VERSION 5.8 ;
BUSBITCHARS "[]" ;
DIVIDERCHAR "/" ;
UNITS
    DATABASE MICRONS 1000 ;
END UNITS

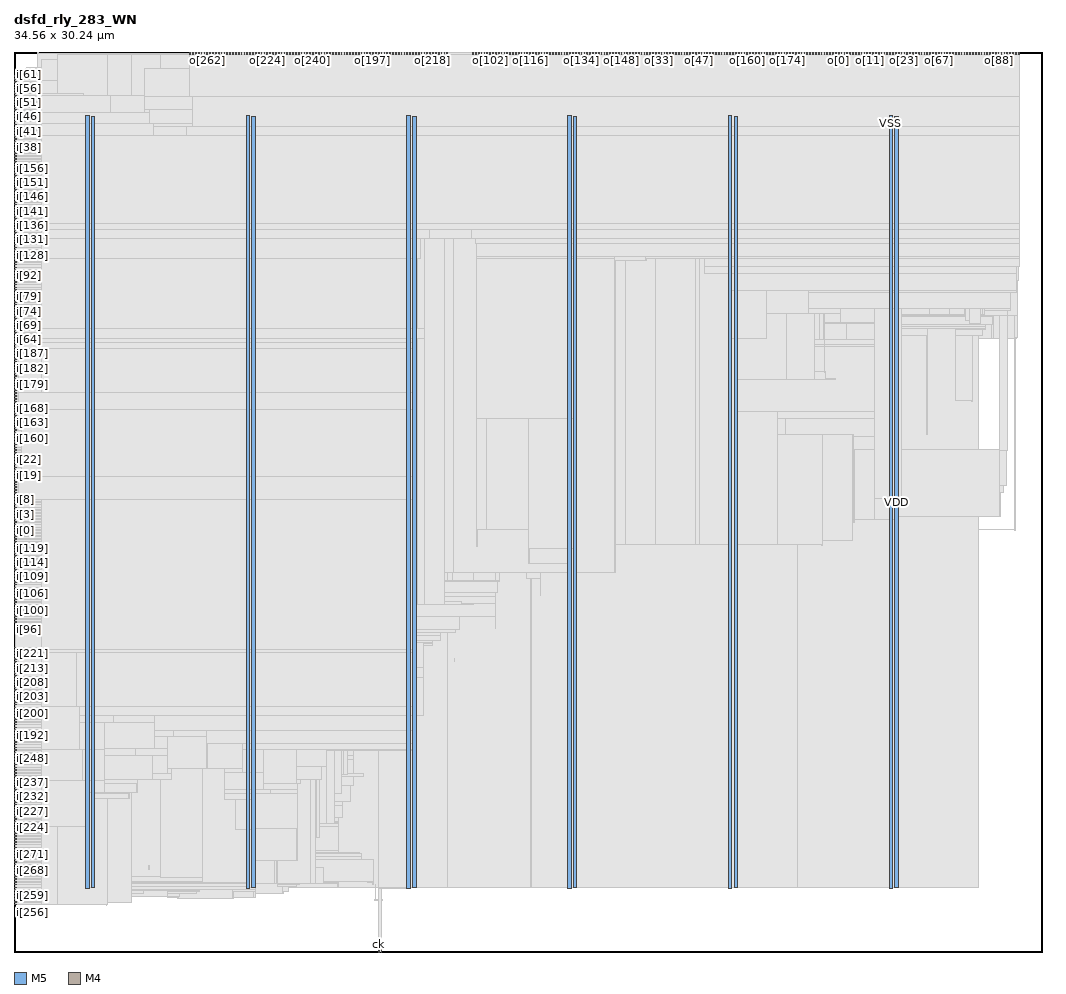
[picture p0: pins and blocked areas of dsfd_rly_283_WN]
MACRO dsfd_rly_283_WN
  FOREIGN dsfd_rly_283_WN 0 0 ;
  CLASS BLOCK ;
  SIZE 34.56 BY 30.24 ;
  PIN ck
    DIRECTION INPUT ;
    USE SIGNAL ;
    PORT
      LAYER M5 ;
        RECT  12.24 0 12.264 0.084 ;
    END
  END ck
  PIN i[0]
    DIRECTION INPUT ;
    USE SIGNAL ;
    PORT
      LAYER M4 ;
        RECT  0 14.16 0.084 14.184 ;
    END
  END i[0]
  PIN i[100]
    DIRECTION INPUT ;
    USE SIGNAL ;
    PORT
      LAYER M4 ;
        RECT  0 11.472 0.084 11.496 ;
    END
  END i[100]
  PIN i[101]
    DIRECTION INPUT ;
    USE SIGNAL ;
    PORT
      LAYER M4 ;
        RECT  0 11.568 0.084 11.592 ;
    END
  END i[101]
  PIN i[102]
    DIRECTION INPUT ;
    USE SIGNAL ;
    PORT
      LAYER M4 ;
        RECT  0 11.664 0.084 11.688 ;
    END
  END i[102]
  PIN i[103]
    DIRECTION INPUT ;
    USE SIGNAL ;
    PORT
      LAYER M4 ;
        RECT  0 11.76 0.084 11.784 ;
    END
  END i[103]
  PIN i[104]
    DIRECTION INPUT ;
    USE SIGNAL ;
    PORT
      LAYER M4 ;
        RECT  0 11.856 0.084 11.88 ;
    END
  END i[104]
  PIN i[105]
    DIRECTION INPUT ;
    USE SIGNAL ;
    PORT
      LAYER M4 ;
        RECT  0 11.952 0.084 11.976 ;
    END
  END i[105]
  PIN i[106]
    DIRECTION INPUT ;
    USE SIGNAL ;
    PORT
      LAYER M4 ;
        RECT  0 12.048 0.084 12.072 ;
    END
  END i[106]
  PIN i[107]
    DIRECTION INPUT ;
    USE SIGNAL ;
    PORT
      LAYER M4 ;
        RECT  0 12.144 0.084 12.168 ;
    END
  END i[107]
  PIN i[108]
    DIRECTION INPUT ;
    USE SIGNAL ;
    PORT
      LAYER M4 ;
        RECT  0 12.24 0.084 12.264 ;
    END
  END i[108]
  PIN i[109]
    DIRECTION INPUT ;
    USE SIGNAL ;
    PORT
      LAYER M4 ;
        RECT  0 12.336 0.084 12.36 ;
    END
  END i[109]
  PIN i[10]
    DIRECTION INPUT ;
    USE SIGNAL ;
    PORT
      LAYER M4 ;
        RECT  0 15.12 0.084 15.144 ;
    END
  END i[10]
  PIN i[110]
    DIRECTION INPUT ;
    USE SIGNAL ;
    PORT
      LAYER M4 ;
        RECT  0 12.432 0.084 12.456 ;
    END
  END i[110]
  PIN i[111]
    DIRECTION INPUT ;
    USE SIGNAL ;
    PORT
      LAYER M4 ;
        RECT  0 12.528 0.084 12.552 ;
    END
  END i[111]
  PIN i[112]
    DIRECTION INPUT ;
    USE SIGNAL ;
    PORT
      LAYER M4 ;
        RECT  0 12.624 0.084 12.648 ;
    END
  END i[112]
  PIN i[113]
    DIRECTION INPUT ;
    USE SIGNAL ;
    PORT
      LAYER M4 ;
        RECT  0 12.72 0.084 12.744 ;
    END
  END i[113]
  PIN i[114]
    DIRECTION INPUT ;
    USE SIGNAL ;
    PORT
      LAYER M4 ;
        RECT  0 12.816 0.084 12.84 ;
    END
  END i[114]
  PIN i[115]
    DIRECTION INPUT ;
    USE SIGNAL ;
    PORT
      LAYER M4 ;
        RECT  0 12.912 0.084 12.936 ;
    END
  END i[115]
  PIN i[116]
    DIRECTION INPUT ;
    USE SIGNAL ;
    PORT
      LAYER M4 ;
        RECT  0 13.008 0.084 13.032 ;
    END
  END i[116]
  PIN i[117]
    DIRECTION INPUT ;
    USE SIGNAL ;
    PORT
      LAYER M4 ;
        RECT  0 13.104 0.084 13.128 ;
    END
  END i[117]
  PIN i[118]
    DIRECTION INPUT ;
    USE SIGNAL ;
    PORT
      LAYER M4 ;
        RECT  0 13.2 0.084 13.224 ;
    END
  END i[118]
  PIN i[119]
    DIRECTION INPUT ;
    USE SIGNAL ;
    PORT
      LAYER M4 ;
        RECT  0 13.296 0.084 13.32 ;
    END
  END i[119]
  PIN i[11]
    DIRECTION INPUT ;
    USE SIGNAL ;
    PORT
      LAYER M4 ;
        RECT  0 15.216 0.084 15.24 ;
    END
  END i[11]
  PIN i[120]
    DIRECTION INPUT ;
    USE SIGNAL ;
    PORT
      LAYER M4 ;
        RECT  0 13.392 0.084 13.416 ;
    END
  END i[120]
  PIN i[121]
    DIRECTION INPUT ;
    USE SIGNAL ;
    PORT
      LAYER M4 ;
        RECT  0 13.488 0.084 13.512 ;
    END
  END i[121]
  PIN i[122]
    DIRECTION INPUT ;
    USE SIGNAL ;
    PORT
      LAYER M4 ;
        RECT  0 13.584 0.084 13.608 ;
    END
  END i[122]
  PIN i[123]
    DIRECTION INPUT ;
    USE SIGNAL ;
    PORT
      LAYER M4 ;
        RECT  0 13.68 0.084 13.704 ;
    END
  END i[123]
  PIN i[124]
    DIRECTION INPUT ;
    USE SIGNAL ;
    PORT
      LAYER M4 ;
        RECT  0 13.776 0.084 13.8 ;
    END
  END i[124]
  PIN i[125]
    DIRECTION INPUT ;
    USE SIGNAL ;
    PORT
      LAYER M4 ;
        RECT  0 13.872 0.084 13.896 ;
    END
  END i[125]
  PIN i[126]
    DIRECTION INPUT ;
    USE SIGNAL ;
    PORT
      LAYER M4 ;
        RECT  0 13.968 0.084 13.992 ;
    END
  END i[126]
  PIN i[127]
    DIRECTION INPUT ;
    USE SIGNAL ;
    PORT
      LAYER M4 ;
        RECT  0 14.064 0.084 14.088 ;
    END
  END i[127]
  PIN i[128]
    DIRECTION INPUT ;
    USE SIGNAL ;
    PORT
      LAYER M4 ;
        RECT  0 23.376 0.084 23.4 ;
    END
  END i[128]
  PIN i[129]
    DIRECTION INPUT ;
    USE SIGNAL ;
    PORT
      LAYER M4 ;
        RECT  0 23.472 0.084 23.496 ;
    END
  END i[129]
  PIN i[12]
    DIRECTION INPUT ;
    USE SIGNAL ;
    PORT
      LAYER M4 ;
        RECT  0 15.312 0.084 15.336 ;
    END
  END i[12]
  PIN i[130]
    DIRECTION INPUT ;
    USE SIGNAL ;
    PORT
      LAYER M4 ;
        RECT  0 23.568 0.084 23.592 ;
    END
  END i[130]
  PIN i[131]
    DIRECTION INPUT ;
    USE SIGNAL ;
    PORT
      LAYER M4 ;
        RECT  0 23.664 0.084 23.688 ;
    END
  END i[131]
  PIN i[132]
    DIRECTION INPUT ;
    USE SIGNAL ;
    PORT
      LAYER M4 ;
        RECT  0 23.76 0.084 23.784 ;
    END
  END i[132]
  PIN i[133]
    DIRECTION INPUT ;
    USE SIGNAL ;
    PORT
      LAYER M4 ;
        RECT  0 23.856 0.084 23.88 ;
    END
  END i[133]
  PIN i[134]
    DIRECTION INPUT ;
    USE SIGNAL ;
    PORT
      LAYER M4 ;
        RECT  0 23.952 0.084 23.976 ;
    END
  END i[134]
  PIN i[135]
    DIRECTION INPUT ;
    USE SIGNAL ;
    PORT
      LAYER M4 ;
        RECT  0 24.048 0.084 24.072 ;
    END
  END i[135]
  PIN i[136]
    DIRECTION INPUT ;
    USE SIGNAL ;
    PORT
      LAYER M4 ;
        RECT  0 24.144 0.084 24.168 ;
    END
  END i[136]
  PIN i[137]
    DIRECTION INPUT ;
    USE SIGNAL ;
    PORT
      LAYER M4 ;
        RECT  0 24.24 0.084 24.264 ;
    END
  END i[137]
  PIN i[138]
    DIRECTION INPUT ;
    USE SIGNAL ;
    PORT
      LAYER M4 ;
        RECT  0 24.336 0.084 24.36 ;
    END
  END i[138]
  PIN i[139]
    DIRECTION INPUT ;
    USE SIGNAL ;
    PORT
      LAYER M4 ;
        RECT  0 24.432 0.084 24.456 ;
    END
  END i[139]
  PIN i[13]
    DIRECTION INPUT ;
    USE SIGNAL ;
    PORT
      LAYER M4 ;
        RECT  0 15.408 0.084 15.432 ;
    END
  END i[13]
  PIN i[140]
    DIRECTION INPUT ;
    USE SIGNAL ;
    PORT
      LAYER M4 ;
        RECT  0 24.528 0.084 24.552 ;
    END
  END i[140]
  PIN i[141]
    DIRECTION INPUT ;
    USE SIGNAL ;
    PORT
      LAYER M4 ;
        RECT  0 24.624 0.084 24.648 ;
    END
  END i[141]
  PIN i[142]
    DIRECTION INPUT ;
    USE SIGNAL ;
    PORT
      LAYER M4 ;
        RECT  0 24.72 0.084 24.744 ;
    END
  END i[142]
  PIN i[143]
    DIRECTION INPUT ;
    USE SIGNAL ;
    PORT
      LAYER M4 ;
        RECT  0 24.816 0.084 24.84 ;
    END
  END i[143]
  PIN i[144]
    DIRECTION INPUT ;
    USE SIGNAL ;
    PORT
      LAYER M4 ;
        RECT  0 24.912 0.084 24.936 ;
    END
  END i[144]
  PIN i[145]
    DIRECTION INPUT ;
    USE SIGNAL ;
    PORT
      LAYER M4 ;
        RECT  0 25.008 0.084 25.032 ;
    END
  END i[145]
  PIN i[146]
    DIRECTION INPUT ;
    USE SIGNAL ;
    PORT
      LAYER M4 ;
        RECT  0 25.104 0.084 25.128 ;
    END
  END i[146]
  PIN i[147]
    DIRECTION INPUT ;
    USE SIGNAL ;
    PORT
      LAYER M4 ;
        RECT  0 25.2 0.084 25.224 ;
    END
  END i[147]
  PIN i[148]
    DIRECTION INPUT ;
    USE SIGNAL ;
    PORT
      LAYER M4 ;
        RECT  0 25.296 0.084 25.32 ;
    END
  END i[148]
  PIN i[149]
    DIRECTION INPUT ;
    USE SIGNAL ;
    PORT
      LAYER M4 ;
        RECT  0 25.392 0.084 25.416 ;
    END
  END i[149]
  PIN i[14]
    DIRECTION INPUT ;
    USE SIGNAL ;
    PORT
      LAYER M4 ;
        RECT  0 15.504 0.084 15.528 ;
    END
  END i[14]
  PIN i[150]
    DIRECTION INPUT ;
    USE SIGNAL ;
    PORT
      LAYER M4 ;
        RECT  0 25.488 0.084 25.512 ;
    END
  END i[150]
  PIN i[151]
    DIRECTION INPUT ;
    USE SIGNAL ;
    PORT
      LAYER M4 ;
        RECT  0 25.584 0.084 25.608 ;
    END
  END i[151]
  PIN i[152]
    DIRECTION INPUT ;
    USE SIGNAL ;
    PORT
      LAYER M4 ;
        RECT  0 25.68 0.084 25.704 ;
    END
  END i[152]
  PIN i[153]
    DIRECTION INPUT ;
    USE SIGNAL ;
    PORT
      LAYER M4 ;
        RECT  0 25.776 0.084 25.8 ;
    END
  END i[153]
  PIN i[154]
    DIRECTION INPUT ;
    USE SIGNAL ;
    PORT
      LAYER M4 ;
        RECT  0 25.872 0.084 25.896 ;
    END
  END i[154]
  PIN i[155]
    DIRECTION INPUT ;
    USE SIGNAL ;
    PORT
      LAYER M4 ;
        RECT  0 25.968 0.084 25.992 ;
    END
  END i[155]
  PIN i[156]
    DIRECTION INPUT ;
    USE SIGNAL ;
    PORT
      LAYER M4 ;
        RECT  0 26.064 0.084 26.088 ;
    END
  END i[156]
  PIN i[157]
    DIRECTION INPUT ;
    USE SIGNAL ;
    PORT
      LAYER M4 ;
        RECT  0 26.16 0.084 26.184 ;
    END
  END i[157]
  PIN i[158]
    DIRECTION INPUT ;
    USE SIGNAL ;
    PORT
      LAYER M4 ;
        RECT  0 26.256 0.084 26.28 ;
    END
  END i[158]
  PIN i[159]
    DIRECTION INPUT ;
    USE SIGNAL ;
    PORT
      LAYER M4 ;
        RECT  0 26.352 0.084 26.376 ;
    END
  END i[159]
  PIN i[15]
    DIRECTION INPUT ;
    USE SIGNAL ;
    PORT
      LAYER M4 ;
        RECT  0 15.6 0.084 15.624 ;
    END
  END i[15]
  PIN i[160]
    DIRECTION INPUT ;
    USE SIGNAL ;
    PORT
      LAYER M4 ;
        RECT  0 17.232 0.084 17.256 ;
    END
  END i[160]
  PIN i[161]
    DIRECTION INPUT ;
    USE SIGNAL ;
    PORT
      LAYER M4 ;
        RECT  0 17.328 0.084 17.352 ;
    END
  END i[161]
  PIN i[162]
    DIRECTION INPUT ;
    USE SIGNAL ;
    PORT
      LAYER M4 ;
        RECT  0 17.424 0.084 17.448 ;
    END
  END i[162]
  PIN i[163]
    DIRECTION INPUT ;
    USE SIGNAL ;
    PORT
      LAYER M4 ;
        RECT  0 17.52 0.084 17.544 ;
    END
  END i[163]
  PIN i[164]
    DIRECTION INPUT ;
    USE SIGNAL ;
    PORT
      LAYER M4 ;
        RECT  0 17.616 0.084 17.64 ;
    END
  END i[164]
  PIN i[165]
    DIRECTION INPUT ;
    USE SIGNAL ;
    PORT
      LAYER M4 ;
        RECT  0 17.712 0.084 17.736 ;
    END
  END i[165]
  PIN i[166]
    DIRECTION INPUT ;
    USE SIGNAL ;
    PORT
      LAYER M4 ;
        RECT  0 17.808 0.084 17.832 ;
    END
  END i[166]
  PIN i[167]
    DIRECTION INPUT ;
    USE SIGNAL ;
    PORT
      LAYER M4 ;
        RECT  0 17.904 0.084 17.928 ;
    END
  END i[167]
  PIN i[168]
    DIRECTION INPUT ;
    USE SIGNAL ;
    PORT
      LAYER M4 ;
        RECT  0 18 0.084 18.024 ;
    END
  END i[168]
  PIN i[169]
    DIRECTION INPUT ;
    USE SIGNAL ;
    PORT
      LAYER M4 ;
        RECT  0 18.096 0.084 18.12 ;
    END
  END i[169]
  PIN i[16]
    DIRECTION INPUT ;
    USE SIGNAL ;
    PORT
      LAYER M4 ;
        RECT  0 15.696 0.084 15.72 ;
    END
  END i[16]
  PIN i[170]
    DIRECTION INPUT ;
    USE SIGNAL ;
    PORT
      LAYER M4 ;
        RECT  0 18.192 0.084 18.216 ;
    END
  END i[170]
  PIN i[171]
    DIRECTION INPUT ;
    USE SIGNAL ;
    PORT
      LAYER M4 ;
        RECT  0 18.288 0.084 18.312 ;
    END
  END i[171]
  PIN i[172]
    DIRECTION INPUT ;
    USE SIGNAL ;
    PORT
      LAYER M4 ;
        RECT  0 18.384 0.084 18.408 ;
    END
  END i[172]
  PIN i[173]
    DIRECTION INPUT ;
    USE SIGNAL ;
    PORT
      LAYER M4 ;
        RECT  0 18.48 0.084 18.504 ;
    END
  END i[173]
  PIN i[174]
    DIRECTION INPUT ;
    USE SIGNAL ;
    PORT
      LAYER M4 ;
        RECT  0 18.576 0.084 18.6 ;
    END
  END i[174]
  PIN i[175]
    DIRECTION INPUT ;
    USE SIGNAL ;
    PORT
      LAYER M4 ;
        RECT  0 18.672 0.084 18.696 ;
    END
  END i[175]
  PIN i[176]
    DIRECTION INPUT ;
    USE SIGNAL ;
    PORT
      LAYER M4 ;
        RECT  0 18.768 0.084 18.792 ;
    END
  END i[176]
  PIN i[177]
    DIRECTION INPUT ;
    USE SIGNAL ;
    PORT
      LAYER M4 ;
        RECT  0 18.864 0.084 18.888 ;
    END
  END i[177]
  PIN i[178]
    DIRECTION INPUT ;
    USE SIGNAL ;
    PORT
      LAYER M4 ;
        RECT  0 18.96 0.084 18.984 ;
    END
  END i[178]
  PIN i[179]
    DIRECTION INPUT ;
    USE SIGNAL ;
    PORT
      LAYER M4 ;
        RECT  0 19.056 0.084 19.08 ;
    END
  END i[179]
  PIN i[17]
    DIRECTION INPUT ;
    USE SIGNAL ;
    PORT
      LAYER M4 ;
        RECT  0 15.792 0.084 15.816 ;
    END
  END i[17]
  PIN i[180]
    DIRECTION INPUT ;
    USE SIGNAL ;
    PORT
      LAYER M4 ;
        RECT  0 19.152 0.084 19.176 ;
    END
  END i[180]
  PIN i[181]
    DIRECTION INPUT ;
    USE SIGNAL ;
    PORT
      LAYER M4 ;
        RECT  0 19.248 0.084 19.272 ;
    END
  END i[181]
  PIN i[182]
    DIRECTION INPUT ;
    USE SIGNAL ;
    PORT
      LAYER M4 ;
        RECT  0 19.344 0.084 19.368 ;
    END
  END i[182]
  PIN i[183]
    DIRECTION INPUT ;
    USE SIGNAL ;
    PORT
      LAYER M4 ;
        RECT  0 19.44 0.084 19.464 ;
    END
  END i[183]
  PIN i[184]
    DIRECTION INPUT ;
    USE SIGNAL ;
    PORT
      LAYER M4 ;
        RECT  0 19.536 0.084 19.56 ;
    END
  END i[184]
  PIN i[185]
    DIRECTION INPUT ;
    USE SIGNAL ;
    PORT
      LAYER M4 ;
        RECT  0 19.632 0.084 19.656 ;
    END
  END i[185]
  PIN i[186]
    DIRECTION INPUT ;
    USE SIGNAL ;
    PORT
      LAYER M4 ;
        RECT  0 19.728 0.084 19.752 ;
    END
  END i[186]
  PIN i[187]
    DIRECTION INPUT ;
    USE SIGNAL ;
    PORT
      LAYER M4 ;
        RECT  0 19.824 0.084 19.848 ;
    END
  END i[187]
  PIN i[188]
    DIRECTION INPUT ;
    USE SIGNAL ;
    PORT
      LAYER M4 ;
        RECT  0 19.92 0.084 19.944 ;
    END
  END i[188]
  PIN i[189]
    DIRECTION INPUT ;
    USE SIGNAL ;
    PORT
      LAYER M4 ;
        RECT  0 20.016 0.084 20.04 ;
    END
  END i[189]
  PIN i[18]
    DIRECTION INPUT ;
    USE SIGNAL ;
    PORT
      LAYER M4 ;
        RECT  0 15.888 0.084 15.912 ;
    END
  END i[18]
  PIN i[190]
    DIRECTION INPUT ;
    USE SIGNAL ;
    PORT
      LAYER M4 ;
        RECT  0 20.112 0.084 20.136 ;
    END
  END i[190]
  PIN i[191]
    DIRECTION INPUT ;
    USE SIGNAL ;
    PORT
      LAYER M4 ;
        RECT  0 20.208 0.084 20.232 ;
    END
  END i[191]
  PIN i[192]
    DIRECTION INPUT ;
    USE SIGNAL ;
    PORT
      LAYER M4 ;
        RECT  0 7.248 0.084 7.272 ;
    END
  END i[192]
  PIN i[193]
    DIRECTION INPUT ;
    USE SIGNAL ;
    PORT
      LAYER M4 ;
        RECT  0 7.344 0.084 7.368 ;
    END
  END i[193]
  PIN i[194]
    DIRECTION INPUT ;
    USE SIGNAL ;
    PORT
      LAYER M4 ;
        RECT  0 7.44 0.084 7.464 ;
    END
  END i[194]
  PIN i[195]
    DIRECTION INPUT ;
    USE SIGNAL ;
    PORT
      LAYER M4 ;
        RECT  0 7.536 0.084 7.56 ;
    END
  END i[195]
  PIN i[196]
    DIRECTION INPUT ;
    USE SIGNAL ;
    PORT
      LAYER M4 ;
        RECT  0 7.632 0.084 7.656 ;
    END
  END i[196]
  PIN i[197]
    DIRECTION INPUT ;
    USE SIGNAL ;
    PORT
      LAYER M4 ;
        RECT  0 7.728 0.084 7.752 ;
    END
  END i[197]
  PIN i[198]
    DIRECTION INPUT ;
    USE SIGNAL ;
    PORT
      LAYER M4 ;
        RECT  0 7.824 0.084 7.848 ;
    END
  END i[198]
  PIN i[199]
    DIRECTION INPUT ;
    USE SIGNAL ;
    PORT
      LAYER M4 ;
        RECT  0 7.92 0.084 7.944 ;
    END
  END i[199]
  PIN i[19]
    DIRECTION INPUT ;
    USE SIGNAL ;
    PORT
      LAYER M4 ;
        RECT  0 15.984 0.084 16.008 ;
    END
  END i[19]
  PIN i[1]
    DIRECTION INPUT ;
    USE SIGNAL ;
    PORT
      LAYER M4 ;
        RECT  0 14.256 0.084 14.28 ;
    END
  END i[1]
  PIN i[200]
    DIRECTION INPUT ;
    USE SIGNAL ;
    PORT
      LAYER M4 ;
        RECT  0 8.016 0.084 8.04 ;
    END
  END i[200]
  PIN i[201]
    DIRECTION INPUT ;
    USE SIGNAL ;
    PORT
      LAYER M4 ;
        RECT  0 8.112 0.084 8.136 ;
    END
  END i[201]
  PIN i[202]
    DIRECTION INPUT ;
    USE SIGNAL ;
    PORT
      LAYER M4 ;
        RECT  0 8.208 0.084 8.232 ;
    END
  END i[202]
  PIN i[203]
    DIRECTION INPUT ;
    USE SIGNAL ;
    PORT
      LAYER M4 ;
        RECT  0 8.304 0.084 8.328 ;
    END
  END i[203]
  PIN i[204]
    DIRECTION INPUT ;
    USE SIGNAL ;
    PORT
      LAYER M4 ;
        RECT  0 8.4 0.084 8.424 ;
    END
  END i[204]
  PIN i[205]
    DIRECTION INPUT ;
    USE SIGNAL ;
    PORT
      LAYER M4 ;
        RECT  0 8.496 0.084 8.52 ;
    END
  END i[205]
  PIN i[206]
    DIRECTION INPUT ;
    USE SIGNAL ;
    PORT
      LAYER M4 ;
        RECT  0 8.592 0.084 8.616 ;
    END
  END i[206]
  PIN i[207]
    DIRECTION INPUT ;
    USE SIGNAL ;
    PORT
      LAYER M4 ;
        RECT  0 8.688 0.084 8.712 ;
    END
  END i[207]
  PIN i[208]
    DIRECTION INPUT ;
    USE SIGNAL ;
    PORT
      LAYER M4 ;
        RECT  0 8.784 0.084 8.808 ;
    END
  END i[208]
  PIN i[209]
    DIRECTION INPUT ;
    USE SIGNAL ;
    PORT
      LAYER M4 ;
        RECT  0 8.88 0.084 8.904 ;
    END
  END i[209]
  PIN i[20]
    DIRECTION INPUT ;
    USE SIGNAL ;
    PORT
      LAYER M4 ;
        RECT  0 16.08 0.084 16.104 ;
    END
  END i[20]
  PIN i[210]
    DIRECTION INPUT ;
    USE SIGNAL ;
    PORT
      LAYER M4 ;
        RECT  0 8.976 0.084 9 ;
    END
  END i[210]
  PIN i[211]
    DIRECTION INPUT ;
    USE SIGNAL ;
    PORT
      LAYER M4 ;
        RECT  0 9.072 0.084 9.096 ;
    END
  END i[211]
  PIN i[212]
    DIRECTION INPUT ;
    USE SIGNAL ;
    PORT
      LAYER M4 ;
        RECT  0 9.168 0.084 9.192 ;
    END
  END i[212]
  PIN i[213]
    DIRECTION INPUT ;
    USE SIGNAL ;
    PORT
      LAYER M4 ;
        RECT  0 9.264 0.084 9.288 ;
    END
  END i[213]
  PIN i[214]
    DIRECTION INPUT ;
    USE SIGNAL ;
    PORT
      LAYER M4 ;
        RECT  0 9.36 0.084 9.384 ;
    END
  END i[214]
  PIN i[215]
    DIRECTION INPUT ;
    USE SIGNAL ;
    PORT
      LAYER M4 ;
        RECT  0 9.456 0.084 9.48 ;
    END
  END i[215]
  PIN i[216]
    DIRECTION INPUT ;
    USE SIGNAL ;
    PORT
      LAYER M4 ;
        RECT  0 9.552 0.084 9.576 ;
    END
  END i[216]
  PIN i[217]
    DIRECTION INPUT ;
    USE SIGNAL ;
    PORT
      LAYER M4 ;
        RECT  0 9.648 0.084 9.672 ;
    END
  END i[217]
  PIN i[218]
    DIRECTION INPUT ;
    USE SIGNAL ;
    PORT
      LAYER M4 ;
        RECT  0 9.744 0.084 9.768 ;
    END
  END i[218]
  PIN i[219]
    DIRECTION INPUT ;
    USE SIGNAL ;
    PORT
      LAYER M4 ;
        RECT  0 9.84 0.084 9.864 ;
    END
  END i[219]
  PIN i[21]
    DIRECTION INPUT ;
    USE SIGNAL ;
    PORT
      LAYER M4 ;
        RECT  0 16.176 0.084 16.2 ;
    END
  END i[21]
  PIN i[220]
    DIRECTION INPUT ;
    USE SIGNAL ;
    PORT
      LAYER M4 ;
        RECT  0 9.936 0.084 9.96 ;
    END
  END i[220]
  PIN i[221]
    DIRECTION INPUT ;
    USE SIGNAL ;
    PORT
      LAYER M4 ;
        RECT  0 10.032 0.084 10.056 ;
    END
  END i[221]
  PIN i[222]
    DIRECTION INPUT ;
    USE SIGNAL ;
    PORT
      LAYER M4 ;
        RECT  0 10.128 0.084 10.152 ;
    END
  END i[222]
  PIN i[223]
    DIRECTION INPUT ;
    USE SIGNAL ;
    PORT
      LAYER M4 ;
        RECT  0 10.224 0.084 10.248 ;
    END
  END i[223]
  PIN i[224]
    DIRECTION INPUT ;
    USE SIGNAL ;
    PORT
      LAYER M4 ;
        RECT  0 4.176 0.084 4.2 ;
    END
  END i[224]
  PIN i[225]
    DIRECTION INPUT ;
    USE SIGNAL ;
    PORT
      LAYER M4 ;
        RECT  0 4.272 0.084 4.296 ;
    END
  END i[225]
  PIN i[226]
    DIRECTION INPUT ;
    USE SIGNAL ;
    PORT
      LAYER M4 ;
        RECT  0 4.368 0.084 4.392 ;
    END
  END i[226]
  PIN i[227]
    DIRECTION INPUT ;
    USE SIGNAL ;
    PORT
      LAYER M4 ;
        RECT  0 4.464 0.084 4.488 ;
    END
  END i[227]
  PIN i[228]
    DIRECTION INPUT ;
    USE SIGNAL ;
    PORT
      LAYER M4 ;
        RECT  0 4.56 0.084 4.584 ;
    END
  END i[228]
  PIN i[229]
    DIRECTION INPUT ;
    USE SIGNAL ;
    PORT
      LAYER M4 ;
        RECT  0 4.656 0.084 4.68 ;
    END
  END i[229]
  PIN i[22]
    DIRECTION INPUT ;
    USE SIGNAL ;
    PORT
      LAYER M4 ;
        RECT  0 16.272 0.084 16.296 ;
    END
  END i[22]
  PIN i[230]
    DIRECTION INPUT ;
    USE SIGNAL ;
    PORT
      LAYER M4 ;
        RECT  0 4.752 0.084 4.776 ;
    END
  END i[230]
  PIN i[231]
    DIRECTION INPUT ;
    USE SIGNAL ;
    PORT
      LAYER M4 ;
        RECT  0 4.848 0.084 4.872 ;
    END
  END i[231]
  PIN i[232]
    DIRECTION INPUT ;
    USE SIGNAL ;
    PORT
      LAYER M4 ;
        RECT  0 4.944 0.084 4.968 ;
    END
  END i[232]
  PIN i[233]
    DIRECTION INPUT ;
    USE SIGNAL ;
    PORT
      LAYER M4 ;
        RECT  0 5.04 0.084 5.064 ;
    END
  END i[233]
  PIN i[234]
    DIRECTION INPUT ;
    USE SIGNAL ;
    PORT
      LAYER M4 ;
        RECT  0 5.136 0.084 5.16 ;
    END
  END i[234]
  PIN i[235]
    DIRECTION INPUT ;
    USE SIGNAL ;
    PORT
      LAYER M4 ;
        RECT  0 5.232 0.084 5.256 ;
    END
  END i[235]
  PIN i[236]
    DIRECTION INPUT ;
    USE SIGNAL ;
    PORT
      LAYER M4 ;
        RECT  0 5.328 0.084 5.352 ;
    END
  END i[236]
  PIN i[237]
    DIRECTION INPUT ;
    USE SIGNAL ;
    PORT
      LAYER M4 ;
        RECT  0 5.424 0.084 5.448 ;
    END
  END i[237]
  PIN i[238]
    DIRECTION INPUT ;
    USE SIGNAL ;
    PORT
      LAYER M4 ;
        RECT  0 5.52 0.084 5.544 ;
    END
  END i[238]
  PIN i[239]
    DIRECTION INPUT ;
    USE SIGNAL ;
    PORT
      LAYER M4 ;
        RECT  0 5.616 0.084 5.64 ;
    END
  END i[239]
  PIN i[23]
    DIRECTION INPUT ;
    USE SIGNAL ;
    PORT
      LAYER M4 ;
        RECT  0 16.368 0.084 16.392 ;
    END
  END i[23]
  PIN i[240]
    DIRECTION INPUT ;
    USE SIGNAL ;
    PORT
      LAYER M4 ;
        RECT  0 5.712 0.084 5.736 ;
    END
  END i[240]
  PIN i[241]
    DIRECTION INPUT ;
    USE SIGNAL ;
    PORT
      LAYER M4 ;
        RECT  0 5.808 0.084 5.832 ;
    END
  END i[241]
  PIN i[242]
    DIRECTION INPUT ;
    USE SIGNAL ;
    PORT
      LAYER M4 ;
        RECT  0 5.904 0.084 5.928 ;
    END
  END i[242]
  PIN i[243]
    DIRECTION INPUT ;
    USE SIGNAL ;
    PORT
      LAYER M4 ;
        RECT  0 6 0.084 6.024 ;
    END
  END i[243]
  PIN i[244]
    DIRECTION INPUT ;
    USE SIGNAL ;
    PORT
      LAYER M4 ;
        RECT  0 6.096 0.084 6.12 ;
    END
  END i[244]
  PIN i[245]
    DIRECTION INPUT ;
    USE SIGNAL ;
    PORT
      LAYER M4 ;
        RECT  0 6.192 0.084 6.216 ;
    END
  END i[245]
  PIN i[246]
    DIRECTION INPUT ;
    USE SIGNAL ;
    PORT
      LAYER M4 ;
        RECT  0 6.288 0.084 6.312 ;
    END
  END i[246]
  PIN i[247]
    DIRECTION INPUT ;
    USE SIGNAL ;
    PORT
      LAYER M4 ;
        RECT  0 6.384 0.084 6.408 ;
    END
  END i[247]
  PIN i[248]
    DIRECTION INPUT ;
    USE SIGNAL ;
    PORT
      LAYER M4 ;
        RECT  0 6.48 0.084 6.504 ;
    END
  END i[248]
  PIN i[249]
    DIRECTION INPUT ;
    USE SIGNAL ;
    PORT
      LAYER M4 ;
        RECT  0 6.576 0.084 6.6 ;
    END
  END i[249]
  PIN i[24]
    DIRECTION INPUT ;
    USE SIGNAL ;
    PORT
      LAYER M4 ;
        RECT  0 16.464 0.084 16.488 ;
    END
  END i[24]
  PIN i[250]
    DIRECTION INPUT ;
    USE SIGNAL ;
    PORT
      LAYER M4 ;
        RECT  0 6.672 0.084 6.696 ;
    END
  END i[250]
  PIN i[251]
    DIRECTION INPUT ;
    USE SIGNAL ;
    PORT
      LAYER M4 ;
        RECT  0 6.768 0.084 6.792 ;
    END
  END i[251]
  PIN i[252]
    DIRECTION INPUT ;
    USE SIGNAL ;
    PORT
      LAYER M4 ;
        RECT  0 6.864 0.084 6.888 ;
    END
  END i[252]
  PIN i[253]
    DIRECTION INPUT ;
    USE SIGNAL ;
    PORT
      LAYER M4 ;
        RECT  0 6.96 0.084 6.984 ;
    END
  END i[253]
  PIN i[254]
    DIRECTION INPUT ;
    USE SIGNAL ;
    PORT
      LAYER M4 ;
        RECT  0 7.056 0.084 7.08 ;
    END
  END i[254]
  PIN i[255]
    DIRECTION INPUT ;
    USE SIGNAL ;
    PORT
      LAYER M4 ;
        RECT  0 7.152 0.084 7.176 ;
    END
  END i[255]
  PIN i[256]
    DIRECTION INPUT ;
    USE SIGNAL ;
    PORT
      LAYER M4 ;
        RECT  0 1.584 0.084 1.608 ;
    END
  END i[256]
  PIN i[257]
    DIRECTION INPUT ;
    USE SIGNAL ;
    PORT
      LAYER M4 ;
        RECT  0 1.68 0.084 1.704 ;
    END
  END i[257]
  PIN i[258]
    DIRECTION INPUT ;
    USE SIGNAL ;
    PORT
      LAYER M4 ;
        RECT  0 1.776 0.084 1.8 ;
    END
  END i[258]
  PIN i[259]
    DIRECTION INPUT ;
    USE SIGNAL ;
    PORT
      LAYER M4 ;
        RECT  0 1.872 0.084 1.896 ;
    END
  END i[259]
  PIN i[25]
    DIRECTION INPUT ;
    USE SIGNAL ;
    PORT
      LAYER M4 ;
        RECT  0 16.56 0.084 16.584 ;
    END
  END i[25]
  PIN i[260]
    DIRECTION INPUT ;
    USE SIGNAL ;
    PORT
      LAYER M4 ;
        RECT  0 1.968 0.084 1.992 ;
    END
  END i[260]
  PIN i[261]
    DIRECTION INPUT ;
    USE SIGNAL ;
    PORT
      LAYER M4 ;
        RECT  0 2.064 0.084 2.088 ;
    END
  END i[261]
  PIN i[262]
    DIRECTION INPUT ;
    USE SIGNAL ;
    PORT
      LAYER M4 ;
        RECT  0 2.16 0.084 2.184 ;
    END
  END i[262]
  PIN i[263]
    DIRECTION INPUT ;
    USE SIGNAL ;
    PORT
      LAYER M4 ;
        RECT  0 2.256 0.084 2.28 ;
    END
  END i[263]
  PIN i[264]
    DIRECTION INPUT ;
    USE SIGNAL ;
    PORT
      LAYER M4 ;
        RECT  0 2.352 0.084 2.376 ;
    END
  END i[264]
  PIN i[265]
    DIRECTION INPUT ;
    USE SIGNAL ;
    PORT
      LAYER M4 ;
        RECT  0 2.448 0.084 2.472 ;
    END
  END i[265]
  PIN i[266]
    DIRECTION INPUT ;
    USE SIGNAL ;
    PORT
      LAYER M4 ;
        RECT  0 2.544 0.084 2.568 ;
    END
  END i[266]
  PIN i[267]
    DIRECTION INPUT ;
    USE SIGNAL ;
    PORT
      LAYER M4 ;
        RECT  0 2.64 0.084 2.664 ;
    END
  END i[267]
  PIN i[268]
    DIRECTION INPUT ;
    USE SIGNAL ;
    PORT
      LAYER M4 ;
        RECT  0 2.736 0.084 2.76 ;
    END
  END i[268]
  PIN i[269]
    DIRECTION INPUT ;
    USE SIGNAL ;
    PORT
      LAYER M4 ;
        RECT  0 2.832 0.084 2.856 ;
    END
  END i[269]
  PIN i[26]
    DIRECTION INPUT ;
    USE SIGNAL ;
    PORT
      LAYER M4 ;
        RECT  0 16.656 0.084 16.68 ;
    END
  END i[26]
  PIN i[270]
    DIRECTION INPUT ;
    USE SIGNAL ;
    PORT
      LAYER M4 ;
        RECT  0 2.928 0.084 2.952 ;
    END
  END i[270]
  PIN i[271]
    DIRECTION INPUT ;
    USE SIGNAL ;
    PORT
      LAYER M4 ;
        RECT  0 3.024 0.084 3.048 ;
    END
  END i[271]
  PIN i[272]
    DIRECTION INPUT ;
    USE SIGNAL ;
    PORT
      LAYER M4 ;
        RECT  0 3.12 0.084 3.144 ;
    END
  END i[272]
  PIN i[273]
    DIRECTION INPUT ;
    USE SIGNAL ;
    PORT
      LAYER M4 ;
        RECT  0 3.216 0.084 3.24 ;
    END
  END i[273]
  PIN i[274]
    DIRECTION INPUT ;
    USE SIGNAL ;
    PORT
      LAYER M4 ;
        RECT  0 3.312 0.084 3.336 ;
    END
  END i[274]
  PIN i[275]
    DIRECTION INPUT ;
    USE SIGNAL ;
    PORT
      LAYER M4 ;
        RECT  0 3.408 0.084 3.432 ;
    END
  END i[275]
  PIN i[276]
    DIRECTION INPUT ;
    USE SIGNAL ;
    PORT
      LAYER M4 ;
        RECT  0 3.504 0.084 3.528 ;
    END
  END i[276]
  PIN i[277]
    DIRECTION INPUT ;
    USE SIGNAL ;
    PORT
      LAYER M4 ;
        RECT  0 3.6 0.084 3.624 ;
    END
  END i[277]
  PIN i[278]
    DIRECTION INPUT ;
    USE SIGNAL ;
    PORT
      LAYER M4 ;
        RECT  0 3.696 0.084 3.72 ;
    END
  END i[278]
  PIN i[279]
    DIRECTION INPUT ;
    USE SIGNAL ;
    PORT
      LAYER M4 ;
        RECT  0 3.792 0.084 3.816 ;
    END
  END i[279]
  PIN i[27]
    DIRECTION INPUT ;
    USE SIGNAL ;
    PORT
      LAYER M4 ;
        RECT  0 16.752 0.084 16.776 ;
    END
  END i[27]
  PIN i[280]
    DIRECTION INPUT ;
    USE SIGNAL ;
    PORT
      LAYER M4 ;
        RECT  0 3.888 0.084 3.912 ;
    END
  END i[280]
  PIN i[281]
    DIRECTION INPUT ;
    USE SIGNAL ;
    PORT
      LAYER M4 ;
        RECT  0 3.984 0.084 4.008 ;
    END
  END i[281]
  PIN i[282]
    DIRECTION INPUT ;
    USE SIGNAL ;
    PORT
      LAYER M4 ;
        RECT  0 4.08 0.084 4.104 ;
    END
  END i[282]
  PIN i[28]
    DIRECTION INPUT ;
    USE SIGNAL ;
    PORT
      LAYER M4 ;
        RECT  0 16.848 0.084 16.872 ;
    END
  END i[28]
  PIN i[29]
    DIRECTION INPUT ;
    USE SIGNAL ;
    PORT
      LAYER M4 ;
        RECT  0 16.944 0.084 16.968 ;
    END
  END i[29]
  PIN i[2]
    DIRECTION INPUT ;
    USE SIGNAL ;
    PORT
      LAYER M4 ;
        RECT  0 14.352 0.084 14.376 ;
    END
  END i[2]
  PIN i[30]
    DIRECTION INPUT ;
    USE SIGNAL ;
    PORT
      LAYER M4 ;
        RECT  0 17.04 0.084 17.064 ;
    END
  END i[30]
  PIN i[31]
    DIRECTION INPUT ;
    USE SIGNAL ;
    PORT
      LAYER M4 ;
        RECT  0 17.136 0.084 17.16 ;
    END
  END i[31]
  PIN i[32]
    DIRECTION INPUT ;
    USE SIGNAL ;
    PORT
      LAYER M4 ;
        RECT  0 26.448 0.084 26.472 ;
    END
  END i[32]
  PIN i[33]
    DIRECTION INPUT ;
    USE SIGNAL ;
    PORT
      LAYER M4 ;
        RECT  0 26.544 0.084 26.568 ;
    END
  END i[33]
  PIN i[34]
    DIRECTION INPUT ;
    USE SIGNAL ;
    PORT
      LAYER M4 ;
        RECT  0 26.64 0.084 26.664 ;
    END
  END i[34]
  PIN i[35]
    DIRECTION INPUT ;
    USE SIGNAL ;
    PORT
      LAYER M4 ;
        RECT  0 26.736 0.084 26.76 ;
    END
  END i[35]
  PIN i[36]
    DIRECTION INPUT ;
    USE SIGNAL ;
    PORT
      LAYER M4 ;
        RECT  0 26.832 0.084 26.856 ;
    END
  END i[36]
  PIN i[37]
    DIRECTION INPUT ;
    USE SIGNAL ;
    PORT
      LAYER M4 ;
        RECT  0 26.928 0.084 26.952 ;
    END
  END i[37]
  PIN i[38]
    DIRECTION INPUT ;
    USE SIGNAL ;
    PORT
      LAYER M4 ;
        RECT  0 27.024 0.084 27.048 ;
    END
  END i[38]
  PIN i[39]
    DIRECTION INPUT ;
    USE SIGNAL ;
    PORT
      LAYER M4 ;
        RECT  0 27.12 0.084 27.144 ;
    END
  END i[39]
  PIN i[3]
    DIRECTION INPUT ;
    USE SIGNAL ;
    PORT
      LAYER M4 ;
        RECT  0 14.448 0.084 14.472 ;
    END
  END i[3]
  PIN i[40]
    DIRECTION INPUT ;
    USE SIGNAL ;
    PORT
      LAYER M4 ;
        RECT  0 27.216 0.084 27.24 ;
    END
  END i[40]
  PIN i[41]
    DIRECTION INPUT ;
    USE SIGNAL ;
    PORT
      LAYER M4 ;
        RECT  0 27.312 0.084 27.336 ;
    END
  END i[41]
  PIN i[42]
    DIRECTION INPUT ;
    USE SIGNAL ;
    PORT
      LAYER M4 ;
        RECT  0 27.408 0.084 27.432 ;
    END
  END i[42]
  PIN i[43]
    DIRECTION INPUT ;
    USE SIGNAL ;
    PORT
      LAYER M4 ;
        RECT  0 27.504 0.084 27.528 ;
    END
  END i[43]
  PIN i[44]
    DIRECTION INPUT ;
    USE SIGNAL ;
    PORT
      LAYER M4 ;
        RECT  0 27.6 0.084 27.624 ;
    END
  END i[44]
  PIN i[45]
    DIRECTION INPUT ;
    USE SIGNAL ;
    PORT
      LAYER M4 ;
        RECT  0 27.696 0.084 27.72 ;
    END
  END i[45]
  PIN i[46]
    DIRECTION INPUT ;
    USE SIGNAL ;
    PORT
      LAYER M4 ;
        RECT  0 27.792 0.084 27.816 ;
    END
  END i[46]
  PIN i[47]
    DIRECTION INPUT ;
    USE SIGNAL ;
    PORT
      LAYER M4 ;
        RECT  0 27.888 0.084 27.912 ;
    END
  END i[47]
  PIN i[48]
    DIRECTION INPUT ;
    USE SIGNAL ;
    PORT
      LAYER M4 ;
        RECT  0 27.984 0.084 28.008 ;
    END
  END i[48]
  PIN i[49]
    DIRECTION INPUT ;
    USE SIGNAL ;
    PORT
      LAYER M4 ;
        RECT  0 28.08 0.084 28.104 ;
    END
  END i[49]
  PIN i[4]
    DIRECTION INPUT ;
    USE SIGNAL ;
    PORT
      LAYER M4 ;
        RECT  0 14.544 0.084 14.568 ;
    END
  END i[4]
  PIN i[50]
    DIRECTION INPUT ;
    USE SIGNAL ;
    PORT
      LAYER M4 ;
        RECT  0 28.176 0.084 28.2 ;
    END
  END i[50]
  PIN i[51]
    DIRECTION INPUT ;
    USE SIGNAL ;
    PORT
      LAYER M4 ;
        RECT  0 28.272 0.084 28.296 ;
    END
  END i[51]
  PIN i[52]
    DIRECTION INPUT ;
    USE SIGNAL ;
    PORT
      LAYER M4 ;
        RECT  0 28.368 0.084 28.392 ;
    END
  END i[52]
  PIN i[53]
    DIRECTION INPUT ;
    USE SIGNAL ;
    PORT
      LAYER M4 ;
        RECT  0 28.464 0.084 28.488 ;
    END
  END i[53]
  PIN i[54]
    DIRECTION INPUT ;
    USE SIGNAL ;
    PORT
      LAYER M4 ;
        RECT  0 28.56 0.084 28.584 ;
    END
  END i[54]
  PIN i[55]
    DIRECTION INPUT ;
    USE SIGNAL ;
    PORT
      LAYER M4 ;
        RECT  0 28.656 0.084 28.68 ;
    END
  END i[55]
  PIN i[56]
    DIRECTION INPUT ;
    USE SIGNAL ;
    PORT
      LAYER M4 ;
        RECT  0 28.752 0.084 28.776 ;
    END
  END i[56]
  PIN i[57]
    DIRECTION INPUT ;
    USE SIGNAL ;
    PORT
      LAYER M4 ;
        RECT  0 28.848 0.084 28.872 ;
    END
  END i[57]
  PIN i[58]
    DIRECTION INPUT ;
    USE SIGNAL ;
    PORT
      LAYER M4 ;
        RECT  0 28.944 0.084 28.968 ;
    END
  END i[58]
  PIN i[59]
    DIRECTION INPUT ;
    USE SIGNAL ;
    PORT
      LAYER M4 ;
        RECT  0 29.04 0.084 29.064 ;
    END
  END i[59]
  PIN i[5]
    DIRECTION INPUT ;
    USE SIGNAL ;
    PORT
      LAYER M4 ;
        RECT  0 14.64 0.084 14.664 ;
    END
  END i[5]
  PIN i[60]
    DIRECTION INPUT ;
    USE SIGNAL ;
    PORT
      LAYER M4 ;
        RECT  0 29.136 0.084 29.16 ;
    END
  END i[60]
  PIN i[61]
    DIRECTION INPUT ;
    USE SIGNAL ;
    PORT
      LAYER M4 ;
        RECT  0 29.232 0.084 29.256 ;
    END
  END i[61]
  PIN i[62]
    DIRECTION INPUT ;
    USE SIGNAL ;
    PORT
      LAYER M4 ;
        RECT  0 29.328 0.084 29.352 ;
    END
  END i[62]
  PIN i[63]
    DIRECTION INPUT ;
    USE SIGNAL ;
    PORT
      LAYER M4 ;
        RECT  0 29.424 0.084 29.448 ;
    END
  END i[63]
  PIN i[64]
    DIRECTION INPUT ;
    USE SIGNAL ;
    PORT
      LAYER M4 ;
        RECT  0 20.304 0.084 20.328 ;
    END
  END i[64]
  PIN i[65]
    DIRECTION INPUT ;
    USE SIGNAL ;
    PORT
      LAYER M4 ;
        RECT  0 20.4 0.084 20.424 ;
    END
  END i[65]
  PIN i[66]
    DIRECTION INPUT ;
    USE SIGNAL ;
    PORT
      LAYER M4 ;
        RECT  0 20.496 0.084 20.52 ;
    END
  END i[66]
  PIN i[67]
    DIRECTION INPUT ;
    USE SIGNAL ;
    PORT
      LAYER M4 ;
        RECT  0 20.592 0.084 20.616 ;
    END
  END i[67]
  PIN i[68]
    DIRECTION INPUT ;
    USE SIGNAL ;
    PORT
      LAYER M4 ;
        RECT  0 20.688 0.084 20.712 ;
    END
  END i[68]
  PIN i[69]
    DIRECTION INPUT ;
    USE SIGNAL ;
    PORT
      LAYER M4 ;
        RECT  0 20.784 0.084 20.808 ;
    END
  END i[69]
  PIN i[6]
    DIRECTION INPUT ;
    USE SIGNAL ;
    PORT
      LAYER M4 ;
        RECT  0 14.736 0.084 14.76 ;
    END
  END i[6]
  PIN i[70]
    DIRECTION INPUT ;
    USE SIGNAL ;
    PORT
      LAYER M4 ;
        RECT  0 20.88 0.084 20.904 ;
    END
  END i[70]
  PIN i[71]
    DIRECTION INPUT ;
    USE SIGNAL ;
    PORT
      LAYER M4 ;
        RECT  0 20.976 0.084 21 ;
    END
  END i[71]
  PIN i[72]
    DIRECTION INPUT ;
    USE SIGNAL ;
    PORT
      LAYER M4 ;
        RECT  0 21.072 0.084 21.096 ;
    END
  END i[72]
  PIN i[73]
    DIRECTION INPUT ;
    USE SIGNAL ;
    PORT
      LAYER M4 ;
        RECT  0 21.168 0.084 21.192 ;
    END
  END i[73]
  PIN i[74]
    DIRECTION INPUT ;
    USE SIGNAL ;
    PORT
      LAYER M4 ;
        RECT  0 21.264 0.084 21.288 ;
    END
  END i[74]
  PIN i[75]
    DIRECTION INPUT ;
    USE SIGNAL ;
    PORT
      LAYER M4 ;
        RECT  0 21.36 0.084 21.384 ;
    END
  END i[75]
  PIN i[76]
    DIRECTION INPUT ;
    USE SIGNAL ;
    PORT
      LAYER M4 ;
        RECT  0 21.456 0.084 21.48 ;
    END
  END i[76]
  PIN i[77]
    DIRECTION INPUT ;
    USE SIGNAL ;
    PORT
      LAYER M4 ;
        RECT  0 21.552 0.084 21.576 ;
    END
  END i[77]
  PIN i[78]
    DIRECTION INPUT ;
    USE SIGNAL ;
    PORT
      LAYER M4 ;
        RECT  0 21.648 0.084 21.672 ;
    END
  END i[78]
  PIN i[79]
    DIRECTION INPUT ;
    USE SIGNAL ;
    PORT
      LAYER M4 ;
        RECT  0 21.744 0.084 21.768 ;
    END
  END i[79]
  PIN i[7]
    DIRECTION INPUT ;
    USE SIGNAL ;
    PORT
      LAYER M4 ;
        RECT  0 14.832 0.084 14.856 ;
    END
  END i[7]
  PIN i[80]
    DIRECTION INPUT ;
    USE SIGNAL ;
    PORT
      LAYER M4 ;
        RECT  0 21.84 0.084 21.864 ;
    END
  END i[80]
  PIN i[81]
    DIRECTION INPUT ;
    USE SIGNAL ;
    PORT
      LAYER M4 ;
        RECT  0 21.936 0.084 21.96 ;
    END
  END i[81]
  PIN i[82]
    DIRECTION INPUT ;
    USE SIGNAL ;
    PORT
      LAYER M4 ;
        RECT  0 22.032 0.084 22.056 ;
    END
  END i[82]
  PIN i[83]
    DIRECTION INPUT ;
    USE SIGNAL ;
    PORT
      LAYER M4 ;
        RECT  0 22.128 0.084 22.152 ;
    END
  END i[83]
  PIN i[84]
    DIRECTION INPUT ;
    USE SIGNAL ;
    PORT
      LAYER M4 ;
        RECT  0 22.224 0.084 22.248 ;
    END
  END i[84]
  PIN i[85]
    DIRECTION INPUT ;
    USE SIGNAL ;
    PORT
      LAYER M4 ;
        RECT  0 22.32 0.084 22.344 ;
    END
  END i[85]
  PIN i[86]
    DIRECTION INPUT ;
    USE SIGNAL ;
    PORT
      LAYER M4 ;
        RECT  0 22.416 0.084 22.44 ;
    END
  END i[86]
  PIN i[87]
    DIRECTION INPUT ;
    USE SIGNAL ;
    PORT
      LAYER M4 ;
        RECT  0 22.512 0.084 22.536 ;
    END
  END i[87]
  PIN i[88]
    DIRECTION INPUT ;
    USE SIGNAL ;
    PORT
      LAYER M4 ;
        RECT  0 22.608 0.084 22.632 ;
    END
  END i[88]
  PIN i[89]
    DIRECTION INPUT ;
    USE SIGNAL ;
    PORT
      LAYER M4 ;
        RECT  0 22.704 0.084 22.728 ;
    END
  END i[89]
  PIN i[8]
    DIRECTION INPUT ;
    USE SIGNAL ;
    PORT
      LAYER M4 ;
        RECT  0 14.928 0.084 14.952 ;
    END
  END i[8]
  PIN i[90]
    DIRECTION INPUT ;
    USE SIGNAL ;
    PORT
      LAYER M4 ;
        RECT  0 22.8 0.084 22.824 ;
    END
  END i[90]
  PIN i[91]
    DIRECTION INPUT ;
    USE SIGNAL ;
    PORT
      LAYER M4 ;
        RECT  0 22.896 0.084 22.92 ;
    END
  END i[91]
  PIN i[92]
    DIRECTION INPUT ;
    USE SIGNAL ;
    PORT
      LAYER M4 ;
        RECT  0 22.992 0.084 23.016 ;
    END
  END i[92]
  PIN i[93]
    DIRECTION INPUT ;
    USE SIGNAL ;
    PORT
      LAYER M4 ;
        RECT  0 23.088 0.084 23.112 ;
    END
  END i[93]
  PIN i[94]
    DIRECTION INPUT ;
    USE SIGNAL ;
    PORT
      LAYER M4 ;
        RECT  0 23.184 0.084 23.208 ;
    END
  END i[94]
  PIN i[95]
    DIRECTION INPUT ;
    USE SIGNAL ;
    PORT
      LAYER M4 ;
        RECT  0 23.28 0.084 23.304 ;
    END
  END i[95]
  PIN i[96]
    DIRECTION INPUT ;
    USE SIGNAL ;
    PORT
      LAYER M4 ;
        RECT  0 11.088 0.084 11.112 ;
    END
  END i[96]
  PIN i[97]
    DIRECTION INPUT ;
    USE SIGNAL ;
    PORT
      LAYER M4 ;
        RECT  0 11.184 0.084 11.208 ;
    END
  END i[97]
  PIN i[98]
    DIRECTION INPUT ;
    USE SIGNAL ;
    PORT
      LAYER M4 ;
        RECT  0 11.28 0.084 11.304 ;
    END
  END i[98]
  PIN i[99]
    DIRECTION INPUT ;
    USE SIGNAL ;
    PORT
      LAYER M4 ;
        RECT  0 11.376 0.084 11.4 ;
    END
  END i[99]
  PIN i[9]
    DIRECTION INPUT ;
    USE SIGNAL ;
    PORT
      LAYER M4 ;
        RECT  0 15.024 0.084 15.048 ;
    END
  END i[9]
  PIN o[0]
    DIRECTION OUTPUT ;
    USE SIGNAL ;
    PORT
      LAYER M5 ;
        RECT  27.696 30.156 27.72 30.24 ;
    END
  END o[0]
  PIN o[100]
    DIRECTION OUTPUT ;
    USE SIGNAL ;
    PORT
      LAYER M5 ;
        RECT  15.792 30.156 15.816 30.24 ;
    END
  END o[100]
  PIN o[101]
    DIRECTION OUTPUT ;
    USE SIGNAL ;
    PORT
      LAYER M5 ;
        RECT  15.888 30.156 15.912 30.24 ;
    END
  END o[101]
  PIN o[102]
    DIRECTION OUTPUT ;
    USE SIGNAL ;
    PORT
      LAYER M5 ;
        RECT  15.984 30.156 16.008 30.24 ;
    END
  END o[102]
  PIN o[103]
    DIRECTION OUTPUT ;
    USE SIGNAL ;
    PORT
      LAYER M5 ;
        RECT  16.08 30.156 16.104 30.24 ;
    END
  END o[103]
  PIN o[104]
    DIRECTION OUTPUT ;
    USE SIGNAL ;
    PORT
      LAYER M5 ;
        RECT  16.176 30.156 16.2 30.24 ;
    END
  END o[104]
  PIN o[105]
    DIRECTION OUTPUT ;
    USE SIGNAL ;
    PORT
      LAYER M5 ;
        RECT  16.272 30.156 16.296 30.24 ;
    END
  END o[105]
  PIN o[106]
    DIRECTION OUTPUT ;
    USE SIGNAL ;
    PORT
      LAYER M5 ;
        RECT  16.368 30.156 16.392 30.24 ;
    END
  END o[106]
  PIN o[107]
    DIRECTION OUTPUT ;
    USE SIGNAL ;
    PORT
      LAYER M5 ;
        RECT  16.464 30.156 16.488 30.24 ;
    END
  END o[107]
  PIN o[108]
    DIRECTION OUTPUT ;
    USE SIGNAL ;
    PORT
      LAYER M5 ;
        RECT  16.56 30.156 16.584 30.24 ;
    END
  END o[108]
  PIN o[109]
    DIRECTION OUTPUT ;
    USE SIGNAL ;
    PORT
      LAYER M5 ;
        RECT  16.656 30.156 16.68 30.24 ;
    END
  END o[109]
  PIN o[10]
    DIRECTION OUTPUT ;
    USE SIGNAL ;
    PORT
      LAYER M5 ;
        RECT  28.656 30.156 28.68 30.24 ;
    END
  END o[10]
  PIN o[110]
    DIRECTION OUTPUT ;
    USE SIGNAL ;
    PORT
      LAYER M5 ;
        RECT  16.752 30.156 16.776 30.24 ;
    END
  END o[110]
  PIN o[111]
    DIRECTION OUTPUT ;
    USE SIGNAL ;
    PORT
      LAYER M5 ;
        RECT  16.848 30.156 16.872 30.24 ;
    END
  END o[111]
  PIN o[112]
    DIRECTION OUTPUT ;
    USE SIGNAL ;
    PORT
      LAYER M5 ;
        RECT  16.944 30.156 16.968 30.24 ;
    END
  END o[112]
  PIN o[113]
    DIRECTION OUTPUT ;
    USE SIGNAL ;
    PORT
      LAYER M5 ;
        RECT  17.04 30.156 17.064 30.24 ;
    END
  END o[113]
  PIN o[114]
    DIRECTION OUTPUT ;
    USE SIGNAL ;
    PORT
      LAYER M5 ;
        RECT  17.136 30.156 17.16 30.24 ;
    END
  END o[114]
  PIN o[115]
    DIRECTION OUTPUT ;
    USE SIGNAL ;
    PORT
      LAYER M5 ;
        RECT  17.232 30.156 17.256 30.24 ;
    END
  END o[115]
  PIN o[116]
    DIRECTION OUTPUT ;
    USE SIGNAL ;
    PORT
      LAYER M5 ;
        RECT  17.328 30.156 17.352 30.24 ;
    END
  END o[116]
  PIN o[117]
    DIRECTION OUTPUT ;
    USE SIGNAL ;
    PORT
      LAYER M5 ;
        RECT  17.424 30.156 17.448 30.24 ;
    END
  END o[117]
  PIN o[118]
    DIRECTION OUTPUT ;
    USE SIGNAL ;
    PORT
      LAYER M5 ;
        RECT  17.52 30.156 17.544 30.24 ;
    END
  END o[118]
  PIN o[119]
    DIRECTION OUTPUT ;
    USE SIGNAL ;
    PORT
      LAYER M5 ;
        RECT  17.616 30.156 17.64 30.24 ;
    END
  END o[119]
  PIN o[11]
    DIRECTION OUTPUT ;
    USE SIGNAL ;
    PORT
      LAYER M5 ;
        RECT  28.752 30.156 28.776 30.24 ;
    END
  END o[11]
  PIN o[120]
    DIRECTION OUTPUT ;
    USE SIGNAL ;
    PORT
      LAYER M5 ;
        RECT  17.712 30.156 17.736 30.24 ;
    END
  END o[120]
  PIN o[121]
    DIRECTION OUTPUT ;
    USE SIGNAL ;
    PORT
      LAYER M5 ;
        RECT  17.808 30.156 17.832 30.24 ;
    END
  END o[121]
  PIN o[122]
    DIRECTION OUTPUT ;
    USE SIGNAL ;
    PORT
      LAYER M5 ;
        RECT  17.904 30.156 17.928 30.24 ;
    END
  END o[122]
  PIN o[123]
    DIRECTION OUTPUT ;
    USE SIGNAL ;
    PORT
      LAYER M5 ;
        RECT  18 30.156 18.024 30.24 ;
    END
  END o[123]
  PIN o[124]
    DIRECTION OUTPUT ;
    USE SIGNAL ;
    PORT
      LAYER M5 ;
        RECT  18.096 30.156 18.12 30.24 ;
    END
  END o[124]
  PIN o[125]
    DIRECTION OUTPUT ;
    USE SIGNAL ;
    PORT
      LAYER M5 ;
        RECT  18.192 30.156 18.216 30.24 ;
    END
  END o[125]
  PIN o[126]
    DIRECTION OUTPUT ;
    USE SIGNAL ;
    PORT
      LAYER M5 ;
        RECT  18.288 30.156 18.312 30.24 ;
    END
  END o[126]
  PIN o[127]
    DIRECTION OUTPUT ;
    USE SIGNAL ;
    PORT
      LAYER M5 ;
        RECT  18.384 30.156 18.408 30.24 ;
    END
  END o[127]
  PIN o[128]
    DIRECTION OUTPUT ;
    USE SIGNAL ;
    PORT
      LAYER M5 ;
        RECT  18.48 30.156 18.504 30.24 ;
    END
  END o[128]
  PIN o[129]
    DIRECTION OUTPUT ;
    USE SIGNAL ;
    PORT
      LAYER M5 ;
        RECT  18.576 30.156 18.6 30.24 ;
    END
  END o[129]
  PIN o[12]
    DIRECTION OUTPUT ;
    USE SIGNAL ;
    PORT
      LAYER M5 ;
        RECT  28.848 30.156 28.872 30.24 ;
    END
  END o[12]
  PIN o[130]
    DIRECTION OUTPUT ;
    USE SIGNAL ;
    PORT
      LAYER M5 ;
        RECT  18.672 30.156 18.696 30.24 ;
    END
  END o[130]
  PIN o[131]
    DIRECTION OUTPUT ;
    USE SIGNAL ;
    PORT
      LAYER M5 ;
        RECT  18.768 30.156 18.792 30.24 ;
    END
  END o[131]
  PIN o[132]
    DIRECTION OUTPUT ;
    USE SIGNAL ;
    PORT
      LAYER M5 ;
        RECT  18.864 30.156 18.888 30.24 ;
    END
  END o[132]
  PIN o[133]
    DIRECTION OUTPUT ;
    USE SIGNAL ;
    PORT
      LAYER M5 ;
        RECT  18.96 30.156 18.984 30.24 ;
    END
  END o[133]
  PIN o[134]
    DIRECTION OUTPUT ;
    USE SIGNAL ;
    PORT
      LAYER M5 ;
        RECT  19.056 30.156 19.08 30.24 ;
    END
  END o[134]
  PIN o[135]
    DIRECTION OUTPUT ;
    USE SIGNAL ;
    PORT
      LAYER M5 ;
        RECT  19.152 30.156 19.176 30.24 ;
    END
  END o[135]
  PIN o[136]
    DIRECTION OUTPUT ;
    USE SIGNAL ;
    PORT
      LAYER M5 ;
        RECT  19.248 30.156 19.272 30.24 ;
    END
  END o[136]
  PIN o[137]
    DIRECTION OUTPUT ;
    USE SIGNAL ;
    PORT
      LAYER M5 ;
        RECT  19.344 30.156 19.368 30.24 ;
    END
  END o[137]
  PIN o[138]
    DIRECTION OUTPUT ;
    USE SIGNAL ;
    PORT
      LAYER M5 ;
        RECT  19.44 30.156 19.464 30.24 ;
    END
  END o[138]
  PIN o[139]
    DIRECTION OUTPUT ;
    USE SIGNAL ;
    PORT
      LAYER M5 ;
        RECT  19.536 30.156 19.56 30.24 ;
    END
  END o[139]
  PIN o[13]
    DIRECTION OUTPUT ;
    USE SIGNAL ;
    PORT
      LAYER M5 ;
        RECT  28.944 30.156 28.968 30.24 ;
    END
  END o[13]
  PIN o[140]
    DIRECTION OUTPUT ;
    USE SIGNAL ;
    PORT
      LAYER M5 ;
        RECT  19.632 30.156 19.656 30.24 ;
    END
  END o[140]
  PIN o[141]
    DIRECTION OUTPUT ;
    USE SIGNAL ;
    PORT
      LAYER M5 ;
        RECT  19.728 30.156 19.752 30.24 ;
    END
  END o[141]
  PIN o[142]
    DIRECTION OUTPUT ;
    USE SIGNAL ;
    PORT
      LAYER M5 ;
        RECT  19.824 30.156 19.848 30.24 ;
    END
  END o[142]
  PIN o[143]
    DIRECTION OUTPUT ;
    USE SIGNAL ;
    PORT
      LAYER M5 ;
        RECT  19.92 30.156 19.944 30.24 ;
    END
  END o[143]
  PIN o[144]
    DIRECTION OUTPUT ;
    USE SIGNAL ;
    PORT
      LAYER M5 ;
        RECT  20.016 30.156 20.04 30.24 ;
    END
  END o[144]
  PIN o[145]
    DIRECTION OUTPUT ;
    USE SIGNAL ;
    PORT
      LAYER M5 ;
        RECT  20.112 30.156 20.136 30.24 ;
    END
  END o[145]
  PIN o[146]
    DIRECTION OUTPUT ;
    USE SIGNAL ;
    PORT
      LAYER M5 ;
        RECT  20.208 30.156 20.232 30.24 ;
    END
  END o[146]
  PIN o[147]
    DIRECTION OUTPUT ;
    USE SIGNAL ;
    PORT
      LAYER M5 ;
        RECT  20.304 30.156 20.328 30.24 ;
    END
  END o[147]
  PIN o[148]
    DIRECTION OUTPUT ;
    USE SIGNAL ;
    PORT
      LAYER M5 ;
        RECT  20.4 30.156 20.424 30.24 ;
    END
  END o[148]
  PIN o[149]
    DIRECTION OUTPUT ;
    USE SIGNAL ;
    PORT
      LAYER M5 ;
        RECT  20.496 30.156 20.52 30.24 ;
    END
  END o[149]
  PIN o[14]
    DIRECTION OUTPUT ;
    USE SIGNAL ;
    PORT
      LAYER M5 ;
        RECT  29.04 30.156 29.064 30.24 ;
    END
  END o[14]
  PIN o[150]
    DIRECTION OUTPUT ;
    USE SIGNAL ;
    PORT
      LAYER M5 ;
        RECT  20.592 30.156 20.616 30.24 ;
    END
  END o[150]
  PIN o[151]
    DIRECTION OUTPUT ;
    USE SIGNAL ;
    PORT
      LAYER M5 ;
        RECT  20.688 30.156 20.712 30.24 ;
    END
  END o[151]
  PIN o[152]
    DIRECTION OUTPUT ;
    USE SIGNAL ;
    PORT
      LAYER M5 ;
        RECT  20.784 30.156 20.808 30.24 ;
    END
  END o[152]
  PIN o[153]
    DIRECTION OUTPUT ;
    USE SIGNAL ;
    PORT
      LAYER M5 ;
        RECT  20.88 30.156 20.904 30.24 ;
    END
  END o[153]
  PIN o[154]
    DIRECTION OUTPUT ;
    USE SIGNAL ;
    PORT
      LAYER M5 ;
        RECT  20.976 30.156 21 30.24 ;
    END
  END o[154]
  PIN o[155]
    DIRECTION OUTPUT ;
    USE SIGNAL ;
    PORT
      LAYER M5 ;
        RECT  21.072 30.156 21.096 30.24 ;
    END
  END o[155]
  PIN o[156]
    DIRECTION OUTPUT ;
    USE SIGNAL ;
    PORT
      LAYER M5 ;
        RECT  21.168 30.156 21.192 30.24 ;
    END
  END o[156]
  PIN o[157]
    DIRECTION OUTPUT ;
    USE SIGNAL ;
    PORT
      LAYER M5 ;
        RECT  21.264 30.156 21.288 30.24 ;
    END
  END o[157]
  PIN o[158]
    DIRECTION OUTPUT ;
    USE SIGNAL ;
    PORT
      LAYER M5 ;
        RECT  21.36 30.156 21.384 30.24 ;
    END
  END o[158]
  PIN o[159]
    DIRECTION OUTPUT ;
    USE SIGNAL ;
    PORT
      LAYER M5 ;
        RECT  21.456 30.156 21.48 30.24 ;
    END
  END o[159]
  PIN o[15]
    DIRECTION OUTPUT ;
    USE SIGNAL ;
    PORT
      LAYER M5 ;
        RECT  29.136 30.156 29.16 30.24 ;
    END
  END o[15]
  PIN o[160]
    DIRECTION OUTPUT ;
    USE SIGNAL ;
    PORT
      LAYER M5 ;
        RECT  24.624 30.156 24.648 30.24 ;
    END
  END o[160]
  PIN o[161]
    DIRECTION OUTPUT ;
    USE SIGNAL ;
    PORT
      LAYER M5 ;
        RECT  24.72 30.156 24.744 30.24 ;
    END
  END o[161]
  PIN o[162]
    DIRECTION OUTPUT ;
    USE SIGNAL ;
    PORT
      LAYER M5 ;
        RECT  24.816 30.156 24.84 30.24 ;
    END
  END o[162]
  PIN o[163]
    DIRECTION OUTPUT ;
    USE SIGNAL ;
    PORT
      LAYER M5 ;
        RECT  24.912 30.156 24.936 30.24 ;
    END
  END o[163]
  PIN o[164]
    DIRECTION OUTPUT ;
    USE SIGNAL ;
    PORT
      LAYER M5 ;
        RECT  25.008 30.156 25.032 30.24 ;
    END
  END o[164]
  PIN o[165]
    DIRECTION OUTPUT ;
    USE SIGNAL ;
    PORT
      LAYER M5 ;
        RECT  25.104 30.156 25.128 30.24 ;
    END
  END o[165]
  PIN o[166]
    DIRECTION OUTPUT ;
    USE SIGNAL ;
    PORT
      LAYER M5 ;
        RECT  25.2 30.156 25.224 30.24 ;
    END
  END o[166]
  PIN o[167]
    DIRECTION OUTPUT ;
    USE SIGNAL ;
    PORT
      LAYER M5 ;
        RECT  25.296 30.156 25.32 30.24 ;
    END
  END o[167]
  PIN o[168]
    DIRECTION OUTPUT ;
    USE SIGNAL ;
    PORT
      LAYER M5 ;
        RECT  25.392 30.156 25.416 30.24 ;
    END
  END o[168]
  PIN o[169]
    DIRECTION OUTPUT ;
    USE SIGNAL ;
    PORT
      LAYER M5 ;
        RECT  25.488 30.156 25.512 30.24 ;
    END
  END o[169]
  PIN o[16]
    DIRECTION OUTPUT ;
    USE SIGNAL ;
    PORT
      LAYER M5 ;
        RECT  29.232 30.156 29.256 30.24 ;
    END
  END o[16]
  PIN o[170]
    DIRECTION OUTPUT ;
    USE SIGNAL ;
    PORT
      LAYER M5 ;
        RECT  25.584 30.156 25.608 30.24 ;
    END
  END o[170]
  PIN o[171]
    DIRECTION OUTPUT ;
    USE SIGNAL ;
    PORT
      LAYER M5 ;
        RECT  25.68 30.156 25.704 30.24 ;
    END
  END o[171]
  PIN o[172]
    DIRECTION OUTPUT ;
    USE SIGNAL ;
    PORT
      LAYER M5 ;
        RECT  25.776 30.156 25.8 30.24 ;
    END
  END o[172]
  PIN o[173]
    DIRECTION OUTPUT ;
    USE SIGNAL ;
    PORT
      LAYER M5 ;
        RECT  25.872 30.156 25.896 30.24 ;
    END
  END o[173]
  PIN o[174]
    DIRECTION OUTPUT ;
    USE SIGNAL ;
    PORT
      LAYER M5 ;
        RECT  25.968 30.156 25.992 30.24 ;
    END
  END o[174]
  PIN o[175]
    DIRECTION OUTPUT ;
    USE SIGNAL ;
    PORT
      LAYER M5 ;
        RECT  26.064 30.156 26.088 30.24 ;
    END
  END o[175]
  PIN o[176]
    DIRECTION OUTPUT ;
    USE SIGNAL ;
    PORT
      LAYER M5 ;
        RECT  26.16 30.156 26.184 30.24 ;
    END
  END o[176]
  PIN o[177]
    DIRECTION OUTPUT ;
    USE SIGNAL ;
    PORT
      LAYER M5 ;
        RECT  26.256 30.156 26.28 30.24 ;
    END
  END o[177]
  PIN o[178]
    DIRECTION OUTPUT ;
    USE SIGNAL ;
    PORT
      LAYER M5 ;
        RECT  26.352 30.156 26.376 30.24 ;
    END
  END o[178]
  PIN o[179]
    DIRECTION OUTPUT ;
    USE SIGNAL ;
    PORT
      LAYER M5 ;
        RECT  26.448 30.156 26.472 30.24 ;
    END
  END o[179]
  PIN o[17]
    DIRECTION OUTPUT ;
    USE SIGNAL ;
    PORT
      LAYER M5 ;
        RECT  29.328 30.156 29.352 30.24 ;
    END
  END o[17]
  PIN o[180]
    DIRECTION OUTPUT ;
    USE SIGNAL ;
    PORT
      LAYER M5 ;
        RECT  26.544 30.156 26.568 30.24 ;
    END
  END o[180]
  PIN o[181]
    DIRECTION OUTPUT ;
    USE SIGNAL ;
    PORT
      LAYER M5 ;
        RECT  26.64 30.156 26.664 30.24 ;
    END
  END o[181]
  PIN o[182]
    DIRECTION OUTPUT ;
    USE SIGNAL ;
    PORT
      LAYER M5 ;
        RECT  26.736 30.156 26.76 30.24 ;
    END
  END o[182]
  PIN o[183]
    DIRECTION OUTPUT ;
    USE SIGNAL ;
    PORT
      LAYER M5 ;
        RECT  26.832 30.156 26.856 30.24 ;
    END
  END o[183]
  PIN o[184]
    DIRECTION OUTPUT ;
    USE SIGNAL ;
    PORT
      LAYER M5 ;
        RECT  26.928 30.156 26.952 30.24 ;
    END
  END o[184]
  PIN o[185]
    DIRECTION OUTPUT ;
    USE SIGNAL ;
    PORT
      LAYER M5 ;
        RECT  27.024 30.156 27.048 30.24 ;
    END
  END o[185]
  PIN o[186]
    DIRECTION OUTPUT ;
    USE SIGNAL ;
    PORT
      LAYER M5 ;
        RECT  27.12 30.156 27.144 30.24 ;
    END
  END o[186]
  PIN o[187]
    DIRECTION OUTPUT ;
    USE SIGNAL ;
    PORT
      LAYER M5 ;
        RECT  27.216 30.156 27.24 30.24 ;
    END
  END o[187]
  PIN o[188]
    DIRECTION OUTPUT ;
    USE SIGNAL ;
    PORT
      LAYER M5 ;
        RECT  27.312 30.156 27.336 30.24 ;
    END
  END o[188]
  PIN o[189]
    DIRECTION OUTPUT ;
    USE SIGNAL ;
    PORT
      LAYER M5 ;
        RECT  27.408 30.156 27.432 30.24 ;
    END
  END o[189]
  PIN o[18]
    DIRECTION OUTPUT ;
    USE SIGNAL ;
    PORT
      LAYER M5 ;
        RECT  29.424 30.156 29.448 30.24 ;
    END
  END o[18]
  PIN o[190]
    DIRECTION OUTPUT ;
    USE SIGNAL ;
    PORT
      LAYER M5 ;
        RECT  27.504 30.156 27.528 30.24 ;
    END
  END o[190]
  PIN o[191]
    DIRECTION OUTPUT ;
    USE SIGNAL ;
    PORT
      LAYER M5 ;
        RECT  27.6 30.156 27.624 30.24 ;
    END
  END o[191]
  PIN o[192]
    DIRECTION OUTPUT ;
    USE SIGNAL ;
    PORT
      LAYER M5 ;
        RECT  11.568 30.156 11.592 30.24 ;
    END
  END o[192]
  PIN o[193]
    DIRECTION OUTPUT ;
    USE SIGNAL ;
    PORT
      LAYER M5 ;
        RECT  11.664 30.156 11.688 30.24 ;
    END
  END o[193]
  PIN o[194]
    DIRECTION OUTPUT ;
    USE SIGNAL ;
    PORT
      LAYER M5 ;
        RECT  11.76 30.156 11.784 30.24 ;
    END
  END o[194]
  PIN o[195]
    DIRECTION OUTPUT ;
    USE SIGNAL ;
    PORT
      LAYER M5 ;
        RECT  11.856 30.156 11.88 30.24 ;
    END
  END o[195]
  PIN o[196]
    DIRECTION OUTPUT ;
    USE SIGNAL ;
    PORT
      LAYER M5 ;
        RECT  11.952 30.156 11.976 30.24 ;
    END
  END o[196]
  PIN o[197]
    DIRECTION OUTPUT ;
    USE SIGNAL ;
    PORT
      LAYER M5 ;
        RECT  12.048 30.156 12.072 30.24 ;
    END
  END o[197]
  PIN o[198]
    DIRECTION OUTPUT ;
    USE SIGNAL ;
    PORT
      LAYER M5 ;
        RECT  12.144 30.156 12.168 30.24 ;
    END
  END o[198]
  PIN o[199]
    DIRECTION OUTPUT ;
    USE SIGNAL ;
    PORT
      LAYER M5 ;
        RECT  12.24 30.156 12.264 30.24 ;
    END
  END o[199]
  PIN o[19]
    DIRECTION OUTPUT ;
    USE SIGNAL ;
    PORT
      LAYER M5 ;
        RECT  29.52 30.156 29.544 30.24 ;
    END
  END o[19]
  PIN o[1]
    DIRECTION OUTPUT ;
    USE SIGNAL ;
    PORT
      LAYER M5 ;
        RECT  27.792 30.156 27.816 30.24 ;
    END
  END o[1]
  PIN o[200]
    DIRECTION OUTPUT ;
    USE SIGNAL ;
    PORT
      LAYER M5 ;
        RECT  12.336 30.156 12.36 30.24 ;
    END
  END o[200]
  PIN o[201]
    DIRECTION OUTPUT ;
    USE SIGNAL ;
    PORT
      LAYER M5 ;
        RECT  12.432 30.156 12.456 30.24 ;
    END
  END o[201]
  PIN o[202]
    DIRECTION OUTPUT ;
    USE SIGNAL ;
    PORT
      LAYER M5 ;
        RECT  12.528 30.156 12.552 30.24 ;
    END
  END o[202]
  PIN o[203]
    DIRECTION OUTPUT ;
    USE SIGNAL ;
    PORT
      LAYER M5 ;
        RECT  12.624 30.156 12.648 30.24 ;
    END
  END o[203]
  PIN o[204]
    DIRECTION OUTPUT ;
    USE SIGNAL ;
    PORT
      LAYER M5 ;
        RECT  12.72 30.156 12.744 30.24 ;
    END
  END o[204]
  PIN o[205]
    DIRECTION OUTPUT ;
    USE SIGNAL ;
    PORT
      LAYER M5 ;
        RECT  12.816 30.156 12.84 30.24 ;
    END
  END o[205]
  PIN o[206]
    DIRECTION OUTPUT ;
    USE SIGNAL ;
    PORT
      LAYER M5 ;
        RECT  12.912 30.156 12.936 30.24 ;
    END
  END o[206]
  PIN o[207]
    DIRECTION OUTPUT ;
    USE SIGNAL ;
    PORT
      LAYER M5 ;
        RECT  13.008 30.156 13.032 30.24 ;
    END
  END o[207]
  PIN o[208]
    DIRECTION OUTPUT ;
    USE SIGNAL ;
    PORT
      LAYER M5 ;
        RECT  13.104 30.156 13.128 30.24 ;
    END
  END o[208]
  PIN o[209]
    DIRECTION OUTPUT ;
    USE SIGNAL ;
    PORT
      LAYER M5 ;
        RECT  13.2 30.156 13.224 30.24 ;
    END
  END o[209]
  PIN o[20]
    DIRECTION OUTPUT ;
    USE SIGNAL ;
    PORT
      LAYER M5 ;
        RECT  29.616 30.156 29.64 30.24 ;
    END
  END o[20]
  PIN o[210]
    DIRECTION OUTPUT ;
    USE SIGNAL ;
    PORT
      LAYER M5 ;
        RECT  13.296 30.156 13.32 30.24 ;
    END
  END o[210]
  PIN o[211]
    DIRECTION OUTPUT ;
    USE SIGNAL ;
    PORT
      LAYER M5 ;
        RECT  13.392 30.156 13.416 30.24 ;
    END
  END o[211]
  PIN o[212]
    DIRECTION OUTPUT ;
    USE SIGNAL ;
    PORT
      LAYER M5 ;
        RECT  13.488 30.156 13.512 30.24 ;
    END
  END o[212]
  PIN o[213]
    DIRECTION OUTPUT ;
    USE SIGNAL ;
    PORT
      LAYER M5 ;
        RECT  13.584 30.156 13.608 30.24 ;
    END
  END o[213]
  PIN o[214]
    DIRECTION OUTPUT ;
    USE SIGNAL ;
    PORT
      LAYER M5 ;
        RECT  13.68 30.156 13.704 30.24 ;
    END
  END o[214]
  PIN o[215]
    DIRECTION OUTPUT ;
    USE SIGNAL ;
    PORT
      LAYER M5 ;
        RECT  13.776 30.156 13.8 30.24 ;
    END
  END o[215]
  PIN o[216]
    DIRECTION OUTPUT ;
    USE SIGNAL ;
    PORT
      LAYER M5 ;
        RECT  13.872 30.156 13.896 30.24 ;
    END
  END o[216]
  PIN o[217]
    DIRECTION OUTPUT ;
    USE SIGNAL ;
    PORT
      LAYER M5 ;
        RECT  13.968 30.156 13.992 30.24 ;
    END
  END o[217]
  PIN o[218]
    DIRECTION OUTPUT ;
    USE SIGNAL ;
    PORT
      LAYER M5 ;
        RECT  14.064 30.156 14.088 30.24 ;
    END
  END o[218]
  PIN o[219]
    DIRECTION OUTPUT ;
    USE SIGNAL ;
    PORT
      LAYER M5 ;
        RECT  14.16 30.156 14.184 30.24 ;
    END
  END o[219]
  PIN o[21]
    DIRECTION OUTPUT ;
    USE SIGNAL ;
    PORT
      LAYER M5 ;
        RECT  29.712 30.156 29.736 30.24 ;
    END
  END o[21]
  PIN o[220]
    DIRECTION OUTPUT ;
    USE SIGNAL ;
    PORT
      LAYER M5 ;
        RECT  14.256 30.156 14.28 30.24 ;
    END
  END o[220]
  PIN o[221]
    DIRECTION OUTPUT ;
    USE SIGNAL ;
    PORT
      LAYER M5 ;
        RECT  14.352 30.156 14.376 30.24 ;
    END
  END o[221]
  PIN o[222]
    DIRECTION OUTPUT ;
    USE SIGNAL ;
    PORT
      LAYER M5 ;
        RECT  14.448 30.156 14.472 30.24 ;
    END
  END o[222]
  PIN o[223]
    DIRECTION OUTPUT ;
    USE SIGNAL ;
    PORT
      LAYER M5 ;
        RECT  14.544 30.156 14.568 30.24 ;
    END
  END o[223]
  PIN o[224]
    DIRECTION OUTPUT ;
    USE SIGNAL ;
    PORT
      LAYER M5 ;
        RECT  8.496 30.156 8.52 30.24 ;
    END
  END o[224]
  PIN o[225]
    DIRECTION OUTPUT ;
    USE SIGNAL ;
    PORT
      LAYER M5 ;
        RECT  8.592 30.156 8.616 30.24 ;
    END
  END o[225]
  PIN o[226]
    DIRECTION OUTPUT ;
    USE SIGNAL ;
    PORT
      LAYER M5 ;
        RECT  8.688 30.156 8.712 30.24 ;
    END
  END o[226]
  PIN o[227]
    DIRECTION OUTPUT ;
    USE SIGNAL ;
    PORT
      LAYER M5 ;
        RECT  8.784 30.156 8.808 30.24 ;
    END
  END o[227]
  PIN o[228]
    DIRECTION OUTPUT ;
    USE SIGNAL ;
    PORT
      LAYER M5 ;
        RECT  8.88 30.156 8.904 30.24 ;
    END
  END o[228]
  PIN o[229]
    DIRECTION OUTPUT ;
    USE SIGNAL ;
    PORT
      LAYER M5 ;
        RECT  8.976 30.156 9 30.24 ;
    END
  END o[229]
  PIN o[22]
    DIRECTION OUTPUT ;
    USE SIGNAL ;
    PORT
      LAYER M5 ;
        RECT  29.808 30.156 29.832 30.24 ;
    END
  END o[22]
  PIN o[230]
    DIRECTION OUTPUT ;
    USE SIGNAL ;
    PORT
      LAYER M5 ;
        RECT  9.072 30.156 9.096 30.24 ;
    END
  END o[230]
  PIN o[231]
    DIRECTION OUTPUT ;
    USE SIGNAL ;
    PORT
      LAYER M5 ;
        RECT  9.168 30.156 9.192 30.24 ;
    END
  END o[231]
  PIN o[232]
    DIRECTION OUTPUT ;
    USE SIGNAL ;
    PORT
      LAYER M5 ;
        RECT  9.264 30.156 9.288 30.24 ;
    END
  END o[232]
  PIN o[233]
    DIRECTION OUTPUT ;
    USE SIGNAL ;
    PORT
      LAYER M5 ;
        RECT  9.36 30.156 9.384 30.24 ;
    END
  END o[233]
  PIN o[234]
    DIRECTION OUTPUT ;
    USE SIGNAL ;
    PORT
      LAYER M5 ;
        RECT  9.456 30.156 9.48 30.24 ;
    END
  END o[234]
  PIN o[235]
    DIRECTION OUTPUT ;
    USE SIGNAL ;
    PORT
      LAYER M5 ;
        RECT  9.552 30.156 9.576 30.24 ;
    END
  END o[235]
  PIN o[236]
    DIRECTION OUTPUT ;
    USE SIGNAL ;
    PORT
      LAYER M5 ;
        RECT  9.648 30.156 9.672 30.24 ;
    END
  END o[236]
  PIN o[237]
    DIRECTION OUTPUT ;
    USE SIGNAL ;
    PORT
      LAYER M5 ;
        RECT  9.744 30.156 9.768 30.24 ;
    END
  END o[237]
  PIN o[238]
    DIRECTION OUTPUT ;
    USE SIGNAL ;
    PORT
      LAYER M5 ;
        RECT  9.84 30.156 9.864 30.24 ;
    END
  END o[238]
  PIN o[239]
    DIRECTION OUTPUT ;
    USE SIGNAL ;
    PORT
      LAYER M5 ;
        RECT  9.936 30.156 9.96 30.24 ;
    END
  END o[239]
  PIN o[23]
    DIRECTION OUTPUT ;
    USE SIGNAL ;
    PORT
      LAYER M5 ;
        RECT  29.904 30.156 29.928 30.24 ;
    END
  END o[23]
  PIN o[240]
    DIRECTION OUTPUT ;
    USE SIGNAL ;
    PORT
      LAYER M5 ;
        RECT  10.032 30.156 10.056 30.24 ;
    END
  END o[240]
  PIN o[241]
    DIRECTION OUTPUT ;
    USE SIGNAL ;
    PORT
      LAYER M5 ;
        RECT  10.128 30.156 10.152 30.24 ;
    END
  END o[241]
  PIN o[242]
    DIRECTION OUTPUT ;
    USE SIGNAL ;
    PORT
      LAYER M5 ;
        RECT  10.224 30.156 10.248 30.24 ;
    END
  END o[242]
  PIN o[243]
    DIRECTION OUTPUT ;
    USE SIGNAL ;
    PORT
      LAYER M5 ;
        RECT  10.32 30.156 10.344 30.24 ;
    END
  END o[243]
  PIN o[244]
    DIRECTION OUTPUT ;
    USE SIGNAL ;
    PORT
      LAYER M5 ;
        RECT  10.416 30.156 10.44 30.24 ;
    END
  END o[244]
  PIN o[245]
    DIRECTION OUTPUT ;
    USE SIGNAL ;
    PORT
      LAYER M5 ;
        RECT  10.512 30.156 10.536 30.24 ;
    END
  END o[245]
  PIN o[246]
    DIRECTION OUTPUT ;
    USE SIGNAL ;
    PORT
      LAYER M5 ;
        RECT  10.608 30.156 10.632 30.24 ;
    END
  END o[246]
  PIN o[247]
    DIRECTION OUTPUT ;
    USE SIGNAL ;
    PORT
      LAYER M5 ;
        RECT  10.704 30.156 10.728 30.24 ;
    END
  END o[247]
  PIN o[248]
    DIRECTION OUTPUT ;
    USE SIGNAL ;
    PORT
      LAYER M5 ;
        RECT  10.8 30.156 10.824 30.24 ;
    END
  END o[248]
  PIN o[249]
    DIRECTION OUTPUT ;
    USE SIGNAL ;
    PORT
      LAYER M5 ;
        RECT  10.896 30.156 10.92 30.24 ;
    END
  END o[249]
  PIN o[24]
    DIRECTION OUTPUT ;
    USE SIGNAL ;
    PORT
      LAYER M5 ;
        RECT  30 30.156 30.024 30.24 ;
    END
  END o[24]
  PIN o[250]
    DIRECTION OUTPUT ;
    USE SIGNAL ;
    PORT
      LAYER M5 ;
        RECT  10.992 30.156 11.016 30.24 ;
    END
  END o[250]
  PIN o[251]
    DIRECTION OUTPUT ;
    USE SIGNAL ;
    PORT
      LAYER M5 ;
        RECT  11.088 30.156 11.112 30.24 ;
    END
  END o[251]
  PIN o[252]
    DIRECTION OUTPUT ;
    USE SIGNAL ;
    PORT
      LAYER M5 ;
        RECT  11.184 30.156 11.208 30.24 ;
    END
  END o[252]
  PIN o[253]
    DIRECTION OUTPUT ;
    USE SIGNAL ;
    PORT
      LAYER M5 ;
        RECT  11.28 30.156 11.304 30.24 ;
    END
  END o[253]
  PIN o[254]
    DIRECTION OUTPUT ;
    USE SIGNAL ;
    PORT
      LAYER M5 ;
        RECT  11.376 30.156 11.4 30.24 ;
    END
  END o[254]
  PIN o[255]
    DIRECTION OUTPUT ;
    USE SIGNAL ;
    PORT
      LAYER M5 ;
        RECT  11.472 30.156 11.496 30.24 ;
    END
  END o[255]
  PIN o[256]
    DIRECTION OUTPUT ;
    USE SIGNAL ;
    PORT
      LAYER M5 ;
        RECT  5.904 30.156 5.928 30.24 ;
    END
  END o[256]
  PIN o[257]
    DIRECTION OUTPUT ;
    USE SIGNAL ;
    PORT
      LAYER M5 ;
        RECT  6 30.156 6.024 30.24 ;
    END
  END o[257]
  PIN o[258]
    DIRECTION OUTPUT ;
    USE SIGNAL ;
    PORT
      LAYER M5 ;
        RECT  6.096 30.156 6.12 30.24 ;
    END
  END o[258]
  PIN o[259]
    DIRECTION OUTPUT ;
    USE SIGNAL ;
    PORT
      LAYER M5 ;
        RECT  6.192 30.156 6.216 30.24 ;
    END
  END o[259]
  PIN o[25]
    DIRECTION OUTPUT ;
    USE SIGNAL ;
    PORT
      LAYER M5 ;
        RECT  30.096 30.156 30.12 30.24 ;
    END
  END o[25]
  PIN o[260]
    DIRECTION OUTPUT ;
    USE SIGNAL ;
    PORT
      LAYER M5 ;
        RECT  6.288 30.156 6.312 30.24 ;
    END
  END o[260]
  PIN o[261]
    DIRECTION OUTPUT ;
    USE SIGNAL ;
    PORT
      LAYER M5 ;
        RECT  6.384 30.156 6.408 30.24 ;
    END
  END o[261]
  PIN o[262]
    DIRECTION OUTPUT ;
    USE SIGNAL ;
    PORT
      LAYER M5 ;
        RECT  6.48 30.156 6.504 30.24 ;
    END
  END o[262]
  PIN o[263]
    DIRECTION OUTPUT ;
    USE SIGNAL ;
    PORT
      LAYER M5 ;
        RECT  6.576 30.156 6.6 30.24 ;
    END
  END o[263]
  PIN o[264]
    DIRECTION OUTPUT ;
    USE SIGNAL ;
    PORT
      LAYER M5 ;
        RECT  6.672 30.156 6.696 30.24 ;
    END
  END o[264]
  PIN o[265]
    DIRECTION OUTPUT ;
    USE SIGNAL ;
    PORT
      LAYER M5 ;
        RECT  6.768 30.156 6.792 30.24 ;
    END
  END o[265]
  PIN o[266]
    DIRECTION OUTPUT ;
    USE SIGNAL ;
    PORT
      LAYER M5 ;
        RECT  6.864 30.156 6.888 30.24 ;
    END
  END o[266]
  PIN o[267]
    DIRECTION OUTPUT ;
    USE SIGNAL ;
    PORT
      LAYER M5 ;
        RECT  6.96 30.156 6.984 30.24 ;
    END
  END o[267]
  PIN o[268]
    DIRECTION OUTPUT ;
    USE SIGNAL ;
    PORT
      LAYER M5 ;
        RECT  7.056 30.156 7.08 30.24 ;
    END
  END o[268]
  PIN o[269]
    DIRECTION OUTPUT ;
    USE SIGNAL ;
    PORT
      LAYER M5 ;
        RECT  7.152 30.156 7.176 30.24 ;
    END
  END o[269]
  PIN o[26]
    DIRECTION OUTPUT ;
    USE SIGNAL ;
    PORT
      LAYER M5 ;
        RECT  30.192 30.156 30.216 30.24 ;
    END
  END o[26]
  PIN o[270]
    DIRECTION OUTPUT ;
    USE SIGNAL ;
    PORT
      LAYER M5 ;
        RECT  7.248 30.156 7.272 30.24 ;
    END
  END o[270]
  PIN o[271]
    DIRECTION OUTPUT ;
    USE SIGNAL ;
    PORT
      LAYER M5 ;
        RECT  7.344 30.156 7.368 30.24 ;
    END
  END o[271]
  PIN o[272]
    DIRECTION OUTPUT ;
    USE SIGNAL ;
    PORT
      LAYER M5 ;
        RECT  7.44 30.156 7.464 30.24 ;
    END
  END o[272]
  PIN o[273]
    DIRECTION OUTPUT ;
    USE SIGNAL ;
    PORT
      LAYER M5 ;
        RECT  7.536 30.156 7.56 30.24 ;
    END
  END o[273]
  PIN o[274]
    DIRECTION OUTPUT ;
    USE SIGNAL ;
    PORT
      LAYER M5 ;
        RECT  7.632 30.156 7.656 30.24 ;
    END
  END o[274]
  PIN o[275]
    DIRECTION OUTPUT ;
    USE SIGNAL ;
    PORT
      LAYER M5 ;
        RECT  7.728 30.156 7.752 30.24 ;
    END
  END o[275]
  PIN o[276]
    DIRECTION OUTPUT ;
    USE SIGNAL ;
    PORT
      LAYER M5 ;
        RECT  7.824 30.156 7.848 30.24 ;
    END
  END o[276]
  PIN o[277]
    DIRECTION OUTPUT ;
    USE SIGNAL ;
    PORT
      LAYER M5 ;
        RECT  7.92 30.156 7.944 30.24 ;
    END
  END o[277]
  PIN o[278]
    DIRECTION OUTPUT ;
    USE SIGNAL ;
    PORT
      LAYER M5 ;
        RECT  8.016 30.156 8.04 30.24 ;
    END
  END o[278]
  PIN o[279]
    DIRECTION OUTPUT ;
    USE SIGNAL ;
    PORT
      LAYER M5 ;
        RECT  8.112 30.156 8.136 30.24 ;
    END
  END o[279]
  PIN o[27]
    DIRECTION OUTPUT ;
    USE SIGNAL ;
    PORT
      LAYER M5 ;
        RECT  30.288 30.156 30.312 30.24 ;
    END
  END o[27]
  PIN o[280]
    DIRECTION OUTPUT ;
    USE SIGNAL ;
    PORT
      LAYER M5 ;
        RECT  8.208 30.156 8.232 30.24 ;
    END
  END o[280]
  PIN o[281]
    DIRECTION OUTPUT ;
    USE SIGNAL ;
    PORT
      LAYER M5 ;
        RECT  8.304 30.156 8.328 30.24 ;
    END
  END o[281]
  PIN o[282]
    DIRECTION OUTPUT ;
    USE SIGNAL ;
    PORT
      LAYER M5 ;
        RECT  8.4 30.156 8.424 30.24 ;
    END
  END o[282]
  PIN o[28]
    DIRECTION OUTPUT ;
    USE SIGNAL ;
    PORT
      LAYER M5 ;
        RECT  30.384 30.156 30.408 30.24 ;
    END
  END o[28]
  PIN o[29]
    DIRECTION OUTPUT ;
    USE SIGNAL ;
    PORT
      LAYER M5 ;
        RECT  30.48 30.156 30.504 30.24 ;
    END
  END o[29]
  PIN o[2]
    DIRECTION OUTPUT ;
    USE SIGNAL ;
    PORT
      LAYER M5 ;
        RECT  27.888 30.156 27.912 30.24 ;
    END
  END o[2]
  PIN o[30]
    DIRECTION OUTPUT ;
    USE SIGNAL ;
    PORT
      LAYER M5 ;
        RECT  30.576 30.156 30.6 30.24 ;
    END
  END o[30]
  PIN o[31]
    DIRECTION OUTPUT ;
    USE SIGNAL ;
    PORT
      LAYER M5 ;
        RECT  30.672 30.156 30.696 30.24 ;
    END
  END o[31]
  PIN o[32]
    DIRECTION OUTPUT ;
    USE SIGNAL ;
    PORT
      LAYER M5 ;
        RECT  21.552 30.156 21.576 30.24 ;
    END
  END o[32]
  PIN o[33]
    DIRECTION OUTPUT ;
    USE SIGNAL ;
    PORT
      LAYER M5 ;
        RECT  21.648 30.156 21.672 30.24 ;
    END
  END o[33]
  PIN o[34]
    DIRECTION OUTPUT ;
    USE SIGNAL ;
    PORT
      LAYER M5 ;
        RECT  21.744 30.156 21.768 30.24 ;
    END
  END o[34]
  PIN o[35]
    DIRECTION OUTPUT ;
    USE SIGNAL ;
    PORT
      LAYER M5 ;
        RECT  21.84 30.156 21.864 30.24 ;
    END
  END o[35]
  PIN o[36]
    DIRECTION OUTPUT ;
    USE SIGNAL ;
    PORT
      LAYER M5 ;
        RECT  21.936 30.156 21.96 30.24 ;
    END
  END o[36]
  PIN o[37]
    DIRECTION OUTPUT ;
    USE SIGNAL ;
    PORT
      LAYER M5 ;
        RECT  22.032 30.156 22.056 30.24 ;
    END
  END o[37]
  PIN o[38]
    DIRECTION OUTPUT ;
    USE SIGNAL ;
    PORT
      LAYER M5 ;
        RECT  22.128 30.156 22.152 30.24 ;
    END
  END o[38]
  PIN o[39]
    DIRECTION OUTPUT ;
    USE SIGNAL ;
    PORT
      LAYER M5 ;
        RECT  22.224 30.156 22.248 30.24 ;
    END
  END o[39]
  PIN o[3]
    DIRECTION OUTPUT ;
    USE SIGNAL ;
    PORT
      LAYER M5 ;
        RECT  27.984 30.156 28.008 30.24 ;
    END
  END o[3]
  PIN o[40]
    DIRECTION OUTPUT ;
    USE SIGNAL ;
    PORT
      LAYER M5 ;
        RECT  22.32 30.156 22.344 30.24 ;
    END
  END o[40]
  PIN o[41]
    DIRECTION OUTPUT ;
    USE SIGNAL ;
    PORT
      LAYER M5 ;
        RECT  22.416 30.156 22.44 30.24 ;
    END
  END o[41]
  PIN o[42]
    DIRECTION OUTPUT ;
    USE SIGNAL ;
    PORT
      LAYER M5 ;
        RECT  22.512 30.156 22.536 30.24 ;
    END
  END o[42]
  PIN o[43]
    DIRECTION OUTPUT ;
    USE SIGNAL ;
    PORT
      LAYER M5 ;
        RECT  22.608 30.156 22.632 30.24 ;
    END
  END o[43]
  PIN o[44]
    DIRECTION OUTPUT ;
    USE SIGNAL ;
    PORT
      LAYER M5 ;
        RECT  22.704 30.156 22.728 30.24 ;
    END
  END o[44]
  PIN o[45]
    DIRECTION OUTPUT ;
    USE SIGNAL ;
    PORT
      LAYER M5 ;
        RECT  22.8 30.156 22.824 30.24 ;
    END
  END o[45]
  PIN o[46]
    DIRECTION OUTPUT ;
    USE SIGNAL ;
    PORT
      LAYER M5 ;
        RECT  22.896 30.156 22.92 30.24 ;
    END
  END o[46]
  PIN o[47]
    DIRECTION OUTPUT ;
    USE SIGNAL ;
    PORT
      LAYER M5 ;
        RECT  22.992 30.156 23.016 30.24 ;
    END
  END o[47]
  PIN o[48]
    DIRECTION OUTPUT ;
    USE SIGNAL ;
    PORT
      LAYER M5 ;
        RECT  23.088 30.156 23.112 30.24 ;
    END
  END o[48]
  PIN o[49]
    DIRECTION OUTPUT ;
    USE SIGNAL ;
    PORT
      LAYER M5 ;
        RECT  23.184 30.156 23.208 30.24 ;
    END
  END o[49]
  PIN o[4]
    DIRECTION OUTPUT ;
    USE SIGNAL ;
    PORT
      LAYER M5 ;
        RECT  28.08 30.156 28.104 30.24 ;
    END
  END o[4]
  PIN o[50]
    DIRECTION OUTPUT ;
    USE SIGNAL ;
    PORT
      LAYER M5 ;
        RECT  23.28 30.156 23.304 30.24 ;
    END
  END o[50]
  PIN o[51]
    DIRECTION OUTPUT ;
    USE SIGNAL ;
    PORT
      LAYER M5 ;
        RECT  23.376 30.156 23.4 30.24 ;
    END
  END o[51]
  PIN o[52]
    DIRECTION OUTPUT ;
    USE SIGNAL ;
    PORT
      LAYER M5 ;
        RECT  23.472 30.156 23.496 30.24 ;
    END
  END o[52]
  PIN o[53]
    DIRECTION OUTPUT ;
    USE SIGNAL ;
    PORT
      LAYER M5 ;
        RECT  23.568 30.156 23.592 30.24 ;
    END
  END o[53]
  PIN o[54]
    DIRECTION OUTPUT ;
    USE SIGNAL ;
    PORT
      LAYER M5 ;
        RECT  23.664 30.156 23.688 30.24 ;
    END
  END o[54]
  PIN o[55]
    DIRECTION OUTPUT ;
    USE SIGNAL ;
    PORT
      LAYER M5 ;
        RECT  23.76 30.156 23.784 30.24 ;
    END
  END o[55]
  PIN o[56]
    DIRECTION OUTPUT ;
    USE SIGNAL ;
    PORT
      LAYER M5 ;
        RECT  23.856 30.156 23.88 30.24 ;
    END
  END o[56]
  PIN o[57]
    DIRECTION OUTPUT ;
    USE SIGNAL ;
    PORT
      LAYER M5 ;
        RECT  23.952 30.156 23.976 30.24 ;
    END
  END o[57]
  PIN o[58]
    DIRECTION OUTPUT ;
    USE SIGNAL ;
    PORT
      LAYER M5 ;
        RECT  24.048 30.156 24.072 30.24 ;
    END
  END o[58]
  PIN o[59]
    DIRECTION OUTPUT ;
    USE SIGNAL ;
    PORT
      LAYER M5 ;
        RECT  24.144 30.156 24.168 30.24 ;
    END
  END o[59]
  PIN o[5]
    DIRECTION OUTPUT ;
    USE SIGNAL ;
    PORT
      LAYER M5 ;
        RECT  28.176 30.156 28.2 30.24 ;
    END
  END o[5]
  PIN o[60]
    DIRECTION OUTPUT ;
    USE SIGNAL ;
    PORT
      LAYER M5 ;
        RECT  24.24 30.156 24.264 30.24 ;
    END
  END o[60]
  PIN o[61]
    DIRECTION OUTPUT ;
    USE SIGNAL ;
    PORT
      LAYER M5 ;
        RECT  24.336 30.156 24.36 30.24 ;
    END
  END o[61]
  PIN o[62]
    DIRECTION OUTPUT ;
    USE SIGNAL ;
    PORT
      LAYER M5 ;
        RECT  24.432 30.156 24.456 30.24 ;
    END
  END o[62]
  PIN o[63]
    DIRECTION OUTPUT ;
    USE SIGNAL ;
    PORT
      LAYER M5 ;
        RECT  24.528 30.156 24.552 30.24 ;
    END
  END o[63]
  PIN o[64]
    DIRECTION OUTPUT ;
    USE SIGNAL ;
    PORT
      LAYER M5 ;
        RECT  30.768 30.156 30.792 30.24 ;
    END
  END o[64]
  PIN o[65]
    DIRECTION OUTPUT ;
    USE SIGNAL ;
    PORT
      LAYER M5 ;
        RECT  30.864 30.156 30.888 30.24 ;
    END
  END o[65]
  PIN o[66]
    DIRECTION OUTPUT ;
    USE SIGNAL ;
    PORT
      LAYER M5 ;
        RECT  30.96 30.156 30.984 30.24 ;
    END
  END o[66]
  PIN o[67]
    DIRECTION OUTPUT ;
    USE SIGNAL ;
    PORT
      LAYER M5 ;
        RECT  31.056 30.156 31.08 30.24 ;
    END
  END o[67]
  PIN o[68]
    DIRECTION OUTPUT ;
    USE SIGNAL ;
    PORT
      LAYER M5 ;
        RECT  31.152 30.156 31.176 30.24 ;
    END
  END o[68]
  PIN o[69]
    DIRECTION OUTPUT ;
    USE SIGNAL ;
    PORT
      LAYER M5 ;
        RECT  31.248 30.156 31.272 30.24 ;
    END
  END o[69]
  PIN o[6]
    DIRECTION OUTPUT ;
    USE SIGNAL ;
    PORT
      LAYER M5 ;
        RECT  28.272 30.156 28.296 30.24 ;
    END
  END o[6]
  PIN o[70]
    DIRECTION OUTPUT ;
    USE SIGNAL ;
    PORT
      LAYER M5 ;
        RECT  31.344 30.156 31.368 30.24 ;
    END
  END o[70]
  PIN o[71]
    DIRECTION OUTPUT ;
    USE SIGNAL ;
    PORT
      LAYER M5 ;
        RECT  31.44 30.156 31.464 30.24 ;
    END
  END o[71]
  PIN o[72]
    DIRECTION OUTPUT ;
    USE SIGNAL ;
    PORT
      LAYER M5 ;
        RECT  31.536 30.156 31.56 30.24 ;
    END
  END o[72]
  PIN o[73]
    DIRECTION OUTPUT ;
    USE SIGNAL ;
    PORT
      LAYER M5 ;
        RECT  31.632 30.156 31.656 30.24 ;
    END
  END o[73]
  PIN o[74]
    DIRECTION OUTPUT ;
    USE SIGNAL ;
    PORT
      LAYER M5 ;
        RECT  31.728 30.156 31.752 30.24 ;
    END
  END o[74]
  PIN o[75]
    DIRECTION OUTPUT ;
    USE SIGNAL ;
    PORT
      LAYER M5 ;
        RECT  31.824 30.156 31.848 30.24 ;
    END
  END o[75]
  PIN o[76]
    DIRECTION OUTPUT ;
    USE SIGNAL ;
    PORT
      LAYER M5 ;
        RECT  31.92 30.156 31.944 30.24 ;
    END
  END o[76]
  PIN o[77]
    DIRECTION OUTPUT ;
    USE SIGNAL ;
    PORT
      LAYER M5 ;
        RECT  32.016 30.156 32.04 30.24 ;
    END
  END o[77]
  PIN o[78]
    DIRECTION OUTPUT ;
    USE SIGNAL ;
    PORT
      LAYER M5 ;
        RECT  32.112 30.156 32.136 30.24 ;
    END
  END o[78]
  PIN o[79]
    DIRECTION OUTPUT ;
    USE SIGNAL ;
    PORT
      LAYER M5 ;
        RECT  32.208 30.156 32.232 30.24 ;
    END
  END o[79]
  PIN o[7]
    DIRECTION OUTPUT ;
    USE SIGNAL ;
    PORT
      LAYER M5 ;
        RECT  28.368 30.156 28.392 30.24 ;
    END
  END o[7]
  PIN o[80]
    DIRECTION OUTPUT ;
    USE SIGNAL ;
    PORT
      LAYER M5 ;
        RECT  32.304 30.156 32.328 30.24 ;
    END
  END o[80]
  PIN o[81]
    DIRECTION OUTPUT ;
    USE SIGNAL ;
    PORT
      LAYER M5 ;
        RECT  32.4 30.156 32.424 30.24 ;
    END
  END o[81]
  PIN o[82]
    DIRECTION OUTPUT ;
    USE SIGNAL ;
    PORT
      LAYER M5 ;
        RECT  32.496 30.156 32.52 30.24 ;
    END
  END o[82]
  PIN o[83]
    DIRECTION OUTPUT ;
    USE SIGNAL ;
    PORT
      LAYER M5 ;
        RECT  32.592 30.156 32.616 30.24 ;
    END
  END o[83]
  PIN o[84]
    DIRECTION OUTPUT ;
    USE SIGNAL ;
    PORT
      LAYER M5 ;
        RECT  32.688 30.156 32.712 30.24 ;
    END
  END o[84]
  PIN o[85]
    DIRECTION OUTPUT ;
    USE SIGNAL ;
    PORT
      LAYER M5 ;
        RECT  32.784 30.156 32.808 30.24 ;
    END
  END o[85]
  PIN o[86]
    DIRECTION OUTPUT ;
    USE SIGNAL ;
    PORT
      LAYER M5 ;
        RECT  32.88 30.156 32.904 30.24 ;
    END
  END o[86]
  PIN o[87]
    DIRECTION OUTPUT ;
    USE SIGNAL ;
    PORT
      LAYER M5 ;
        RECT  32.976 30.156 33 30.24 ;
    END
  END o[87]
  PIN o[88]
    DIRECTION OUTPUT ;
    USE SIGNAL ;
    PORT
      LAYER M5 ;
        RECT  33.072 30.156 33.096 30.24 ;
    END
  END o[88]
  PIN o[89]
    DIRECTION OUTPUT ;
    USE SIGNAL ;
    PORT
      LAYER M5 ;
        RECT  33.168 30.156 33.192 30.24 ;
    END
  END o[89]
  PIN o[8]
    DIRECTION OUTPUT ;
    USE SIGNAL ;
    PORT
      LAYER M5 ;
        RECT  28.464 30.156 28.488 30.24 ;
    END
  END o[8]
  PIN o[90]
    DIRECTION OUTPUT ;
    USE SIGNAL ;
    PORT
      LAYER M5 ;
        RECT  33.264 30.156 33.288 30.24 ;
    END
  END o[90]
  PIN o[91]
    DIRECTION OUTPUT ;
    USE SIGNAL ;
    PORT
      LAYER M5 ;
        RECT  33.36 30.156 33.384 30.24 ;
    END
  END o[91]
  PIN o[92]
    DIRECTION OUTPUT ;
    USE SIGNAL ;
    PORT
      LAYER M5 ;
        RECT  33.456 30.156 33.48 30.24 ;
    END
  END o[92]
  PIN o[93]
    DIRECTION OUTPUT ;
    USE SIGNAL ;
    PORT
      LAYER M5 ;
        RECT  33.552 30.156 33.576 30.24 ;
    END
  END o[93]
  PIN o[94]
    DIRECTION OUTPUT ;
    USE SIGNAL ;
    PORT
      LAYER M5 ;
        RECT  33.648 30.156 33.672 30.24 ;
    END
  END o[94]
  PIN o[95]
    DIRECTION OUTPUT ;
    USE SIGNAL ;
    PORT
      LAYER M5 ;
        RECT  33.744 30.156 33.768 30.24 ;
    END
  END o[95]
  PIN o[96]
    DIRECTION OUTPUT ;
    USE SIGNAL ;
    PORT
      LAYER M5 ;
        RECT  15.408 30.156 15.432 30.24 ;
    END
  END o[96]
  PIN o[97]
    DIRECTION OUTPUT ;
    USE SIGNAL ;
    PORT
      LAYER M5 ;
        RECT  15.504 30.156 15.528 30.24 ;
    END
  END o[97]
  PIN o[98]
    DIRECTION OUTPUT ;
    USE SIGNAL ;
    PORT
      LAYER M5 ;
        RECT  15.6 30.156 15.624 30.24 ;
    END
  END o[98]
  PIN o[99]
    DIRECTION OUTPUT ;
    USE SIGNAL ;
    PORT
      LAYER M5 ;
        RECT  15.696 30.156 15.72 30.24 ;
    END
  END o[99]
  PIN o[9]
    DIRECTION OUTPUT ;
    USE SIGNAL ;
    PORT
      LAYER M5 ;
        RECT  28.56 30.156 28.584 30.24 ;
    END
  END o[9]
  PIN rs
    DIRECTION INPUT ;
    USE SIGNAL ;
    PORT
      LAYER M5 ;
        RECT  12.336 0 12.36 0.084 ;
    END
  END rs
  PIN VDD
    DIRECTION INOUT ;
    USE POWER ;
    PORT
      LAYER M5 ;
        RECT  29.592 2.151 29.712 28.089 ;
        RECT  24.192 2.151 24.312 28.089 ;
        RECT  18.792 2.151 18.912 28.089 ;
        RECT  13.392 2.151 13.512 28.089 ;
        RECT  7.992 2.151 8.112 28.089 ;
        RECT  2.592 2.151 2.712 28.089 ;
    END
  END VDD
  PIN VSS
    DIRECTION INOUT ;
    USE GROUND ;
    PORT
      LAYER M5 ;
        RECT  29.4 2.137 29.52 28.103 ;
        RECT  24 2.137 24.12 28.103 ;
        RECT  18.6 2.137 18.72 28.103 ;
        RECT  13.2 2.137 13.32 28.103 ;
        RECT  7.8 2.137 7.92 28.103 ;
        RECT  2.4 2.137 2.52 28.103 ;
    END
  END VSS
  # OT_OBS_CLOSED layer=M5 d_um=1.536 added=38
  OBS
    LAYER RVTN ;
     RECT  2.16 2.16 32.4 2.295 ;
     RECT  2.16 2.565 32.4 2.835 ;
     RECT  2.16 3.105 32.4 3.375 ;
     RECT  2.16 3.645 32.4 3.915 ;
     RECT  2.16 4.185 32.4 4.455 ;
     RECT  2.16 4.725 32.4 4.995 ;
     RECT  2.16 5.265 32.4 5.535 ;
     RECT  2.16 5.805 32.4 6.075 ;
     RECT  2.16 6.345 32.4 6.615 ;
     RECT  2.16 6.885 32.4 7.155 ;
     RECT  2.16 7.425 32.4 7.695 ;
     RECT  2.16 7.965 32.4 8.235 ;
     RECT  2.16 8.505 32.4 8.775 ;
     RECT  2.16 9.045 32.4 9.315 ;
     RECT  2.16 9.585 32.4 9.855 ;
     RECT  2.16 10.125 32.4 10.395 ;
     RECT  2.16 10.665 32.4 10.935 ;
     RECT  2.16 11.205 32.4 11.475 ;
     RECT  2.16 11.745 32.4 12.015 ;
     RECT  2.16 12.285 32.4 12.555 ;
     RECT  2.16 12.825 32.4 13.095 ;
     RECT  2.16 13.365 32.4 13.635 ;
     RECT  2.16 13.905 32.4 14.175 ;
     RECT  2.16 14.445 32.4 14.715 ;
     RECT  2.16 14.985 32.4 15.255 ;
     RECT  2.16 15.525 32.4 15.795 ;
     RECT  2.16 16.065 32.4 16.335 ;
     RECT  2.16 16.605 32.4 16.875 ;
     RECT  2.16 17.145 32.4 17.415 ;
     RECT  2.16 17.685 32.4 17.955 ;
     RECT  2.16 18.225 32.4 18.495 ;
     RECT  2.16 18.765 32.4 19.035 ;
     RECT  2.16 19.305 32.4 19.575 ;
     RECT  2.16 19.845 32.4 20.115 ;
     RECT  2.16 20.385 32.4 20.655 ;
     RECT  2.16 20.925 32.4 21.195 ;
     RECT  2.16 21.465 32.4 21.735 ;
     RECT  2.16 22.005 32.4 22.275 ;
     RECT  2.16 22.545 32.4 22.815 ;
     RECT  2.16 23.085 32.4 23.355 ;
     RECT  2.16 23.625 32.4 23.895 ;
     RECT  2.16 24.165 32.4 24.435 ;
     RECT  2.16 24.705 32.4 24.975 ;
     RECT  2.16 25.245 32.4 25.515 ;
     RECT  2.16 25.785 32.4 26.055 ;
     RECT  2.16 26.325 32.4 26.595 ;
     RECT  2.16 26.865 32.4 27.135 ;
     RECT  2.16 27.405 32.4 27.675 ;
     RECT  2.16 27.945 32.4 28.08 ;
    LAYER RVTP ;
     RECT  2.16 2.295 32.4 2.565 ;
     RECT  2.16 2.835 32.4 3.105 ;
     RECT  2.16 3.375 32.4 3.645 ;
     RECT  2.16 3.915 32.4 4.185 ;
     RECT  2.16 4.455 32.4 4.725 ;
     RECT  2.16 4.995 32.4 5.265 ;
     RECT  2.16 5.535 32.4 5.805 ;
     RECT  2.16 6.075 32.4 6.345 ;
     RECT  2.16 6.615 32.4 6.885 ;
     RECT  2.16 7.155 32.4 7.425 ;
     RECT  2.16 7.695 32.4 7.965 ;
     RECT  2.16 8.235 32.4 8.505 ;
     RECT  2.16 8.775 32.4 9.045 ;
     RECT  2.16 9.315 32.4 9.585 ;
     RECT  2.16 9.855 32.4 10.125 ;
     RECT  2.16 10.395 32.4 10.665 ;
     RECT  2.16 10.935 32.4 11.205 ;
     RECT  2.16 11.475 32.4 11.745 ;
     RECT  2.16 12.015 32.4 12.285 ;
     RECT  2.16 12.555 32.4 12.825 ;
     RECT  2.16 13.095 32.4 13.365 ;
     RECT  2.16 13.635 32.4 13.905 ;
     RECT  2.16 14.175 32.4 14.445 ;
     RECT  2.16 14.715 32.4 14.985 ;
     RECT  2.16 15.255 32.4 15.525 ;
     RECT  2.16 15.795 32.4 16.065 ;
     RECT  2.16 16.335 32.4 16.605 ;
     RECT  2.16 16.875 32.4 17.145 ;
     RECT  2.16 17.415 32.4 17.685 ;
     RECT  2.16 17.955 32.4 18.225 ;
     RECT  2.16 18.495 32.4 18.765 ;
     RECT  2.16 19.035 32.4 19.305 ;
     RECT  2.16 19.575 32.4 19.845 ;
     RECT  2.16 20.115 32.4 20.385 ;
     RECT  2.16 20.655 32.4 20.925 ;
     RECT  2.16 21.195 32.4 21.465 ;
     RECT  2.16 21.735 32.4 22.005 ;
     RECT  2.16 22.275 32.4 22.545 ;
     RECT  2.16 22.815 32.4 23.085 ;
     RECT  2.16 23.355 32.4 23.625 ;
     RECT  2.16 23.895 32.4 24.165 ;
     RECT  2.16 24.435 32.4 24.705 ;
     RECT  2.16 24.975 32.4 25.245 ;
     RECT  2.16 25.515 32.4 25.785 ;
     RECT  2.16 26.055 32.4 26.325 ;
     RECT  2.16 26.595 32.4 26.865 ;
     RECT  2.16 27.135 32.4 27.405 ;
     RECT  2.16 27.675 32.4 27.945 ;
    LAYER M1 ;
     RECT  2.16 2.151 32.4 28.089 ;
    LAYER M2 ;
     RECT  0.103 22.248 0.139 23.688 ;
     RECT  0.103 24.912 0.139 24.93 ;
     RECT  0.103 20.664 0.175 20.682 ;
     RECT  0.139 21.78 0.175 23.688 ;
     RECT  0.139 24.75 0.175 24.93 ;
     RECT  0.103 26.37 0.175 26.388 ;
     RECT  0.175 21.78 0.203 23.886 ;
     RECT  0.175 24.75 0.211 25.308 ;
     RECT  0.203 22.716 0.247 23.886 ;
     RECT  0.211 24.642 0.247 25.308 ;
     RECT  0.175 18.54 0.283 18.558 ;
     RECT  0.175 20.16 0.283 20.682 ;
     RECT  0.203 21.78 0.283 21.798 ;
     RECT  0.247 22.716 0.283 25.308 ;
     RECT  0.103 13.608 0.319 13.626 ;
     RECT  0.319 13.491 0.355 13.626 ;
     RECT  0.103 14.49 0.355 14.508 ;
     RECT  0.283 18.54 0.355 18.828 ;
     RECT  0.355 10.908 0.391 10.926 ;
     RECT  0.355 13.491 0.391 14.508 ;
     RECT  0.391 29.646 0.427 29.664 ;
     RECT  0.391 13.491 0.463 14.544 ;
     RECT  0.463 12.87 0.491 14.544 ;
     RECT  0.491 14.49 0.527 14.544 ;
     RECT  0.355 18.504 0.527 18.909 ;
     RECT  0.427 8.676 0.535 8.694 ;
     RECT  0.391 10.836 0.535 10.926 ;
     RECT  0.491 12.87 0.535 13.626 ;
     RECT  0.283 20.16 0.535 21.798 ;
     RECT  0.175 26.37 0.535 26.928 ;
     RECT  0.427 6.858 0.563 6.876 ;
     RECT  0.535 8.514 0.563 8.694 ;
     RECT  0.527 18.504 0.563 18.594 ;
     RECT  0.535 19.854 0.563 21.798 ;
     RECT  0.427 29.646 0.787 29.709 ;
     RECT  0.535 26.37 0.859 27.162 ;
     RECT  0.859 26.37 0.895 27.396 ;
     RECT  0.895 26.226 0.967 27.396 ;
     RECT  0.535 10.836 1.003 10.998 ;
     RECT  0.967 26.226 1.003 27.432 ;
     RECT  1.003 10.746 1.039 10.998 ;
     RECT  1.003 26.226 1.039 27.468 ;
     RECT  0.823 28.341 1.039 28.359 ;
     RECT  0.283 22.716 1.111 25.47 ;
     RECT  0.103 9.63 1.147 9.648 ;
     RECT  1.147 9.522 1.175 9.648 ;
     RECT  1.039 26.226 1.291 28.359 ;
     RECT  0.787 29.646 1.291 30.204 ;
     RECT  0.563 19.854 1.435 20.988 ;
     RECT  0.563 21.78 1.435 21.798 ;
     RECT  1.435 19.854 1.687 21.798 ;
     RECT  1.111 22.626 1.687 25.47 ;
     RECT  1.291 26.226 1.687 30.204 ;
     RECT  0.563 18.54 1.975 18.594 ;
     RECT  0.563 8.514 2.16 8.532 ;
     RECT  1.175 9.522 2.16 9.54 ;
     RECT  1.039 10.602 2.16 10.998 ;
     RECT  0.211 11.952 2.16 11.97 ;
     RECT  0.535 12.834 2.16 13.626 ;
     RECT  0.527 14.49 2.16 14.508 ;
     RECT  1.507 16.686 2.16 16.704 ;
     RECT  1.975 17.964 2.16 18.594 ;
     RECT  1.687 19.386 2.16 21.798 ;
     RECT  1.687 22.626 2.16 30.204 ;
     RECT  2.16 2.151 2.695 30.204 ;
     RECT  2.695 2.07 3.847 30.204 ;
     RECT  3.847 1.881 5.143 30.204 ;
     RECT  5.143 1.836 5.503 30.204 ;
     RECT  5.503 1.8 7.367 30.204 ;
     RECT  7.367 1.836 8.051 30.204 ;
     RECT  8.051 1.836 8.123 29.709 ;
     RECT  8.123 1.962 9.059 29.709 ;
     RECT  9.059 2.034 9.239 29.709 ;
     RECT  9.239 2.151 14.567 29.709 ;
     RECT  14.567 2.151 17.339 29.664 ;
     RECT  17.339 2.151 17.375 28.899 ;
     RECT  17.375 2.151 26.339 28.818 ;
     RECT  17.339 29.646 29.111 29.664 ;
     RECT  29.551 30.078 32.063 30.096 ;
     RECT  26.339 2.151 32.4 28.089 ;
     RECT  32.4 20.628 32.423 24.084 ;
     RECT  32.4 25.758 32.603 26.154 ;
     RECT  32.423 20.628 32.855 23.724 ;
     RECT  32.855 20.628 32.927 21.564 ;
     RECT  32.855 22.554 32.999 23.724 ;
     RECT  32.999 23.166 33.107 23.724 ;
     RECT  33.107 23.706 33.323 23.724 ;
     RECT  32.927 20.628 33.611 21.42 ;
     RECT  32.4 14.184 33.647 14.202 ;
     RECT  32.603 25.866 33.647 26.154 ;
     RECT  33.611 20.628 33.683 20.682 ;
     RECT  32.4 27.216 33.683 27.468 ;
     RECT  33.683 20.664 33.719 20.682 ;
     RECT  33.647 26.136 33.719 26.154 ;
     RECT  33.683 27.45 33.755 27.468 ;
    LAYER M3 ;
     RECT  5.508 1.795 5.526 1.831 ;
     RECT  2.304 1.771 2.322 1.867 ;
     RECT  3.096 1.579 3.114 1.867 ;
     RECT  3.924 1.675 3.942 1.876 ;
     RECT  5.148 1.831 5.526 1.876 ;
     RECT  3.852 1.876 3.942 1.957 ;
     RECT  5.148 1.876 5.562 1.957 ;
     RECT  5.148 1.957 6.138 2.029 ;
     RECT  7.344 1.795 7.362 2.029 ;
     RECT  8.1 1.831 8.118 2.029 ;
     RECT  9.036 1.957 9.054 2.029 ;
     RECT  3.852 1.957 4.338 2.065 ;
     RECT  5.148 2.029 6.246 2.065 ;
     RECT  3.852 2.065 6.246 2.101 ;
     RECT  7.344 2.029 8.118 2.101 ;
     RECT  2.304 1.867 3.114 2.155 ;
     RECT  2.268 2.155 3.114 2.191 ;
     RECT  3.852 2.101 8.118 2.191 ;
     RECT  9.036 2.029 9.234 2.191 ;
     RECT  12.132 1.723 12.15 2.255 ;
     RECT  8.856 2.191 9.486 2.263 ;
     RECT  2.268 2.191 8.118 2.299 ;
     RECT  8.856 2.263 9.594 2.299 ;
     RECT  10.872 2.191 10.89 2.299 ;
     RECT  2.268 2.299 9.594 2.327 ;
     RECT  2.304 2.327 9.594 2.335 ;
     RECT  10.368 2.299 10.89 2.335 ;
     RECT  12.06 2.263 12.078 2.335 ;
     RECT  2.304 2.335 10.89 2.371 ;
     RECT  11.88 2.335 12.078 2.371 ;
     RECT  13.215 2.143 13.305 2.413 ;
     RECT  18.615 2.143 18.705 2.413 ;
     RECT  24.015 2.143 24.105 2.413 ;
     RECT  29.415 2.143 29.505 2.413 ;
     RECT  0.324 2.443 0.342 2.573 ;
     RECT  0.216 2.587 0.234 2.765 ;
     RECT  2.304 2.371 12.078 3.101 ;
     RECT  2.304 3.101 11.682 3.211 ;
     RECT  2.268 3.211 11.682 3.299 ;
     RECT  2.268 3.299 11.61 3.335 ;
     RECT  2.268 3.335 10.89 3.407 ;
     RECT  2.304 3.407 10.89 4.225 ;
     RECT  2.232 4.225 10.89 4.397 ;
     RECT  2.268 4.397 10.89 4.531 ;
     RECT  2.268 4.531 11.034 4.919 ;
     RECT  2.304 4.919 11.034 5.071 ;
     RECT  0.54 3.835 0.558 5.179 ;
     RECT  0.54 5.179 0.882 5.419 ;
     RECT  0.324 5.419 0.882 5.549 ;
     RECT  2.304 5.071 11.322 5.611 ;
     RECT  2.304 5.611 11.394 5.881 ;
     RECT  2.304 5.881 11.754 5.999 ;
     RECT  2.304 5.999 11.394 6.475 ;
     RECT  2.268 6.475 11.394 6.619 ;
     RECT  0.54 5.549 0.882 6.853 ;
     RECT  0.432 6.853 0.882 7.051 ;
     RECT  0.324 7.051 0.882 7.181 ;
     RECT  1.944 6.619 11.394 7.195 ;
     RECT  1.944 7.195 11.646 7.339 ;
     RECT  1.944 7.339 11.862 7.771 ;
     RECT  0.432 7.181 0.882 7.867 ;
     RECT  13.215 2.413 13.497 7.933 ;
     RECT  0.432 7.867 1.17 7.997 ;
     RECT  0.432 7.997 0.882 9.163 ;
     RECT  1.944 7.771 12.474 9.211 ;
     RECT  13.215 7.933 13.77 9.211 ;
     RECT  0.324 9.163 0.882 9.517 ;
     RECT  0.324 9.517 1.17 9.625 ;
     RECT  0.108 9.625 1.17 9.653 ;
     RECT  14.796 9.751 14.814 9.851 ;
     RECT  0.108 9.653 0.882 9.869 ;
     RECT  1.944 9.211 13.77 10.291 ;
     RECT  1.944 10.291 14.058 10.471 ;
     RECT  0.324 9.869 0.882 10.597 ;
     RECT  1.944 10.471 14.346 10.651 ;
     RECT  1.872 10.651 14.346 10.741 ;
     RECT  1.872 10.741 14.85 10.831 ;
     RECT  1.872 10.831 14.958 11.281 ;
     RECT  16.164 10.867 16.182 11.281 ;
     RECT  0.324 10.597 1.062 11.707 ;
     RECT  1.872 11.281 16.182 11.707 ;
     RECT  0.324 11.707 16.182 11.947 ;
     RECT  0.216 11.947 16.182 12.091 ;
     RECT  0.216 12.091 16.254 12.451 ;
     RECT  0.216 12.451 16.326 12.479 ;
     RECT  17.676 11.983 17.694 12.559 ;
     RECT  0.216 12.479 13.734 12.619 ;
     RECT  16.164 12.479 16.326 12.757 ;
     RECT  17.208 12.559 17.694 12.757 ;
     RECT  0.144 12.619 13.734 12.797 ;
     RECT  16.164 12.757 17.694 12.797 ;
     RECT  18.615 2.413 18.897 12.811 ;
     RECT  0.324 12.797 13.734 12.893 ;
     RECT  18.615 12.811 19.494 12.901 ;
     RECT  17.208 12.797 17.694 13.085 ;
     RECT  17.676 13.085 17.694 13.261 ;
     RECT  18.504 12.901 19.494 13.261 ;
     RECT  16.164 12.797 16.47 13.289 ;
     RECT  16.452 13.289 16.47 13.361 ;
     RECT  17.676 13.261 19.494 13.361 ;
     RECT  0.324 12.893 12.474 13.603 ;
     RECT  18.072 13.361 19.494 13.837 ;
     RECT  25.92 13.837 25.938 13.873 ;
     RECT  14.724 12.479 15.426 13.901 ;
     RECT  18.072 13.837 19.674 13.901 ;
     RECT  0.108 13.603 12.474 13.945 ;
     RECT  13.215 12.893 13.734 13.945 ;
     RECT  19.656 13.901 19.674 14.009 ;
     RECT  0.108 13.945 13.734 14.071 ;
     RECT  14.724 13.901 14.958 14.071 ;
     RECT  16.812 13.711 16.83 14.099 ;
     RECT  18.072 13.901 18.897 14.099 ;
     RECT  18.576 14.099 18.897 14.237 ;
     RECT  0.108 14.071 14.958 14.369 ;
     RECT  17.748 14.143 17.838 14.369 ;
     RECT  28.152 13.819 28.17 14.443 ;
     RECT  28.152 14.443 28.242 14.521 ;
     RECT  28.152 14.521 28.422 14.573 ;
     RECT  17.82 14.369 17.838 14.813 ;
     RECT  27.144 13.675 27.162 15.061 ;
     RECT  24.015 2.413 24.297 15.151 ;
     RECT  25.92 13.873 26.154 15.163 ;
     RECT  27.036 15.061 27.162 15.163 ;
     RECT  0.108 14.369 14.922 15.179 ;
     RECT  28.152 14.573 28.17 15.211 ;
     RECT  25.92 15.163 27.162 15.293 ;
     RECT  0.108 15.179 13.734 15.341 ;
     RECT  27.936 15.211 28.17 15.448 ;
     RECT  27.936 15.448 28.278 15.485 ;
     RECT  0.324 15.341 13.734 15.821 ;
     RECT  23.904 15.151 24.297 15.835 ;
     RECT  14.652 15.179 14.922 15.871 ;
     RECT  16.02 15.499 16.038 15.871 ;
     RECT  25.92 15.293 26.226 16.027 ;
     RECT  27.036 15.293 27.162 16.027 ;
     RECT  14.652 15.871 16.038 16.141 ;
     RECT  17.244 15.295 17.262 16.141 ;
     RECT  23.364 15.835 24.297 16.267 ;
     RECT  25.92 16.027 27.162 16.303 ;
     RECT  27.936 15.485 28.17 16.303 ;
     RECT  14.652 16.141 17.262 16.403 ;
     RECT  14.724 16.403 17.262 16.529 ;
     RECT  18.615 14.237 18.897 16.603 ;
     RECT  17.964 16.603 18.897 16.645 ;
     RECT  19.656 16.411 19.674 16.645 ;
     RECT  23.364 16.267 24.858 16.651 ;
     RECT  22.572 15.331 22.59 16.879 ;
     RECT  21.384 15.187 21.402 16.915 ;
     RECT  22.572 16.879 22.626 16.915 ;
     RECT  21.384 16.915 22.626 17.149 ;
     RECT  0.396 15.821 13.734 17.179 ;
     RECT  20.772 17.149 22.626 17.221 ;
     RECT  25.92 16.303 28.17 17.311 ;
     RECT  29.415 2.413 29.697 17.311 ;
     RECT  20.556 17.221 22.626 17.339 ;
     RECT  0.144 17.179 13.734 17.357 ;
     RECT  20.628 17.339 22.626 17.383 ;
     RECT  23.364 16.651 24.93 17.383 ;
     RECT  20.628 17.383 24.93 17.447 ;
     RECT  20.628 17.447 20.646 17.483 ;
     RECT  21.384 17.447 24.93 17.483 ;
     RECT  23.364 17.483 24.93 17.725 ;
     RECT  23.364 17.725 25.11 17.923 ;
     RECT  25.92 17.311 29.697 17.923 ;
     RECT  23.364 17.923 29.697 18.149 ;
     RECT  0.396 17.357 13.734 18.379 ;
     RECT  0.324 18.379 13.734 18.535 ;
     RECT  14.724 16.529 16.65 18.535 ;
     RECT  21.384 17.483 22.626 18.535 ;
     RECT  32.184 18.499 32.202 18.535 ;
     RECT  14.508 18.535 16.65 18.571 ;
     RECT  21.384 18.535 22.77 18.805 ;
     RECT  17.964 16.645 19.674 18.833 ;
     RECT  0.18 18.535 13.734 18.841 ;
     RECT  14.508 18.571 16.794 18.841 ;
     RECT  0.18 18.841 16.794 18.893 ;
     RECT  21.312 18.805 22.77 19.099 ;
     RECT  19.656 18.833 19.674 19.339 ;
     RECT  20.448 18.499 20.466 19.339 ;
     RECT  21.312 19.099 22.842 19.571 ;
     RECT  0.288 18.893 16.794 19.771 ;
     RECT  17.964 18.833 18.897 20.083 ;
     RECT  19.656 19.339 20.466 20.083 ;
     RECT  21.312 19.571 22.77 20.347 ;
     RECT  23.58 18.149 29.697 20.347 ;
     RECT  17.964 20.083 20.466 20.425 ;
     RECT  21.312 20.347 29.697 20.425 ;
     RECT  33.624 14.179 33.642 20.623 ;
     RECT  0.144 19.771 16.794 20.659 ;
     RECT  33.624 20.623 33.678 20.659 ;
     RECT  17.964 20.425 29.697 20.731 ;
     RECT  30.672 17.383 30.69 20.731 ;
     RECT  31.644 18.535 32.202 20.731 ;
     RECT  31.644 20.731 32.526 20.929 ;
     RECT  17.964 20.731 30.69 20.965 ;
     RECT  31.644 20.929 32.634 20.965 ;
     RECT  17.964 20.965 32.634 21.001 ;
     RECT  17.676 21.001 32.634 21.091 ;
     RECT  0.108 20.659 16.794 21.361 ;
     RECT  17.676 21.091 32.886 21.361 ;
     RECT  0.108 21.361 32.886 21.397 ;
     RECT  33.624 20.659 33.714 21.397 ;
     RECT  0.108 21.397 33.714 22.555 ;
     RECT  0.108 22.555 33.75 25.517 ;
     RECT  0.144 25.517 33.75 26.365 ;
     RECT  0.108 26.365 33.75 27.149 ;
     RECT  0.144 27.149 33.75 27.473 ;
     RECT  0.144 27.473 33.318 27.869 ;
     RECT  24.015 27.869 33.318 27.905 ;
     RECT  0.144 27.869 15.966 27.917 ;
     RECT  19.944 27.869 19.962 27.917 ;
     RECT  0.216 27.917 15.966 27.941 ;
     RECT  16.812 27.869 18.99 27.941 ;
     RECT  24.015 27.905 28.314 27.941 ;
     RECT  27.936 27.941 27.954 27.965 ;
     RECT  29.052 27.905 33.318 27.965 ;
     RECT  5.832 27.941 6.498 28.061 ;
     RECT  16.812 27.941 18.705 28.061 ;
     RECT  24.015 27.941 25.398 28.061 ;
     RECT  29.052 27.965 30.186 28.061 ;
     RECT  7.416 27.941 15.966 28.097 ;
     RECT  16.92 28.061 18.705 28.097 ;
     RECT  24.015 28.061 24.426 28.097 ;
     RECT  0.216 27.941 4.878 28.109 ;
     RECT  8.532 28.097 15.966 28.139 ;
     RECT  8.532 28.139 12.546 28.157 ;
     RECT  7.416 28.097 7.434 28.247 ;
     RECT  24.336 28.097 24.426 28.253 ;
     RECT  24.408 28.253 24.426 28.301 ;
     RECT  16.92 28.097 18.45 28.349 ;
     RECT  29.088 28.061 30.186 28.445 ;
     RECT  26.136 27.941 27.198 28.493 ;
     RECT  21.636 27.869 21.654 28.517 ;
     RECT  9.9 28.157 12.546 28.541 ;
     RECT  25.38 28.061 25.398 28.541 ;
     RECT  8.532 28.157 8.91 28.553 ;
     RECT  10.26 28.541 12.546 28.685 ;
     RECT  0.396 28.109 4.878 28.751 ;
     RECT  5.976 28.061 6.498 28.781 ;
     RECT  11.628 28.685 12.546 28.781 ;
     RECT  26.136 28.493 26.982 28.787 ;
     RECT  13.68 28.139 15.966 28.795 ;
     RECT  16.92 28.349 18.018 28.795 ;
     RECT  11.628 28.781 12.474 28.823 ;
     RECT  2.772 28.751 4.878 29.029 ;
     RECT  13.68 28.795 18.018 29.069 ;
     RECT  21.78 28.891 21.798 29.069 ;
     RECT  0.396 28.751 1.998 29.093 ;
     RECT  10.26 28.685 10.638 29.093 ;
     RECT  26.172 28.787 26.982 29.117 ;
     RECT  12.168 28.823 12.474 29.129 ;
     RECT  2.772 29.029 5.022 29.165 ;
     RECT  10.476 29.093 10.638 29.165 ;
     RECT  13.68 29.069 17.154 29.174 ;
     RECT  26.172 29.117 26.298 29.213 ;
     RECT  29.088 28.445 29.862 29.213 ;
     RECT  0.396 29.093 1.89 29.219 ;
     RECT  13.68 29.174 16.542 29.255 ;
     RECT  3.528 29.165 5.022 29.261 ;
     RECT  0.396 29.219 1.782 29.291 ;
     RECT  13.68 29.255 16.002 29.291 ;
     RECT  3.636 29.261 5.022 29.327 ;
     RECT  13.752 29.291 16.002 29.327 ;
     RECT  2.772 29.165 2.79 29.357 ;
     RECT  0.396 29.291 1.746 29.363 ;
     RECT  13.752 29.327 15.57 29.363 ;
     RECT  3.636 29.327 3.654 29.405 ;
     RECT  0.396 29.363 1.53 29.444 ;
     RECT  14.544 29.363 15.57 29.444 ;
     RECT  10.476 29.165 10.494 29.645 ;
     RECT  15.552 29.444 15.57 29.645 ;
     RECT  31.068 27.965 33.318 29.645 ;
     RECT  6.48 28.781 6.498 29.659 ;
     RECT  0.396 29.444 1.494 29.669 ;
     RECT  29.088 29.213 29.682 29.669 ;
     RECT  18 29.069 18.018 29.693 ;
     RECT  29.304 29.669 29.682 29.693 ;
     RECT  31.068 29.645 31.266 29.693 ;
     RECT  8.532 28.553 8.802 29.707 ;
     RECT  0.432 29.669 1.494 29.714 ;
     RECT  14.544 29.444 14.562 29.714 ;
     RECT  31.248 29.693 31.266 29.741 ;
     RECT  4.392 29.327 5.022 29.851 ;
     RECT  6.48 29.659 6.822 29.899 ;
     RECT  8.424 29.707 8.802 29.899 ;
     RECT  19.548 29.851 19.566 29.899 ;
     RECT  4.392 29.851 5.166 29.981 ;
     RECT  19.548 29.899 19.782 29.995 ;
     RECT  18.828 29.995 19.782 30.029 ;
     RECT  4.392 29.981 5.022 30.065 ;
     RECT  6.48 29.899 6.894 30.065 ;
     RECT  6.48 30.065 6.498 30.077 ;
     RECT  19.62 30.029 19.782 30.091 ;
     RECT  32.04 29.645 33.318 30.101 ;
     RECT  5.004 30.065 5.022 30.125 ;
     RECT  8.028 29.899 8.802 30.125 ;
     RECT  12.168 29.129 12.186 30.125 ;
     RECT  13.752 29.363 13.77 30.125 ;
     RECT  18.828 30.029 18.846 30.125 ;
     RECT  19.62 30.091 19.926 30.125 ;
     RECT  23.004 29.947 23.022 30.125 ;
     RECT  29.304 29.693 29.574 30.125 ;
     RECT  32.724 30.101 33.318 30.125 ;
     RECT  0.792 29.714 1.494 30.173 ;
     RECT  8.028 30.125 8.73 30.173 ;
     RECT  0.792 30.173 0.81 30.209 ;
     RECT  8.028 30.173 8.046 30.209 ;
     RECT  19.908 30.125 19.926 30.221 ;
    LAYER M4 ;
     RECT  0.084 1.584 0.925 1.608 ;
     RECT  0.06 1.608 0.925 1.68 ;
     RECT  0.084 1.68 0.925 1.704 ;
     RECT  0.06 1.704 0.925 1.776 ;
     RECT  0.084 1.776 0.925 1.8 ;
     RECT  0.06 1.8 0.925 1.872 ;
     RECT  0.084 1.872 0.925 1.896 ;
     RECT  0.06 1.896 0.925 1.968 ;
     RECT  0.084 1.968 0.925 1.992 ;
     RECT  0.06 1.992 0.925 2.064 ;
     RECT  0.084 2.064 0.925 2.088 ;
     RECT  0.06 2.088 0.925 2.16 ;
     RECT  0.084 2.16 0.925 2.184 ;
     RECT  0.06 2.184 0.925 2.256 ;
     RECT  0.084 2.256 0.925 2.28 ;
     RECT  0.06 2.28 0.925 2.352 ;
     RECT  0.084 2.352 0.925 2.376 ;
     RECT  0.06 2.376 0.925 2.448 ;
     RECT  0.084 2.448 0.925 2.472 ;
     RECT  0.06 2.472 0.925 2.544 ;
     RECT  0.084 2.544 0.925 2.568 ;
     RECT  0.06 2.568 0.925 2.64 ;
     RECT  0.084 2.64 0.925 2.664 ;
     RECT  0.06 2.664 0.925 2.736 ;
     RECT  0.084 2.736 0.925 2.76 ;
     RECT  0.06 2.76 0.925 2.832 ;
     RECT  0.084 2.832 0.925 2.856 ;
     RECT  0.06 2.856 0.925 2.928 ;
     RECT  0.084 2.928 0.925 2.952 ;
     RECT  0.06 2.952 0.925 3.024 ;
     RECT  0.084 3.024 0.925 3.048 ;
     RECT  0.06 3.048 0.925 3.12 ;
     RECT  0.084 3.12 0.925 3.144 ;
     RECT  0.06 3.144 0.925 3.216 ;
     RECT  0.084 3.216 0.925 3.24 ;
     RECT  0.06 3.24 0.925 3.312 ;
     RECT  0.084 3.312 0.925 3.336 ;
     RECT  0.06 3.336 0.925 3.408 ;
     RECT  0.084 3.408 0.925 3.432 ;
     RECT  0.06 3.432 0.925 3.504 ;
     RECT  0.084 3.504 0.925 3.528 ;
     RECT  0.06 3.528 0.925 3.6 ;
     RECT  0.084 3.6 0.925 3.624 ;
     RECT  0.06 3.624 0.925 3.696 ;
     RECT  0.084 3.696 0.925 3.72 ;
     RECT  0.06 3.72 0.925 3.792 ;
     RECT  0.084 3.792 0.925 3.816 ;
     RECT  0.06 3.816 0.925 3.888 ;
     RECT  0.084 3.888 0.925 3.912 ;
     RECT  0.06 3.912 0.925 3.984 ;
     RECT  0.084 3.984 0.925 4.008 ;
     RECT  0.06 4.008 0.925 4.08 ;
     RECT  0.084 4.08 0.925 4.104 ;
     RECT  0.06 4.104 0.925 4.176 ;
     RECT  0.084 4.176 0.925 4.2 ;
     RECT  0.06 4.2 0.925 4.272 ;
     RECT  0.084 4.272 0.925 4.296 ;
     RECT  0.06 4.296 0.925 4.368 ;
     RECT  0.084 4.368 0.925 4.392 ;
     RECT  0.06 4.392 0.925 4.464 ;
     RECT  0.084 4.464 0.925 4.488 ;
     RECT  0.06 4.488 0.925 4.56 ;
     RECT  0.084 4.56 0.925 4.584 ;
     RECT  0.06 4.584 0.925 4.656 ;
     RECT  0.084 4.656 0.925 4.68 ;
     RECT  0.06 4.68 0.925 4.752 ;
     RECT  0.084 4.752 0.925 4.776 ;
     RECT  0.06 4.776 0.925 4.848 ;
     RECT  0.084 4.848 0.925 4.872 ;
     RECT  0.06 4.872 0.925 4.944 ;
     RECT  0.084 4.944 0.925 4.968 ;
     RECT  0.06 4.968 0.925 5.04 ;
     RECT  0.084 5.04 0.925 5.064 ;
     RECT  0.06 5.064 0.925 5.136 ;
     RECT  0.084 5.136 0.925 5.16 ;
     RECT  0.06 5.16 0.925 5.232 ;
     RECT  0.084 5.232 0.925 5.256 ;
     RECT  0.06 5.256 0.925 5.328 ;
     RECT  0.084 5.328 0.925 5.352 ;
     RECT  0.06 5.352 0.925 5.424 ;
     RECT  0.084 5.424 0.925 5.448 ;
     RECT  0.06 5.448 0.925 5.52 ;
     RECT  0.084 5.52 0.925 5.544 ;
     RECT  0.06 5.544 0.925 5.616 ;
     RECT  0.084 5.616 0.925 5.64 ;
     RECT  0.06 5.64 0.925 5.712 ;
     RECT  0.084 5.712 0.925 5.736 ;
     RECT  0.06 5.736 0.925 5.808 ;
     RECT  0.084 5.808 0.925 5.832 ;
     RECT  0.06 5.832 0.925 5.904 ;
     RECT  0.084 5.904 0.925 5.928 ;
     RECT  0.06 5.928 0.925 6 ;
     RECT  0.084 6 0.925 6.024 ;
     RECT  0.06 6.024 0.925 6.096 ;
     RECT  0.084 6.096 0.925 6.12 ;
     RECT  0.06 6.12 0.925 6.192 ;
     RECT  0.084 6.192 0.925 6.216 ;
     RECT  0.06 6.216 0.925 6.288 ;
     RECT  0.084 6.288 0.925 6.312 ;
     RECT  0.06 6.312 0.925 6.384 ;
     RECT  0.084 6.384 0.925 6.408 ;
     RECT  0.06 6.408 0.925 6.48 ;
     RECT  0.084 6.48 0.925 6.504 ;
     RECT  0.06 6.504 0.925 6.576 ;
     RECT  0.084 6.576 0.925 6.6 ;
     RECT  0.06 6.6 0.925 6.672 ;
     RECT  0.084 6.672 0.925 6.696 ;
     RECT  0.06 6.696 0.925 6.768 ;
     RECT  0.084 6.768 0.925 6.792 ;
     RECT  0.06 6.792 0.925 6.864 ;
     RECT  0.084 6.864 0.925 6.888 ;
     RECT  0.06 6.888 0.925 6.96 ;
     RECT  0.084 6.96 0.925 6.984 ;
     RECT  0.06 6.984 0.925 7.056 ;
     RECT  0.084 7.056 0.925 7.08 ;
     RECT  0.06 7.08 0.925 7.152 ;
     RECT  0.084 7.152 0.925 7.176 ;
     RECT  0.06 7.176 0.925 7.248 ;
     RECT  0.084 7.248 0.925 7.272 ;
     RECT  0.06 7.272 0.925 7.344 ;
     RECT  0.084 7.344 0.925 7.368 ;
     RECT  0.06 7.368 0.925 7.44 ;
     RECT  0.084 7.44 0.925 7.464 ;
     RECT  0.06 7.464 0.925 7.536 ;
     RECT  0.084 7.536 0.925 7.56 ;
     RECT  0.06 7.56 0.925 7.632 ;
     RECT  0.084 7.632 0.925 7.656 ;
     RECT  0.06 7.656 0.925 7.728 ;
     RECT  0.084 7.728 0.925 7.752 ;
     RECT  0.06 7.752 0.925 7.824 ;
     RECT  0.084 7.824 0.925 7.848 ;
     RECT  0.06 7.848 0.925 7.92 ;
     RECT  0.084 7.92 0.925 7.944 ;
     RECT  0.06 7.944 0.925 8.016 ;
     RECT  0.084 8.016 0.925 8.04 ;
     RECT  0.06 8.04 0.925 8.112 ;
     RECT  0.084 8.112 0.925 8.136 ;
     RECT  0.06 8.136 0.925 8.208 ;
     RECT  0.084 8.208 0.925 8.232 ;
     RECT  0.06 8.232 0.925 8.304 ;
     RECT  0.084 8.304 0.925 8.328 ;
     RECT  0.06 8.328 0.925 8.4 ;
     RECT  0.084 8.4 0.925 8.424 ;
     RECT  0.06 8.424 0.925 8.496 ;
     RECT  0.084 8.496 0.925 8.52 ;
     RECT  0.06 8.52 0.925 8.592 ;
     RECT  0.084 8.592 0.925 8.616 ;
     RECT  0.06 8.616 0.925 8.688 ;
     RECT  0.084 8.688 0.925 8.712 ;
     RECT  0.06 8.712 0.925 8.784 ;
     RECT  0.084 8.784 0.925 8.808 ;
     RECT  0.06 8.808 0.925 8.88 ;
     RECT  0.084 8.88 0.925 8.904 ;
     RECT  0.06 8.904 0.925 8.976 ;
     RECT  0.084 8.976 0.925 9 ;
     RECT  0.06 9 0.925 9.072 ;
     RECT  0.084 9.072 0.925 9.096 ;
     RECT  0.06 9.096 0.925 9.168 ;
     RECT  0.084 9.168 0.925 9.192 ;
     RECT  0.06 9.192 0.925 9.264 ;
     RECT  0.084 9.264 0.925 9.288 ;
     RECT  0.06 9.288 0.925 9.36 ;
     RECT  0.084 9.36 0.925 9.384 ;
     RECT  0.06 9.384 0.925 9.456 ;
     RECT  0.084 9.456 0.925 9.48 ;
     RECT  0.06 9.48 0.925 9.552 ;
     RECT  0.084 9.552 0.925 9.576 ;
     RECT  0.06 9.576 0.925 9.648 ;
     RECT  0.084 9.648 0.925 9.672 ;
     RECT  0.06 9.672 0.925 9.744 ;
     RECT  0.084 9.744 0.925 9.768 ;
     RECT  0.06 9.768 0.925 9.84 ;
     RECT  0.084 9.84 0.925 9.864 ;
     RECT  0.06 9.864 0.925 9.936 ;
     RECT  0.084 9.936 0.925 9.96 ;
     RECT  0.06 9.96 0.925 10.032 ;
     RECT  0.084 10.032 0.925 10.056 ;
     RECT  0.06 10.056 0.925 10.128 ;
     RECT  0.084 10.128 0.925 10.152 ;
     RECT  0.06 10.152 0.925 10.224 ;
     RECT  0.084 10.224 0.925 10.248 ;
     RECT  0.06 10.248 0.925 11.088 ;
     RECT  0.084 11.088 0.925 11.112 ;
     RECT  0.06 11.112 0.925 11.184 ;
     RECT  0.084 11.184 0.925 11.208 ;
     RECT  0.06 11.208 0.925 11.28 ;
     RECT  0.084 11.28 0.925 11.304 ;
     RECT  0.06 11.304 0.925 11.376 ;
     RECT  0.084 11.376 0.925 11.4 ;
     RECT  0.06 11.4 0.925 11.472 ;
     RECT  0.084 11.472 0.925 11.496 ;
     RECT  0.06 11.496 0.925 11.568 ;
     RECT  0.084 11.568 0.925 11.592 ;
     RECT  0.06 11.592 0.925 11.664 ;
     RECT  0.084 11.664 0.925 11.688 ;
     RECT  0.06 11.688 0.925 11.76 ;
     RECT  0.084 11.76 0.925 11.784 ;
     RECT  0.06 11.784 0.925 11.856 ;
     RECT  0.084 11.856 0.925 11.88 ;
     RECT  0.06 11.88 0.925 11.952 ;
     RECT  0.084 11.952 0.925 11.976 ;
     RECT  0.06 11.976 0.925 12.048 ;
     RECT  0.084 12.048 0.925 12.072 ;
     RECT  0.06 12.072 0.925 12.144 ;
     RECT  0.084 12.144 0.925 12.168 ;
     RECT  0.06 12.168 0.925 12.24 ;
     RECT  0.084 12.24 0.925 12.264 ;
     RECT  0.06 12.264 0.925 12.336 ;
     RECT  0.084 12.336 0.925 12.36 ;
     RECT  0.06 12.36 0.925 12.432 ;
     RECT  0.084 12.432 0.925 12.456 ;
     RECT  0.06 12.456 0.925 12.528 ;
     RECT  0.084 12.528 0.925 12.552 ;
     RECT  0.06 12.552 0.925 12.624 ;
     RECT  0.084 12.624 0.925 12.648 ;
     RECT  0.06 12.648 0.925 12.72 ;
     RECT  0.084 12.72 0.925 12.744 ;
     RECT  0.06 12.744 0.925 12.816 ;
     RECT  0.084 12.816 0.925 12.84 ;
     RECT  0.06 12.84 0.925 12.912 ;
     RECT  0.084 12.912 0.925 12.936 ;
     RECT  0.06 12.936 0.925 13.008 ;
     RECT  0.084 13.008 0.925 13.032 ;
     RECT  0.06 13.032 0.925 13.104 ;
     RECT  0.084 13.104 0.925 13.128 ;
     RECT  0.06 13.128 0.925 13.2 ;
     RECT  0.084 13.2 0.925 13.224 ;
     RECT  0.06 13.224 0.925 13.296 ;
     RECT  0.084 13.296 0.925 13.32 ;
     RECT  0.06 13.32 0.925 13.392 ;
     RECT  0.084 13.392 0.925 13.416 ;
     RECT  0.06 13.416 0.925 13.488 ;
     RECT  0.084 13.488 0.925 13.512 ;
     RECT  0.06 13.512 0.925 13.584 ;
     RECT  0.084 13.584 0.925 13.608 ;
     RECT  0.06 13.608 0.925 13.68 ;
     RECT  0.084 13.68 0.925 13.704 ;
     RECT  0.06 13.704 0.925 13.776 ;
     RECT  0.084 13.776 0.925 13.8 ;
     RECT  0.06 13.8 0.925 13.872 ;
     RECT  0.084 13.872 0.925 13.896 ;
     RECT  0.06 13.896 0.925 13.968 ;
     RECT  0.084 13.968 0.925 13.992 ;
     RECT  0.06 13.992 0.925 14.064 ;
     RECT  0.084 14.064 0.925 14.088 ;
     RECT  0.06 14.088 0.925 14.16 ;
     RECT  0.084 14.16 0.925 14.184 ;
     RECT  0.06 14.184 0.925 14.256 ;
     RECT  0.084 14.256 0.925 14.28 ;
     RECT  0.06 14.28 0.925 14.352 ;
     RECT  0.084 14.352 0.925 14.376 ;
     RECT  0.06 14.376 0.925 14.448 ;
     RECT  0.084 14.448 0.925 14.472 ;
     RECT  0.06 14.472 0.925 14.544 ;
     RECT  0.084 14.544 0.925 14.568 ;
     RECT  0.06 14.568 0.925 14.64 ;
     RECT  0.084 14.64 0.925 14.664 ;
     RECT  0.06 14.664 0.925 14.736 ;
     RECT  0.084 14.736 0.925 14.76 ;
     RECT  0.06 14.76 0.925 14.832 ;
     RECT  0.084 14.832 0.925 14.856 ;
     RECT  0.06 14.856 0.925 14.928 ;
     RECT  0.084 14.928 0.925 14.952 ;
     RECT  0.06 14.952 0.925 15.024 ;
     RECT  0.084 15.024 0.925 15.048 ;
     RECT  0.06 15.048 0.925 15.12 ;
     RECT  0.084 15.12 0.925 15.144 ;
     RECT  0.06 15.144 0.925 15.216 ;
     RECT  0.084 15.216 0.925 15.24 ;
     RECT  0.06 15.24 0.925 15.312 ;
     RECT  0.084 15.312 0.925 15.336 ;
     RECT  0.06 15.336 0.925 15.408 ;
     RECT  0.084 15.408 0.925 15.432 ;
     RECT  0.06 15.432 0.925 15.504 ;
     RECT  0.084 15.504 0.925 15.528 ;
     RECT  0.06 15.528 0.925 15.6 ;
     RECT  0.084 15.6 0.925 15.624 ;
     RECT  0.06 15.624 0.925 15.696 ;
     RECT  0.084 15.696 0.925 15.72 ;
     RECT  0.06 15.72 0.925 15.792 ;
     RECT  0.084 15.792 0.925 15.816 ;
     RECT  0.06 15.816 0.925 15.888 ;
     RECT  0.084 15.888 0.925 15.912 ;
     RECT  0.06 15.912 0.925 15.984 ;
     RECT  0.084 15.984 0.925 16.008 ;
     RECT  0.06 16.008 0.925 16.08 ;
     RECT  0.084 16.08 0.925 16.104 ;
     RECT  0.06 16.104 0.925 16.176 ;
     RECT  0.084 16.176 0.925 16.2 ;
     RECT  0.06 16.2 0.925 16.272 ;
     RECT  0.084 16.272 0.925 16.296 ;
     RECT  0.06 16.296 0.925 16.368 ;
     RECT  0.084 16.368 0.925 16.392 ;
     RECT  0.06 16.392 0.925 16.464 ;
     RECT  0.084 16.464 0.925 16.488 ;
     RECT  0.06 16.488 0.925 16.56 ;
     RECT  0.084 16.56 0.925 16.584 ;
     RECT  0.06 16.584 0.925 16.656 ;
     RECT  0.084 16.656 0.925 16.68 ;
     RECT  0.06 16.68 0.925 16.752 ;
     RECT  0.084 16.752 0.925 16.776 ;
     RECT  0.06 16.776 0.925 16.848 ;
     RECT  0.084 16.848 0.925 16.872 ;
     RECT  0.06 16.872 0.925 16.944 ;
     RECT  0.084 16.944 0.925 16.968 ;
     RECT  0.06 16.968 0.925 17.04 ;
     RECT  0.084 17.04 0.925 17.064 ;
     RECT  0.06 17.064 0.925 17.136 ;
     RECT  0.084 17.136 0.925 17.16 ;
     RECT  0.06 17.16 0.925 17.232 ;
     RECT  0.084 17.232 0.925 17.256 ;
     RECT  0.06 17.256 0.925 17.328 ;
     RECT  0.084 17.328 0.925 17.352 ;
     RECT  0.06 17.352 0.925 17.424 ;
     RECT  0.084 17.424 0.925 17.448 ;
     RECT  0.06 17.448 0.925 17.52 ;
     RECT  0.084 17.52 0.925 17.544 ;
     RECT  0.06 17.544 0.925 17.616 ;
     RECT  0.084 17.616 0.925 17.64 ;
     RECT  0.06 17.64 0.925 17.712 ;
     RECT  0.084 17.712 0.925 17.736 ;
     RECT  0.06 17.736 0.925 17.808 ;
     RECT  0.084 17.808 0.925 17.832 ;
     RECT  0.06 17.832 0.925 17.904 ;
     RECT  0.084 17.904 0.925 17.928 ;
     RECT  0.06 17.928 0.925 18 ;
     RECT  0.084 18 0.925 18.024 ;
     RECT  0.06 18.024 0.925 18.096 ;
     RECT  0.084 18.096 0.925 18.12 ;
     RECT  0.06 18.12 0.925 18.192 ;
     RECT  0.084 18.192 0.925 18.216 ;
     RECT  0.06 18.216 0.925 18.288 ;
     RECT  0.084 18.288 0.925 18.312 ;
     RECT  0.06 18.312 0.925 18.384 ;
     RECT  0.084 18.384 0.925 18.408 ;
     RECT  0.06 18.408 0.925 18.48 ;
     RECT  0.084 18.48 0.925 18.504 ;
     RECT  0.06 18.504 0.925 18.576 ;
     RECT  0.084 18.576 0.925 18.6 ;
     RECT  0.06 18.6 0.925 18.672 ;
     RECT  0.084 18.672 0.925 18.696 ;
     RECT  0.06 18.696 0.925 18.768 ;
     RECT  0.084 18.768 0.925 18.792 ;
     RECT  0.06 18.792 0.925 18.864 ;
     RECT  0.084 18.864 0.925 18.888 ;
     RECT  0.06 18.888 0.925 18.96 ;
     RECT  0.084 18.96 0.925 18.984 ;
     RECT  0.06 18.984 0.925 19.056 ;
     RECT  0.084 19.056 0.925 19.08 ;
     RECT  0.06 19.08 0.925 19.152 ;
     RECT  0.084 19.152 0.925 19.176 ;
     RECT  0.06 19.176 0.925 19.248 ;
     RECT  0.084 19.248 0.925 19.272 ;
     RECT  0.06 19.272 0.925 19.344 ;
     RECT  0.084 19.344 0.925 19.368 ;
     RECT  0.06 19.368 0.925 19.44 ;
     RECT  0.084 19.44 0.925 19.464 ;
     RECT  0.06 19.464 0.925 19.536 ;
     RECT  0.084 19.536 0.925 19.56 ;
     RECT  0.06 19.56 0.925 19.632 ;
     RECT  0.084 19.632 0.925 19.656 ;
     RECT  0.06 19.656 0.925 19.728 ;
     RECT  0.084 19.728 0.925 19.752 ;
     RECT  0.06 19.752 0.925 19.824 ;
     RECT  0.084 19.824 0.925 19.848 ;
     RECT  0.06 19.848 0.925 19.92 ;
     RECT  0.084 19.92 0.925 19.944 ;
     RECT  0.06 19.944 0.925 20.016 ;
     RECT  0.084 20.016 0.925 20.04 ;
     RECT  0.06 20.04 0.925 20.112 ;
     RECT  0.084 20.112 0.925 20.136 ;
     RECT  0.06 20.136 0.925 20.208 ;
     RECT  0.084 20.208 0.925 20.232 ;
     RECT  0.06 20.232 0.925 20.304 ;
     RECT  0.084 20.304 0.925 20.328 ;
     RECT  0.06 20.328 0.925 20.4 ;
     RECT  0.084 20.4 0.925 20.424 ;
     RECT  0.06 20.424 0.925 20.496 ;
     RECT  0.084 20.496 0.925 20.52 ;
     RECT  0.06 20.52 0.925 20.592 ;
     RECT  0.084 20.592 0.925 20.616 ;
     RECT  0.06 20.616 0.925 20.688 ;
     RECT  0.084 20.688 0.925 20.712 ;
     RECT  0.06 20.712 0.925 20.784 ;
     RECT  0.084 20.784 0.925 20.808 ;
     RECT  0.06 20.808 0.925 20.88 ;
     RECT  0.084 20.88 0.925 20.904 ;
     RECT  0.06 20.904 0.925 20.976 ;
     RECT  0.084 20.976 0.925 21 ;
     RECT  0.06 21 0.925 21.072 ;
     RECT  0.084 21.072 0.925 21.096 ;
     RECT  0.06 21.096 0.925 21.168 ;
     RECT  0.084 21.168 0.925 21.192 ;
     RECT  0.06 21.192 0.925 21.264 ;
     RECT  0.084 21.264 0.925 21.288 ;
     RECT  0.06 21.288 0.925 21.36 ;
     RECT  0.084 21.36 0.925 21.384 ;
     RECT  0.06 21.384 0.925 21.456 ;
     RECT  0.084 21.456 0.925 21.48 ;
     RECT  0.06 21.48 0.925 21.552 ;
     RECT  0.084 21.552 0.925 21.576 ;
     RECT  0.06 21.576 0.925 21.648 ;
     RECT  0.084 21.648 0.925 21.672 ;
     RECT  0.06 21.672 0.925 21.744 ;
     RECT  0.084 21.744 0.925 21.768 ;
     RECT  0.06 21.768 0.925 21.84 ;
     RECT  0.084 21.84 0.925 21.864 ;
     RECT  0.06 21.864 0.925 21.936 ;
     RECT  0.084 21.936 0.925 21.96 ;
     RECT  0.06 21.96 0.925 22.032 ;
     RECT  0.084 22.032 0.925 22.056 ;
     RECT  0.06 22.056 0.925 22.128 ;
     RECT  0.084 22.128 0.925 22.152 ;
     RECT  0.06 22.152 0.925 22.224 ;
     RECT  0.084 22.224 0.925 22.248 ;
     RECT  0.06 22.248 0.925 22.32 ;
     RECT  0.084 22.32 0.925 22.344 ;
     RECT  0.06 22.344 0.925 22.416 ;
     RECT  0.084 22.416 0.925 22.44 ;
     RECT  0.06 22.44 0.925 22.512 ;
     RECT  0.084 22.512 0.925 22.536 ;
     RECT  0.06 22.536 0.925 22.608 ;
     RECT  0.084 22.608 0.925 22.632 ;
     RECT  0.06 22.632 0.925 22.704 ;
     RECT  0.084 22.704 0.925 22.728 ;
     RECT  0.06 22.728 0.925 22.8 ;
     RECT  0.084 22.8 0.925 22.824 ;
     RECT  0.06 22.824 0.925 22.896 ;
     RECT  0.084 22.896 0.925 22.92 ;
     RECT  0.06 22.92 0.925 22.992 ;
     RECT  0.084 22.992 0.925 23.016 ;
     RECT  0.06 23.016 0.925 23.088 ;
     RECT  0.084 23.088 0.925 23.112 ;
     RECT  0.06 23.112 0.925 23.184 ;
     RECT  0.084 23.184 0.925 23.208 ;
     RECT  0.06 23.208 0.925 23.28 ;
     RECT  0.084 23.28 0.925 23.304 ;
     RECT  0.06 23.304 0.925 23.376 ;
     RECT  0.084 23.376 0.925 23.4 ;
     RECT  0.06 23.4 0.925 23.472 ;
     RECT  0.084 23.472 0.925 23.496 ;
     RECT  0.06 23.496 0.925 23.568 ;
     RECT  0.084 23.568 0.925 23.592 ;
     RECT  0.06 23.592 0.925 23.664 ;
     RECT  0.084 23.664 0.925 23.688 ;
     RECT  0.06 23.688 0.925 23.76 ;
     RECT  0.084 23.76 0.925 23.784 ;
     RECT  0.06 23.784 0.925 23.856 ;
     RECT  0.084 23.856 0.925 23.88 ;
     RECT  0.06 23.88 0.925 23.952 ;
     RECT  0.084 23.952 0.925 23.976 ;
     RECT  0.06 23.976 0.925 24.048 ;
     RECT  0.084 24.048 0.925 24.072 ;
     RECT  0.06 24.072 0.925 24.144 ;
     RECT  0.084 24.144 0.925 24.168 ;
     RECT  0.06 24.168 0.925 24.24 ;
     RECT  0.084 24.24 0.925 24.264 ;
     RECT  0.06 24.264 0.925 24.336 ;
     RECT  0.084 24.336 0.925 24.36 ;
     RECT  0.06 24.36 0.925 24.432 ;
     RECT  0.084 24.432 0.925 24.456 ;
     RECT  0.06 24.456 0.925 24.528 ;
     RECT  0.084 24.528 0.925 24.552 ;
     RECT  0.06 24.552 0.925 24.624 ;
     RECT  0.084 24.624 0.925 24.648 ;
     RECT  0.06 24.648 0.925 24.72 ;
     RECT  0.084 24.72 0.925 24.744 ;
     RECT  0.06 24.744 0.925 24.816 ;
     RECT  0.084 24.816 0.925 24.84 ;
     RECT  0.06 24.84 0.925 24.912 ;
     RECT  0.084 24.912 0.925 24.936 ;
     RECT  0.06 24.936 0.925 25.008 ;
     RECT  0.084 25.008 0.925 25.032 ;
     RECT  0.06 25.032 0.925 25.104 ;
     RECT  0.084 25.104 0.925 25.128 ;
     RECT  0.06 25.128 0.925 25.2 ;
     RECT  0.084 25.2 0.925 25.224 ;
     RECT  0.06 25.224 0.925 25.296 ;
     RECT  0.084 25.296 0.925 25.32 ;
     RECT  0.06 25.32 0.925 25.392 ;
     RECT  0.084 25.392 0.925 25.416 ;
     RECT  0.06 25.416 0.925 25.488 ;
     RECT  0.084 25.488 0.925 25.512 ;
     RECT  0.06 25.512 0.925 25.584 ;
     RECT  0.084 25.584 0.925 25.608 ;
     RECT  0.06 25.608 0.925 25.68 ;
     RECT  0.084 25.68 0.925 25.704 ;
     RECT  0.06 25.704 0.925 25.776 ;
     RECT  0.084 25.776 0.925 25.8 ;
     RECT  0.06 25.8 0.925 25.872 ;
     RECT  0.084 25.872 0.925 25.896 ;
     RECT  0.06 25.896 0.925 25.968 ;
     RECT  0.084 25.968 0.925 25.992 ;
     RECT  0.06 25.992 0.925 26.064 ;
     RECT  0.084 26.064 0.925 26.088 ;
     RECT  0.06 26.088 0.925 26.16 ;
     RECT  0.084 26.16 0.925 26.184 ;
     RECT  0.06 26.184 0.925 26.256 ;
     RECT  0.084 26.256 0.925 26.28 ;
     RECT  0.06 26.28 0.925 26.352 ;
     RECT  0.084 26.352 0.925 26.376 ;
     RECT  0.06 26.376 0.925 26.448 ;
     RECT  0.084 26.448 0.925 26.472 ;
     RECT  0.06 26.472 0.925 26.544 ;
     RECT  0.084 26.544 0.925 26.568 ;
     RECT  0.06 26.568 0.925 26.64 ;
     RECT  0.084 26.64 0.925 26.664 ;
     RECT  0.06 26.664 0.925 26.736 ;
     RECT  0.084 26.736 0.925 26.76 ;
     RECT  0.06 26.76 0.925 26.832 ;
     RECT  0.084 26.832 0.925 26.856 ;
     RECT  0.06 26.856 0.925 26.928 ;
     RECT  0.084 26.928 0.925 26.952 ;
     RECT  0.06 26.952 0.925 27.024 ;
     RECT  0.084 27.024 0.925 27.048 ;
     RECT  0.06 27.048 0.925 27.12 ;
     RECT  0.084 27.12 0.925 27.144 ;
     RECT  0.06 27.144 0.925 27.216 ;
     RECT  0.084 27.216 0.925 27.24 ;
     RECT  0.06 27.24 0.925 27.312 ;
     RECT  0.084 27.312 0.925 27.336 ;
     RECT  0.06 27.336 0.925 27.408 ;
     RECT  0.084 27.408 0.925 27.432 ;
     RECT  0.06 27.432 0.925 27.504 ;
     RECT  0.084 27.504 0.925 27.528 ;
     RECT  0.06 27.528 0.925 27.6 ;
     RECT  0.084 27.6 0.925 27.624 ;
     RECT  0.06 27.624 0.925 27.696 ;
     RECT  0.084 27.696 0.925 27.72 ;
     RECT  0.06 27.72 0.925 27.792 ;
     RECT  0.084 27.792 0.925 27.816 ;
     RECT  0.06 27.816 0.925 27.888 ;
     RECT  0.084 27.888 0.925 27.912 ;
     RECT  0.06 27.912 0.925 27.984 ;
     RECT  0.084 27.984 0.925 28.008 ;
     RECT  0.06 28.008 0.925 28.08 ;
     RECT  0.084 28.08 0.925 28.104 ;
     RECT  0.06 28.104 0.925 28.176 ;
     RECT  0.084 28.176 0.925 28.2 ;
     RECT  0.06 28.2 0.925 28.272 ;
     RECT  0.084 28.272 0.925 28.296 ;
     RECT  0.06 28.296 0.925 28.368 ;
     RECT  0.084 28.368 0.925 28.392 ;
     RECT  0.06 28.392 0.925 28.464 ;
     RECT  0.084 28.464 0.925 28.488 ;
     RECT  0.06 28.488 0.925 28.56 ;
     RECT  0.084 28.56 0.925 28.584 ;
     RECT  0.06 28.584 0.925 28.656 ;
     RECT  0.084 28.656 0.925 28.68 ;
     RECT  0.06 28.68 0.925 28.752 ;
     RECT  0.084 28.752 0.925 28.776 ;
     RECT  0.06 28.776 0.925 28.848 ;
     RECT  0.084 28.848 0.925 28.872 ;
     RECT  0.06 28.872 0.925 28.944 ;
     RECT  0.084 28.944 0.925 28.968 ;
     RECT  0.06 28.968 0.925 29.04 ;
     RECT  0.084 29.04 0.925 29.064 ;
     RECT  0.06 29.064 0.925 29.136 ;
     RECT  0.084 29.136 0.925 29.16 ;
     RECT  0.06 29.16 0.925 29.232 ;
     RECT  0.084 29.232 0.925 29.256 ;
     RECT  0.06 29.256 0.925 29.328 ;
     RECT  0.084 29.328 0.925 29.352 ;
     RECT  0.06 29.352 0.925 29.424 ;
     RECT  0.084 29.424 0.925 29.448 ;
     RECT  0.925 1.584 1.465 29.976 ;
     RECT  1.465 1.584 3.125 30.168 ;
     RECT  3.125 1.68 3.953 30.168 ;
     RECT  3.953 2.544 4.921 30.168 ;
     RECT  4.921 2.496 6.325 30.168 ;
     RECT  6.325 2.352 7.808 30.168 ;
     RECT  7.808 2.148 7.912 30.168 ;
     RECT  7.912 2.304 8.741 30.168 ;
     RECT  8.741 2.304 8.813 30.12 ;
     RECT  8.813 2.304 8.867 30.072 ;
     RECT  8.867 2.304 9.973 30.024 ;
     RECT  9.973 2.304 10.145 30.072 ;
     RECT  10.145 3.84 10.163 30.072 ;
     RECT  10.163 3.84 10.253 29.64 ;
     RECT  10.145 2.304 10.397 2.856 ;
     RECT  10.253 4.32 10.505 29.64 ;
     RECT  10.505 4.32 10.757 29.208 ;
     RECT  10.397 2.304 10.793 2.328 ;
     RECT  10.757 4.32 10.901 4.344 ;
     RECT  10.757 5.328 11.009 29.208 ;
     RECT  11.009 5.952 11.081 29.208 ;
     RECT  11.081 5.952 11.189 8.376 ;
     RECT  11.189 6.768 11.555 8.376 ;
     RECT  11.555 7.248 11.585 8.376 ;
     RECT  11.585 7.248 12.035 7.416 ;
     RECT  11.081 9.6 12.037 29.208 ;
     RECT  12.037 9.6 12.113 29.496 ;
     RECT  12.035 7.344 12.131 7.416 ;
     RECT  12.113 9.6 12.197 30.12 ;
     RECT  12.197 9.6 12.233 29.208 ;
     RECT  12.121 1.728 12.371 1.752 ;
     RECT  12.233 9.6 13.057 10.392 ;
     RECT  12.233 11.664 13.189 29.208 ;
     RECT  12.131 7.392 13.208 7.416 ;
     RECT  13.057 9.552 13.208 10.392 ;
     RECT  13.189 11.664 13.208 30.072 ;
     RECT  13.208 2.148 13.312 30.072 ;
     RECT  13.312 2.418 13.504 30.072 ;
     RECT  13.504 11.664 13.573 30.072 ;
     RECT  13.504 9.552 13.745 10.392 ;
     RECT  13.573 11.664 13.781 30.12 ;
     RECT  13.745 10.368 14.069 10.392 ;
     RECT  13.781 11.664 14.465 30.072 ;
     RECT  14.465 12.768 14.773 30.072 ;
     RECT  14.465 11.664 15.041 11.784 ;
     RECT  15.041 11.664 15.437 11.688 ;
     RECT  14.773 12.768 18.608 30.216 ;
     RECT  18.608 2.148 18.712 30.216 ;
     RECT  18.712 2.418 18.904 30.216 ;
     RECT  18.904 12.768 19.937 30.216 ;
     RECT  19.937 12.768 19.981 30.12 ;
     RECT  19.981 12.768 20.195 30.072 ;
     RECT  20.195 13.68 20.531 30.072 ;
     RECT  20.531 13.68 21.541 30.024 ;
     RECT  21.541 13.68 22.885 30.072 ;
     RECT  22.885 13.68 23.033 30.12 ;
     RECT  23.033 13.68 24.008 30.072 ;
     RECT  24.008 2.148 24.112 30.072 ;
     RECT  24.112 2.418 24.304 30.072 ;
     RECT  24.304 13.68 25.661 18.168 ;
     RECT  24.304 19.248 25.949 30.072 ;
     RECT  25.949 19.248 26.885 21.528 ;
     RECT  26.885 20.592 27.061 21.528 ;
     RECT  25.949 22.56 27.061 30.072 ;
     RECT  25.661 13.68 27.173 17.4 ;
     RECT  27.061 20.592 27.203 30.072 ;
     RECT  26.885 19.248 27.251 19.512 ;
     RECT  27.251 19.248 27.605 19.272 ;
     RECT  27.203 20.592 27.971 30.024 ;
     RECT  27.971 22.56 28.165 30.024 ;
     RECT  27.173 13.824 28.181 17.4 ;
     RECT  28.181 14.448 28.217 17.4 ;
     RECT  28.217 14.448 28.253 16.872 ;
     RECT  28.165 22.56 29.293 30.072 ;
     RECT  28.253 14.544 29.408 16.872 ;
     RECT  27.971 20.592 29.408 21.432 ;
     RECT  29.293 22.56 29.408 30.12 ;
     RECT  29.408 2.148 29.512 30.12 ;
     RECT  29.512 2.418 29.585 30.12 ;
     RECT  29.585 2.418 29.704 30.024 ;
     RECT  29.704 21.408 30.757 30.024 ;
     RECT  30.757 21.408 31.429 30.072 ;
     RECT  31.429 21.408 31.925 30.12 ;
     RECT  31.925 21.408 31.957 23.976 ;
     RECT  31.957 21.216 32.101 23.976 ;
     RECT  31.925 25.632 32.105 30.12 ;
     RECT  32.101 21.12 32.465 23.976 ;
     RECT  32.465 21.408 32.531 23.976 ;
     RECT  32.531 21.408 32.627 23.4 ;
     RECT  32.627 21.456 32.723 23.4 ;
     RECT  32.105 29.568 32.897 30.12 ;
     RECT  32.105 25.632 33.005 28.584 ;
     RECT  32.723 21.456 33.011 23.064 ;
     RECT  29.704 14.64 33.155 16.872 ;
     RECT  33.155 15.456 33.251 16.872 ;
     RECT  33.005 25.728 33.251 28.584 ;
     RECT  33.251 15.696 33.299 16.872 ;
     RECT  33.251 25.728 33.299 26.52 ;
     RECT  32.897 30.096 33.329 30.12 ;
     RECT  33.299 15.696 33.347 15.72 ;
     RECT  33.251 27.792 33.347 28.584 ;
     RECT  33.299 16.848 33.395 16.872 ;
     RECT  33.299 25.728 33.395 26.232 ;
     RECT  33.347 28.56 33.395 28.584 ;
     RECT  33.011 21.552 33.491 23.064 ;
     RECT  33.395 26.208 33.587 26.232 ;
     RECT  33.491 22.176 33.683 23.064 ;
     RECT  33.683 22.56 33.761 23.064 ;
     RECT  33.761 23.04 33.779 23.064 ;
    LAYER M5 ;
     RECT  12.264 0.016 12.336 0.084 ;
     RECT  12.24 0.084 12.36 2.137 ;
     RECT  2.4 2.137 2.52 2.151 ;
     RECT  7.8 2.137 7.92 2.151 ;
     RECT  12.24 2.137 13.32 2.151 ;
     RECT  18.6 2.137 18.72 2.151 ;
     RECT  24 2.137 24.12 2.151 ;
     RECT  29.4 2.137 29.52 2.151 ;
     RECT  0.144 2.533 0.168 2.819 ;
     RECT  4.512 2.773 4.536 2.915 ;
     RECT  7.8 2.151 8.112 4.117 ;
     RECT  9.504 3.061 9.528 4.163 ;
     RECT  7.44 4.117 8.112 5.125 ;
     RECT  0.912 4.213 0.936 5.269 ;
     RECT  3.84 5.173 3.864 5.315 ;
     RECT  7.056 5.125 8.112 5.317 ;
     RECT  2.4 2.151 2.712 5.365 ;
     RECT  7.056 5.317 8.616 5.459 ;
     RECT  0.144 5.269 0.936 5.555 ;
     RECT  4.128 5.365 4.152 5.651 ;
     RECT  2.4 5.365 3.048 5.749 ;
     RECT  9.504 5.653 9.624 5.797 ;
     RECT  4.656 5.797 5.304 5.987 ;
     RECT  7.056 5.459 8.376 6.035 ;
     RECT  9.504 5.797 10.344 6.229 ;
     RECT  4.656 5.987 5.16 6.613 ;
     RECT  12.24 2.151 13.512 6.757 ;
     RECT  2.304 5.749 3.048 6.805 ;
     RECT  7.68 6.035 8.376 6.805 ;
     RECT  9.504 6.229 10.488 6.805 ;
     RECT  11.52 6.757 13.512 6.805 ;
     RECT  4.08 6.613 5.16 6.851 ;
     RECT  6.48 6.181 6.504 6.997 ;
     RECT  7.68 6.805 13.512 6.997 ;
     RECT  0.912 5.555 0.936 7.141 ;
     RECT  4.704 6.851 5.16 7.237 ;
     RECT  0.144 7.141 0.936 7.427 ;
     RECT  4.704 7.237 5.352 7.429 ;
     RECT  6.48 6.997 13.512 7.429 ;
     RECT  2.208 6.805 3.048 7.717 ;
     RECT  2.208 7.717 3.336 7.957 ;
     RECT  4.704 7.429 13.512 7.957 ;
     RECT  2.208 7.957 13.512 8.245 ;
     RECT  0.912 7.427 0.936 9.253 ;
     RECT  0.144 9.253 0.936 10.069 ;
     RECT  2.112 8.245 13.512 10.069 ;
     RECT  0.144 10.069 13.512 10.163 ;
     RECT  17.28 13.045 17.304 13.573 ;
     RECT  18.6 2.151 18.912 13.573 ;
     RECT  15.552 13.621 15.576 14.197 ;
     RECT  29.4 2.151 29.712 14.533 ;
     RECT  0.912 10.163 13.512 15.205 ;
     RECT  28.896 14.533 29.712 15.253 ;
     RECT  33.12 14.629 33.144 15.445 ;
     RECT  33.12 15.445 33.24 15.685 ;
     RECT  0.144 15.205 13.512 15.971 ;
     RECT  33.12 15.685 33.336 16.837 ;
     RECT  15.552 14.197 15.864 17.941 ;
     RECT  17.28 13.573 18.912 17.941 ;
     RECT  0.24 15.971 13.512 18.229 ;
     RECT  0.144 18.229 13.512 18.803 ;
     RECT  0.912 18.803 13.512 20.293 ;
     RECT  0.144 20.293 13.512 20.483 ;
     RECT  0.912 20.483 13.512 20.629 ;
     RECT  24 2.151 24.312 20.629 ;
     RECT  0.912 20.629 13.8 20.963 ;
     RECT  27.216 19.477 27.24 21.109 ;
     RECT  27.216 21.109 27.432 21.157 ;
     RECT  33.12 16.837 33.384 21.397 ;
     RECT  27.216 21.157 27.768 21.445 ;
     RECT  32.592 21.397 33.384 21.541 ;
     RECT  26.688 21.445 27.768 21.637 ;
     RECT  28.896 15.253 29.832 21.637 ;
     RECT  32.592 21.541 33.48 21.637 ;
     RECT  26.688 21.637 33.48 22.165 ;
     RECT  24 20.629 25.272 22.213 ;
     RECT  26.688 22.165 33.672 22.213 ;
     RECT  24 22.213 33.672 22.789 ;
     RECT  23.184 22.789 33.672 23.029 ;
     RECT  0.912 20.963 13.512 23.317 ;
     RECT  15.552 17.941 18.912 23.317 ;
     RECT  20.16 12.757 20.184 23.317 ;
     RECT  21.216 23.221 21.24 23.317 ;
     RECT  23.184 23.029 33.768 23.317 ;
     RECT  15.552 23.317 20.184 23.365 ;
     RECT  21.216 23.317 33.768 23.365 ;
     RECT  15.552 23.365 33.768 23.797 ;
     RECT  0.912 23.317 13.656 23.989 ;
     RECT  15.504 23.797 33.768 23.989 ;
     RECT  0.912 23.989 13.944 24.277 ;
     RECT  15.36 23.989 33.768 24.277 ;
     RECT  0.144 24.277 33.768 24.467 ;
     RECT  0.912 24.467 33.768 27.443 ;
     RECT  5.808 27.443 33.768 27.731 ;
     RECT  0.912 27.443 4.68 27.827 ;
     RECT  0.912 27.827 4.536 28.211 ;
     RECT  4.368 28.211 4.536 28.307 ;
     RECT  6 27.731 33.768 28.741 ;
     RECT  0.912 28.211 3.24 28.787 ;
     RECT  0.912 28.787 2.328 28.835 ;
     RECT  0.912 28.835 1.464 29.267 ;
     RECT  0.912 29.267 0.936 29.315 ;
     RECT  4.368 28.307 4.392 29.699 ;
     RECT  5.904 28.741 33.768 30.156 ;
     RECT  5.928 30.156 6 30.224 ;
     RECT  6.024 30.156 6.096 30.224 ;
     RECT  6.12 30.156 6.192 30.224 ;
     RECT  6.216 30.156 6.288 30.224 ;
     RECT  6.312 30.156 6.384 30.224 ;
     RECT  6.408 30.156 6.48 30.224 ;
     RECT  6.504 30.156 6.576 30.224 ;
     RECT  6.6 30.156 6.672 30.224 ;
     RECT  6.696 30.156 6.768 30.224 ;
     RECT  6.792 30.156 6.864 30.224 ;
     RECT  6.888 30.156 6.96 30.224 ;
     RECT  6.984 30.156 7.056 30.224 ;
     RECT  7.08 30.156 7.152 30.224 ;
     RECT  7.176 30.156 7.248 30.224 ;
     RECT  7.272 30.156 7.344 30.224 ;
     RECT  7.368 30.156 7.44 30.224 ;
     RECT  7.464 30.156 7.536 30.224 ;
     RECT  7.56 30.156 7.632 30.224 ;
     RECT  7.656 30.156 7.728 30.224 ;
     RECT  7.752 30.156 7.824 30.224 ;
     RECT  7.848 30.156 7.92 30.224 ;
     RECT  7.944 30.156 8.016 30.224 ;
     RECT  8.04 30.156 8.112 30.224 ;
     RECT  8.136 30.156 8.208 30.224 ;
     RECT  8.232 30.156 8.304 30.224 ;
     RECT  8.328 30.156 8.4 30.224 ;
     RECT  8.424 30.156 8.496 30.224 ;
     RECT  8.52 30.156 8.592 30.224 ;
     RECT  8.616 30.156 8.688 30.224 ;
     RECT  8.712 30.156 8.784 30.224 ;
     RECT  8.808 30.156 8.88 30.224 ;
     RECT  8.904 30.156 8.976 30.224 ;
     RECT  9 30.156 9.072 30.224 ;
     RECT  9.096 30.156 9.168 30.224 ;
     RECT  9.192 30.156 9.264 30.224 ;
     RECT  9.288 30.156 9.36 30.224 ;
     RECT  9.384 30.156 9.456 30.224 ;
     RECT  9.48 30.156 9.552 30.224 ;
     RECT  9.576 30.156 9.648 30.224 ;
     RECT  9.672 30.156 9.744 30.224 ;
     RECT  9.768 30.156 9.84 30.224 ;
     RECT  9.864 30.156 9.936 30.224 ;
     RECT  9.96 30.156 10.032 30.224 ;
     RECT  10.056 30.156 10.128 30.224 ;
     RECT  10.152 30.156 10.224 30.224 ;
     RECT  10.248 30.156 10.32 30.224 ;
     RECT  10.344 30.156 10.416 30.224 ;
     RECT  10.44 30.156 10.512 30.224 ;
     RECT  10.536 30.156 10.608 30.224 ;
     RECT  10.632 30.156 10.704 30.224 ;
     RECT  10.728 30.156 10.8 30.224 ;
     RECT  10.824 30.156 10.896 30.224 ;
     RECT  10.92 30.156 10.992 30.224 ;
     RECT  11.016 30.156 11.088 30.224 ;
     RECT  11.112 30.156 11.184 30.224 ;
     RECT  11.208 30.156 11.28 30.224 ;
     RECT  11.304 30.156 11.376 30.224 ;
     RECT  11.4 30.156 11.472 30.224 ;
     RECT  11.496 30.156 11.568 30.224 ;
     RECT  11.592 30.156 11.664 30.224 ;
     RECT  11.688 30.156 11.76 30.224 ;
     RECT  11.784 30.156 11.856 30.224 ;
     RECT  11.88 30.156 11.952 30.224 ;
     RECT  11.976 30.156 12.048 30.224 ;
     RECT  12.072 30.156 12.144 30.224 ;
     RECT  12.168 30.156 12.24 30.224 ;
     RECT  12.264 30.156 12.336 30.224 ;
     RECT  12.36 30.156 12.432 30.224 ;
     RECT  12.456 30.156 12.528 30.224 ;
     RECT  12.552 30.156 12.624 30.224 ;
     RECT  12.648 30.156 12.72 30.224 ;
     RECT  12.744 30.156 12.816 30.224 ;
     RECT  12.84 30.156 12.912 30.224 ;
     RECT  12.936 30.156 13.008 30.224 ;
     RECT  13.032 30.156 13.104 30.224 ;
     RECT  13.128 30.156 13.2 30.224 ;
     RECT  13.224 30.156 13.296 30.224 ;
     RECT  13.32 30.156 13.392 30.224 ;
     RECT  13.416 30.156 13.488 30.224 ;
     RECT  13.512 30.156 13.584 30.224 ;
     RECT  13.608 30.156 13.68 30.224 ;
     RECT  13.704 30.156 13.776 30.224 ;
     RECT  13.8 30.156 13.872 30.224 ;
     RECT  13.896 30.156 13.968 30.224 ;
     RECT  13.992 30.156 14.064 30.224 ;
     RECT  14.088 30.156 14.16 30.224 ;
     RECT  14.184 30.156 14.256 30.224 ;
     RECT  14.28 30.156 14.352 30.224 ;
     RECT  14.376 30.156 14.448 30.224 ;
     RECT  14.472 30.156 14.544 30.224 ;
     RECT  14.568 30.156 15.408 30.224 ;
     RECT  15.432 30.156 15.504 30.224 ;
     RECT  15.528 30.156 15.6 30.224 ;
     RECT  15.624 30.156 15.696 30.224 ;
     RECT  15.72 30.156 15.792 30.224 ;
     RECT  15.816 30.156 15.888 30.224 ;
     RECT  15.912 30.156 15.984 30.224 ;
     RECT  16.008 30.156 16.08 30.224 ;
     RECT  16.104 30.156 16.176 30.224 ;
     RECT  16.2 30.156 16.272 30.224 ;
     RECT  16.296 30.156 16.368 30.224 ;
     RECT  16.392 30.156 16.464 30.224 ;
     RECT  16.488 30.156 16.56 30.224 ;
     RECT  16.584 30.156 16.656 30.224 ;
     RECT  16.68 30.156 16.752 30.224 ;
     RECT  16.776 30.156 16.848 30.224 ;
     RECT  16.872 30.156 16.944 30.224 ;
     RECT  16.968 30.156 17.04 30.224 ;
     RECT  17.064 30.156 17.136 30.224 ;
     RECT  17.16 30.156 17.232 30.224 ;
     RECT  17.256 30.156 17.328 30.224 ;
     RECT  17.352 30.156 17.424 30.224 ;
     RECT  17.448 30.156 17.52 30.224 ;
     RECT  17.544 30.156 17.616 30.224 ;
     RECT  17.64 30.156 17.712 30.224 ;
     RECT  17.736 30.156 17.808 30.224 ;
     RECT  17.832 30.156 17.904 30.224 ;
     RECT  17.928 30.156 18 30.224 ;
     RECT  18.024 30.156 18.096 30.224 ;
     RECT  18.12 30.156 18.192 30.224 ;
     RECT  18.216 30.156 18.288 30.224 ;
     RECT  18.312 30.156 18.384 30.224 ;
     RECT  18.408 30.156 18.48 30.224 ;
     RECT  18.504 30.156 18.576 30.224 ;
     RECT  18.6 30.156 18.672 30.224 ;
     RECT  18.696 30.156 18.768 30.224 ;
     RECT  18.792 30.156 18.864 30.224 ;
     RECT  18.888 30.156 18.96 30.224 ;
     RECT  18.984 30.156 19.056 30.224 ;
     RECT  19.08 30.156 19.152 30.224 ;
     RECT  19.176 30.156 19.248 30.224 ;
     RECT  19.272 30.156 19.344 30.224 ;
     RECT  19.368 30.156 19.44 30.224 ;
     RECT  19.464 30.156 19.536 30.224 ;
     RECT  19.56 30.156 19.632 30.224 ;
     RECT  19.656 30.156 19.728 30.224 ;
     RECT  19.752 30.156 19.824 30.224 ;
     RECT  19.848 30.156 19.92 30.224 ;
     RECT  19.944 30.156 20.016 30.224 ;
     RECT  20.04 30.156 20.112 30.224 ;
     RECT  20.136 30.156 20.208 30.224 ;
     RECT  20.232 30.156 20.304 30.224 ;
     RECT  20.328 30.156 20.4 30.224 ;
     RECT  20.424 30.156 20.496 30.224 ;
     RECT  20.52 30.156 20.592 30.224 ;
     RECT  20.616 30.156 20.688 30.224 ;
     RECT  20.712 30.156 20.784 30.224 ;
     RECT  20.808 30.156 20.88 30.224 ;
     RECT  20.904 30.156 20.976 30.224 ;
     RECT  21 30.156 21.072 30.224 ;
     RECT  21.096 30.156 21.168 30.224 ;
     RECT  21.192 30.156 21.264 30.224 ;
     RECT  21.288 30.156 21.36 30.224 ;
     RECT  21.384 30.156 21.456 30.224 ;
     RECT  21.48 30.156 21.552 30.224 ;
     RECT  21.576 30.156 21.648 30.224 ;
     RECT  21.672 30.156 21.744 30.224 ;
     RECT  21.768 30.156 21.84 30.224 ;
     RECT  21.864 30.156 21.936 30.224 ;
     RECT  21.96 30.156 22.032 30.224 ;
     RECT  22.056 30.156 22.128 30.224 ;
     RECT  22.152 30.156 22.224 30.224 ;
     RECT  22.248 30.156 22.32 30.224 ;
     RECT  22.344 30.156 22.416 30.224 ;
     RECT  22.44 30.156 22.512 30.224 ;
     RECT  22.536 30.156 22.608 30.224 ;
     RECT  22.632 30.156 22.704 30.224 ;
     RECT  22.728 30.156 22.8 30.224 ;
     RECT  22.824 30.156 22.896 30.224 ;
     RECT  22.92 30.156 22.992 30.224 ;
     RECT  23.016 30.156 23.088 30.224 ;
     RECT  23.112 30.156 23.184 30.224 ;
     RECT  23.208 30.156 23.28 30.224 ;
     RECT  23.304 30.156 23.376 30.224 ;
     RECT  23.4 30.156 23.472 30.224 ;
     RECT  23.496 30.156 23.568 30.224 ;
     RECT  23.592 30.156 23.664 30.224 ;
     RECT  23.688 30.156 23.76 30.224 ;
     RECT  23.784 30.156 23.856 30.224 ;
     RECT  23.88 30.156 23.952 30.224 ;
     RECT  23.976 30.156 24.048 30.224 ;
     RECT  24.072 30.156 24.144 30.224 ;
     RECT  24.168 30.156 24.24 30.224 ;
     RECT  24.264 30.156 24.336 30.224 ;
     RECT  24.36 30.156 24.432 30.224 ;
     RECT  24.456 30.156 24.528 30.224 ;
     RECT  24.552 30.156 24.624 30.224 ;
     RECT  24.648 30.156 24.72 30.224 ;
     RECT  24.744 30.156 24.816 30.224 ;
     RECT  24.84 30.156 24.912 30.224 ;
     RECT  24.936 30.156 25.008 30.224 ;
     RECT  25.032 30.156 25.104 30.224 ;
     RECT  25.128 30.156 25.2 30.224 ;
     RECT  25.224 30.156 25.296 30.224 ;
     RECT  25.32 30.156 25.392 30.224 ;
     RECT  25.416 30.156 25.488 30.224 ;
     RECT  25.512 30.156 25.584 30.224 ;
     RECT  25.608 30.156 25.68 30.224 ;
     RECT  25.704 30.156 25.776 30.224 ;
     RECT  25.8 30.156 25.872 30.224 ;
     RECT  25.896 30.156 25.968 30.224 ;
     RECT  25.992 30.156 26.064 30.224 ;
     RECT  26.088 30.156 26.16 30.224 ;
     RECT  26.184 30.156 26.256 30.224 ;
     RECT  26.28 30.156 26.352 30.224 ;
     RECT  26.376 30.156 26.448 30.224 ;
     RECT  26.472 30.156 26.544 30.224 ;
     RECT  26.568 30.156 26.64 30.224 ;
     RECT  26.664 30.156 26.736 30.224 ;
     RECT  26.76 30.156 26.832 30.224 ;
     RECT  26.856 30.156 26.928 30.224 ;
     RECT  26.952 30.156 27.024 30.224 ;
     RECT  27.048 30.156 27.12 30.224 ;
     RECT  27.144 30.156 27.216 30.224 ;
     RECT  27.24 30.156 27.312 30.224 ;
     RECT  27.336 30.156 27.408 30.224 ;
     RECT  27.432 30.156 27.504 30.224 ;
     RECT  27.528 30.156 27.6 30.224 ;
     RECT  27.624 30.156 27.696 30.224 ;
     RECT  27.72 30.156 27.792 30.224 ;
     RECT  27.816 30.156 27.888 30.224 ;
     RECT  27.912 30.156 27.984 30.224 ;
     RECT  28.008 30.156 28.08 30.224 ;
     RECT  28.104 30.156 28.176 30.224 ;
     RECT  28.2 30.156 28.272 30.224 ;
     RECT  28.296 30.156 28.368 30.224 ;
     RECT  28.392 30.156 28.464 30.224 ;
     RECT  28.488 30.156 28.56 30.224 ;
     RECT  28.584 30.156 28.656 30.224 ;
     RECT  28.68 30.156 28.752 30.224 ;
     RECT  28.776 30.156 28.848 30.224 ;
     RECT  28.872 30.156 28.944 30.224 ;
     RECT  28.968 30.156 29.04 30.224 ;
     RECT  29.064 30.156 29.136 30.224 ;
     RECT  29.16 30.156 29.232 30.224 ;
     RECT  29.256 30.156 29.328 30.224 ;
     RECT  29.352 30.156 29.424 30.224 ;
     RECT  29.448 30.156 29.52 30.224 ;
     RECT  29.544 30.156 29.616 30.224 ;
     RECT  29.64 30.156 29.712 30.224 ;
     RECT  29.736 30.156 29.808 30.224 ;
     RECT  29.832 30.156 29.904 30.224 ;
     RECT  29.928 30.156 30 30.224 ;
     RECT  30.024 30.156 30.096 30.224 ;
     RECT  30.12 30.156 30.192 30.224 ;
     RECT  30.216 30.156 30.288 30.224 ;
     RECT  30.312 30.156 30.384 30.224 ;
     RECT  30.408 30.156 30.48 30.224 ;
     RECT  30.504 30.156 30.576 30.224 ;
     RECT  30.6 30.156 30.672 30.224 ;
     RECT  30.696 30.156 30.768 30.224 ;
     RECT  30.792 30.156 30.864 30.224 ;
     RECT  30.888 30.156 30.96 30.224 ;
     RECT  30.984 30.156 31.056 30.224 ;
     RECT  31.08 30.156 31.152 30.224 ;
     RECT  31.176 30.156 31.248 30.224 ;
     RECT  31.272 30.156 31.344 30.224 ;
     RECT  31.368 30.156 31.44 30.224 ;
     RECT  31.464 30.156 31.536 30.224 ;
     RECT  31.56 30.156 31.632 30.224 ;
     RECT  31.656 30.156 31.728 30.224 ;
     RECT  31.752 30.156 31.824 30.224 ;
     RECT  31.848 30.156 31.92 30.224 ;
     RECT  31.944 30.156 32.016 30.224 ;
     RECT  32.04 30.156 32.112 30.224 ;
     RECT  32.136 30.156 32.208 30.224 ;
     RECT  32.232 30.156 32.304 30.224 ;
     RECT  32.328 30.156 32.4 30.224 ;
     RECT  32.424 30.156 32.496 30.224 ;
     RECT  32.52 30.156 32.592 30.224 ;
     RECT  32.616 30.156 32.688 30.224 ;
     RECT  32.712 30.156 32.784 30.224 ;
     RECT  32.808 30.156 32.88 30.224 ;
     RECT  32.904 30.156 32.976 30.224 ;
     RECT  33 30.156 33.072 30.224 ;
     RECT  33.096 30.156 33.168 30.224 ;
     RECT  33.192 30.156 33.264 30.224 ;
     RECT  33.288 30.156 33.36 30.224 ;
     RECT  33.384 30.156 33.456 30.224 ;
     RECT  33.48 30.156 33.552 30.224 ;
     RECT  33.576 30.156 33.648 30.224 ;
     RECT  33.672 30.156 33.744 30.224 ;
     RECT  14.784 30.224 14.808 30.227 ;
     RECT  8.112 3.061 9.504 4.163 ;
     RECT  8.112 4.163 9.528 5.317 ;
     RECT  0.936 4.213 2.4 5.749 ;
     RECT  2.712 5.173 3.84 5.315 ;
     RECT  2.712 5.315 3.864 5.365 ;
     RECT  8.616 5.317 9.528 5.459 ;
     RECT  3.048 5.365 4.128 5.651 ;
     RECT  8.376 5.459 9.528 5.653 ;
     RECT  3.048 5.651 4.152 5.797 ;
     RECT  8.376 5.653 9.504 6.805 ;
     RECT  0.936 5.749 2.304 6.805 ;
     RECT  3.048 5.797 4.656 6.613 ;
     RECT  5.16 5.987 5.304 6.181 ;
     RECT  7.056 6.035 7.68 6.181 ;
     RECT  5.16 6.181 6.48 7.237 ;
     RECT  6.504 6.181 7.68 6.997 ;
     RECT  3.048 6.613 4.08 6.851 ;
     RECT  10.488 6.757 11.52 6.805 ;
     RECT  0.936 6.805 2.208 8.245 ;
     RECT  3.048 6.851 4.704 7.717 ;
     RECT  5.352 7.237 6.48 7.429 ;
     RECT  3.336 7.717 4.704 7.957 ;
     RECT  0.936 8.245 2.112 10.069 ;
     RECT  18.912 12.757 20.16 23.317 ;
     RECT  17.304 13.045 18.6 13.573 ;
     RECT  15.864 14.197 17.28 17.941 ;
     RECT  0.144 18.803 0.912 20.293 ;
     RECT  27.432 21.109 28.896 21.157 ;
     RECT  27.768 21.157 28.896 21.637 ;
     RECT  25.272 21.445 26.688 22.213 ;
     RECT  20.184 23.221 21.216 23.365 ;
     RECT  13.944 23.989 15.36 24.277 ;
     RECT  4.68 27.443 5.808 27.731 ;
     RECT  4.68 27.731 6 27.827 ;
     RECT  4.536 27.827 6 28.307 ;
     RECT  3.24 28.211 4.368 28.787 ;
     RECT  4.392 28.307 6 28.741 ;
     RECT  4.392 28.741 5.904 29.699 ;
  END
END dsfd_rly_283_WN
END LIBRARY
